VERSION 5.8 ;
BUSBITCHARS "[]" ;
DIVIDERCHAR "/" ;
UNITS
    DATABASE MICRONS 1000 ;
END UNITS

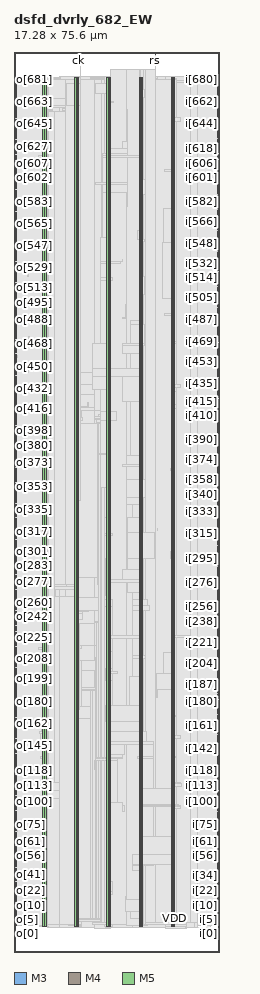
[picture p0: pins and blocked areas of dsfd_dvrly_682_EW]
MACRO dsfd_dvrly_682_EW
  FOREIGN dsfd_dvrly_682_EW 0 0 ;
  CLASS BLOCK ;
  SIZE 17.28 BY 75.6 ;
  PIN ck
    DIRECTION INPUT ;
    USE SIGNAL ;
    PORT
      LAYER M3 ;
        RECT  5.4 75.456 5.418 75.6 ;
    END
  END ck
  PIN ck_o
    DIRECTION OUTPUT ;
    USE SIGNAL ;
    PORT
      LAYER M4 ;
        RECT  0 73.392 0.192 73.416 ;
    END
  END ck_o
  PIN i[0]
    DIRECTION INPUT ;
    USE SIGNAL ;
    PORT
      LAYER M4 ;
        RECT  17.088 2.208 17.28 2.232 ;
    END
  END i[0]
  PIN i[100]
    DIRECTION INPUT ;
    USE SIGNAL ;
    PORT
      LAYER M4 ;
        RECT  17.088 12.672 17.28 12.696 ;
    END
  END i[100]
  PIN i[101]
    DIRECTION INPUT ;
    USE SIGNAL ;
    PORT
      LAYER M4 ;
        RECT  17.088 12.768 17.28 12.792 ;
    END
  END i[101]
  PIN i[102]
    DIRECTION INPUT ;
    USE SIGNAL ;
    PORT
      LAYER M4 ;
        RECT  17.088 12.864 17.28 12.888 ;
    END
  END i[102]
  PIN i[103]
    DIRECTION INPUT ;
    USE SIGNAL ;
    PORT
      LAYER M4 ;
        RECT  17.088 13.008 17.28 13.032 ;
    END
  END i[103]
  PIN i[104]
    DIRECTION INPUT ;
    USE SIGNAL ;
    PORT
      LAYER M4 ;
        RECT  17.088 13.104 17.28 13.128 ;
    END
  END i[104]
  PIN i[105]
    DIRECTION INPUT ;
    USE SIGNAL ;
    PORT
      LAYER M4 ;
        RECT  17.088 13.2 17.28 13.224 ;
    END
  END i[105]
  PIN i[106]
    DIRECTION INPUT ;
    USE SIGNAL ;
    PORT
      LAYER M4 ;
        RECT  17.088 13.296 17.28 13.32 ;
    END
  END i[106]
  PIN i[107]
    DIRECTION INPUT ;
    USE SIGNAL ;
    PORT
      LAYER M4 ;
        RECT  17.088 13.392 17.28 13.416 ;
    END
  END i[107]
  PIN i[108]
    DIRECTION INPUT ;
    USE SIGNAL ;
    PORT
      LAYER M4 ;
        RECT  17.088 13.488 17.28 13.512 ;
    END
  END i[108]
  PIN i[109]
    DIRECTION INPUT ;
    USE SIGNAL ;
    PORT
      LAYER M4 ;
        RECT  17.088 13.632 17.28 13.656 ;
    END
  END i[109]
  PIN i[10]
    DIRECTION INPUT ;
    USE SIGNAL ;
    PORT
      LAYER M4 ;
        RECT  17.088 3.264 17.28 3.288 ;
    END
  END i[10]
  PIN i[110]
    DIRECTION INPUT ;
    USE SIGNAL ;
    PORT
      LAYER M4 ;
        RECT  17.088 13.728 17.28 13.752 ;
    END
  END i[110]
  PIN i[111]
    DIRECTION INPUT ;
    USE SIGNAL ;
    PORT
      LAYER M4 ;
        RECT  17.088 13.824 17.28 13.848 ;
    END
  END i[111]
  PIN i[112]
    DIRECTION INPUT ;
    USE SIGNAL ;
    PORT
      LAYER M4 ;
        RECT  17.088 13.92 17.28 13.944 ;
    END
  END i[112]
  PIN i[113]
    DIRECTION INPUT ;
    USE SIGNAL ;
    PORT
      LAYER M4 ;
        RECT  17.088 14.016 17.28 14.04 ;
    END
  END i[113]
  PIN i[114]
    DIRECTION INPUT ;
    USE SIGNAL ;
    PORT
      LAYER M4 ;
        RECT  17.088 14.16 17.28 14.184 ;
    END
  END i[114]
  PIN i[115]
    DIRECTION INPUT ;
    USE SIGNAL ;
    PORT
      LAYER M4 ;
        RECT  17.088 14.256 17.28 14.28 ;
    END
  END i[115]
  PIN i[116]
    DIRECTION INPUT ;
    USE SIGNAL ;
    PORT
      LAYER M4 ;
        RECT  17.088 14.352 17.28 14.376 ;
    END
  END i[116]
  PIN i[117]
    DIRECTION INPUT ;
    USE SIGNAL ;
    PORT
      LAYER M4 ;
        RECT  17.088 14.448 17.28 14.472 ;
    END
  END i[117]
  PIN i[118]
    DIRECTION INPUT ;
    USE SIGNAL ;
    PORT
      LAYER M4 ;
        RECT  17.088 14.544 17.28 14.568 ;
    END
  END i[118]
  PIN i[119]
    DIRECTION INPUT ;
    USE SIGNAL ;
    PORT
      LAYER M4 ;
        RECT  17.088 14.64 17.28 14.664 ;
    END
  END i[119]
  PIN i[11]
    DIRECTION INPUT ;
    USE SIGNAL ;
    PORT
      LAYER M4 ;
        RECT  17.088 3.36 17.28 3.384 ;
    END
  END i[11]
  PIN i[120]
    DIRECTION INPUT ;
    USE SIGNAL ;
    PORT
      LAYER M4 ;
        RECT  17.088 14.784 17.28 14.808 ;
    END
  END i[120]
  PIN i[121]
    DIRECTION INPUT ;
    USE SIGNAL ;
    PORT
      LAYER M4 ;
        RECT  17.088 14.88 17.28 14.904 ;
    END
  END i[121]
  PIN i[122]
    DIRECTION INPUT ;
    USE SIGNAL ;
    PORT
      LAYER M4 ;
        RECT  17.088 14.976 17.28 15 ;
    END
  END i[122]
  PIN i[123]
    DIRECTION INPUT ;
    USE SIGNAL ;
    PORT
      LAYER M4 ;
        RECT  17.088 15.072 17.28 15.096 ;
    END
  END i[123]
  PIN i[124]
    DIRECTION INPUT ;
    USE SIGNAL ;
    PORT
      LAYER M4 ;
        RECT  17.088 15.168 17.28 15.192 ;
    END
  END i[124]
  PIN i[125]
    DIRECTION INPUT ;
    USE SIGNAL ;
    PORT
      LAYER M4 ;
        RECT  17.088 15.312 17.28 15.336 ;
    END
  END i[125]
  PIN i[126]
    DIRECTION INPUT ;
    USE SIGNAL ;
    PORT
      LAYER M4 ;
        RECT  17.088 15.408 17.28 15.432 ;
    END
  END i[126]
  PIN i[127]
    DIRECTION INPUT ;
    USE SIGNAL ;
    PORT
      LAYER M4 ;
        RECT  17.088 15.504 17.28 15.528 ;
    END
  END i[127]
  PIN i[128]
    DIRECTION INPUT ;
    USE SIGNAL ;
    PORT
      LAYER M4 ;
        RECT  17.088 15.6 17.28 15.624 ;
    END
  END i[128]
  PIN i[129]
    DIRECTION INPUT ;
    USE SIGNAL ;
    PORT
      LAYER M4 ;
        RECT  17.088 15.696 17.28 15.72 ;
    END
  END i[129]
  PIN i[12]
    DIRECTION INPUT ;
    USE SIGNAL ;
    PORT
      LAYER M4 ;
        RECT  17.088 3.456 17.28 3.48 ;
    END
  END i[12]
  PIN i[130]
    DIRECTION INPUT ;
    USE SIGNAL ;
    PORT
      LAYER M4 ;
        RECT  17.088 15.792 17.28 15.816 ;
    END
  END i[130]
  PIN i[131]
    DIRECTION INPUT ;
    USE SIGNAL ;
    PORT
      LAYER M4 ;
        RECT  17.088 15.936 17.28 15.96 ;
    END
  END i[131]
  PIN i[132]
    DIRECTION INPUT ;
    USE SIGNAL ;
    PORT
      LAYER M4 ;
        RECT  17.088 16.032 17.28 16.056 ;
    END
  END i[132]
  PIN i[133]
    DIRECTION INPUT ;
    USE SIGNAL ;
    PORT
      LAYER M4 ;
        RECT  17.088 16.128 17.28 16.152 ;
    END
  END i[133]
  PIN i[134]
    DIRECTION INPUT ;
    USE SIGNAL ;
    PORT
      LAYER M4 ;
        RECT  17.088 16.224 17.28 16.248 ;
    END
  END i[134]
  PIN i[135]
    DIRECTION INPUT ;
    USE SIGNAL ;
    PORT
      LAYER M4 ;
        RECT  17.088 16.32 17.28 16.344 ;
    END
  END i[135]
  PIN i[136]
    DIRECTION INPUT ;
    USE SIGNAL ;
    PORT
      LAYER M4 ;
        RECT  17.088 16.416 17.28 16.44 ;
    END
  END i[136]
  PIN i[137]
    DIRECTION INPUT ;
    USE SIGNAL ;
    PORT
      LAYER M4 ;
        RECT  17.088 16.56 17.28 16.584 ;
    END
  END i[137]
  PIN i[138]
    DIRECTION INPUT ;
    USE SIGNAL ;
    PORT
      LAYER M4 ;
        RECT  17.088 16.656 17.28 16.68 ;
    END
  END i[138]
  PIN i[139]
    DIRECTION INPUT ;
    USE SIGNAL ;
    PORT
      LAYER M4 ;
        RECT  17.088 16.752 17.28 16.776 ;
    END
  END i[139]
  PIN i[13]
    DIRECTION INPUT ;
    USE SIGNAL ;
    PORT
      LAYER M4 ;
        RECT  17.088 3.6 17.28 3.624 ;
    END
  END i[13]
  PIN i[140]
    DIRECTION INPUT ;
    USE SIGNAL ;
    PORT
      LAYER M4 ;
        RECT  17.088 16.848 17.28 16.872 ;
    END
  END i[140]
  PIN i[141]
    DIRECTION INPUT ;
    USE SIGNAL ;
    PORT
      LAYER M4 ;
        RECT  17.088 16.944 17.28 16.968 ;
    END
  END i[141]
  PIN i[142]
    DIRECTION INPUT ;
    USE SIGNAL ;
    PORT
      LAYER M4 ;
        RECT  17.088 17.088 17.28 17.112 ;
    END
  END i[142]
  PIN i[143]
    DIRECTION INPUT ;
    USE SIGNAL ;
    PORT
      LAYER M4 ;
        RECT  17.088 17.184 17.28 17.208 ;
    END
  END i[143]
  PIN i[144]
    DIRECTION INPUT ;
    USE SIGNAL ;
    PORT
      LAYER M4 ;
        RECT  17.088 17.28 17.28 17.304 ;
    END
  END i[144]
  PIN i[145]
    DIRECTION INPUT ;
    USE SIGNAL ;
    PORT
      LAYER M4 ;
        RECT  17.088 17.376 17.28 17.4 ;
    END
  END i[145]
  PIN i[146]
    DIRECTION INPUT ;
    USE SIGNAL ;
    PORT
      LAYER M4 ;
        RECT  17.088 17.472 17.28 17.496 ;
    END
  END i[146]
  PIN i[147]
    DIRECTION INPUT ;
    USE SIGNAL ;
    PORT
      LAYER M4 ;
        RECT  17.088 17.568 17.28 17.592 ;
    END
  END i[147]
  PIN i[148]
    DIRECTION INPUT ;
    USE SIGNAL ;
    PORT
      LAYER M4 ;
        RECT  17.088 17.712 17.28 17.736 ;
    END
  END i[148]
  PIN i[149]
    DIRECTION INPUT ;
    USE SIGNAL ;
    PORT
      LAYER M4 ;
        RECT  17.088 17.808 17.28 17.832 ;
    END
  END i[149]
  PIN i[14]
    DIRECTION INPUT ;
    USE SIGNAL ;
    PORT
      LAYER M4 ;
        RECT  17.088 3.696 17.28 3.72 ;
    END
  END i[14]
  PIN i[150]
    DIRECTION INPUT ;
    USE SIGNAL ;
    PORT
      LAYER M4 ;
        RECT  17.088 17.904 17.28 17.928 ;
    END
  END i[150]
  PIN i[151]
    DIRECTION INPUT ;
    USE SIGNAL ;
    PORT
      LAYER M4 ;
        RECT  17.088 18 17.28 18.024 ;
    END
  END i[151]
  PIN i[152]
    DIRECTION INPUT ;
    USE SIGNAL ;
    PORT
      LAYER M4 ;
        RECT  17.088 18.096 17.28 18.12 ;
    END
  END i[152]
  PIN i[153]
    DIRECTION INPUT ;
    USE SIGNAL ;
    PORT
      LAYER M4 ;
        RECT  17.088 18.192 17.28 18.216 ;
    END
  END i[153]
  PIN i[154]
    DIRECTION INPUT ;
    USE SIGNAL ;
    PORT
      LAYER M4 ;
        RECT  17.088 18.336 17.28 18.36 ;
    END
  END i[154]
  PIN i[155]
    DIRECTION INPUT ;
    USE SIGNAL ;
    PORT
      LAYER M4 ;
        RECT  17.088 18.432 17.28 18.456 ;
    END
  END i[155]
  PIN i[156]
    DIRECTION INPUT ;
    USE SIGNAL ;
    PORT
      LAYER M4 ;
        RECT  17.088 18.528 17.28 18.552 ;
    END
  END i[156]
  PIN i[157]
    DIRECTION INPUT ;
    USE SIGNAL ;
    PORT
      LAYER M4 ;
        RECT  17.088 18.624 17.28 18.648 ;
    END
  END i[157]
  PIN i[158]
    DIRECTION INPUT ;
    USE SIGNAL ;
    PORT
      LAYER M4 ;
        RECT  17.088 18.72 17.28 18.744 ;
    END
  END i[158]
  PIN i[159]
    DIRECTION INPUT ;
    USE SIGNAL ;
    PORT
      LAYER M4 ;
        RECT  17.088 18.864 17.28 18.888 ;
    END
  END i[159]
  PIN i[15]
    DIRECTION INPUT ;
    USE SIGNAL ;
    PORT
      LAYER M4 ;
        RECT  17.088 3.792 17.28 3.816 ;
    END
  END i[15]
  PIN i[160]
    DIRECTION INPUT ;
    USE SIGNAL ;
    PORT
      LAYER M4 ;
        RECT  17.088 18.96 17.28 18.984 ;
    END
  END i[160]
  PIN i[161]
    DIRECTION INPUT ;
    USE SIGNAL ;
    PORT
      LAYER M4 ;
        RECT  17.088 19.056 17.28 19.08 ;
    END
  END i[161]
  PIN i[162]
    DIRECTION INPUT ;
    USE SIGNAL ;
    PORT
      LAYER M4 ;
        RECT  17.088 19.152 17.28 19.176 ;
    END
  END i[162]
  PIN i[163]
    DIRECTION INPUT ;
    USE SIGNAL ;
    PORT
      LAYER M4 ;
        RECT  17.088 19.248 17.28 19.272 ;
    END
  END i[163]
  PIN i[164]
    DIRECTION INPUT ;
    USE SIGNAL ;
    PORT
      LAYER M4 ;
        RECT  17.088 19.344 17.28 19.368 ;
    END
  END i[164]
  PIN i[165]
    DIRECTION INPUT ;
    USE SIGNAL ;
    PORT
      LAYER M4 ;
        RECT  17.088 19.488 17.28 19.512 ;
    END
  END i[165]
  PIN i[166]
    DIRECTION INPUT ;
    USE SIGNAL ;
    PORT
      LAYER M4 ;
        RECT  17.088 19.584 17.28 19.608 ;
    END
  END i[166]
  PIN i[167]
    DIRECTION INPUT ;
    USE SIGNAL ;
    PORT
      LAYER M4 ;
        RECT  17.088 19.68 17.28 19.704 ;
    END
  END i[167]
  PIN i[168]
    DIRECTION INPUT ;
    USE SIGNAL ;
    PORT
      LAYER M4 ;
        RECT  17.088 19.776 17.28 19.8 ;
    END
  END i[168]
  PIN i[169]
    DIRECTION INPUT ;
    USE SIGNAL ;
    PORT
      LAYER M4 ;
        RECT  17.088 19.872 17.28 19.896 ;
    END
  END i[169]
  PIN i[16]
    DIRECTION INPUT ;
    USE SIGNAL ;
    PORT
      LAYER M4 ;
        RECT  17.088 3.888 17.28 3.912 ;
    END
  END i[16]
  PIN i[170]
    DIRECTION INPUT ;
    USE SIGNAL ;
    PORT
      LAYER M4 ;
        RECT  17.088 20.016 17.28 20.04 ;
    END
  END i[170]
  PIN i[171]
    DIRECTION INPUT ;
    USE SIGNAL ;
    PORT
      LAYER M4 ;
        RECT  17.088 20.112 17.28 20.136 ;
    END
  END i[171]
  PIN i[172]
    DIRECTION INPUT ;
    USE SIGNAL ;
    PORT
      LAYER M4 ;
        RECT  17.088 20.208 17.28 20.232 ;
    END
  END i[172]
  PIN i[173]
    DIRECTION INPUT ;
    USE SIGNAL ;
    PORT
      LAYER M4 ;
        RECT  17.088 20.304 17.28 20.328 ;
    END
  END i[173]
  PIN i[174]
    DIRECTION INPUT ;
    USE SIGNAL ;
    PORT
      LAYER M4 ;
        RECT  17.088 20.4 17.28 20.424 ;
    END
  END i[174]
  PIN i[175]
    DIRECTION INPUT ;
    USE SIGNAL ;
    PORT
      LAYER M4 ;
        RECT  17.088 20.496 17.28 20.52 ;
    END
  END i[175]
  PIN i[176]
    DIRECTION INPUT ;
    USE SIGNAL ;
    PORT
      LAYER M4 ;
        RECT  17.088 20.64 17.28 20.664 ;
    END
  END i[176]
  PIN i[177]
    DIRECTION INPUT ;
    USE SIGNAL ;
    PORT
      LAYER M4 ;
        RECT  17.088 20.736 17.28 20.76 ;
    END
  END i[177]
  PIN i[178]
    DIRECTION INPUT ;
    USE SIGNAL ;
    PORT
      LAYER M4 ;
        RECT  17.088 20.832 17.28 20.856 ;
    END
  END i[178]
  PIN i[179]
    DIRECTION INPUT ;
    USE SIGNAL ;
    PORT
      LAYER M4 ;
        RECT  17.088 20.928 17.28 20.952 ;
    END
  END i[179]
  PIN i[17]
    DIRECTION INPUT ;
    USE SIGNAL ;
    PORT
      LAYER M4 ;
        RECT  17.088 3.984 17.28 4.008 ;
    END
  END i[17]
  PIN i[180]
    DIRECTION INPUT ;
    USE SIGNAL ;
    PORT
      LAYER M4 ;
        RECT  17.088 21.024 17.28 21.048 ;
    END
  END i[180]
  PIN i[181]
    DIRECTION INPUT ;
    USE SIGNAL ;
    PORT
      LAYER M4 ;
        RECT  17.088 21.12 17.28 21.144 ;
    END
  END i[181]
  PIN i[182]
    DIRECTION INPUT ;
    USE SIGNAL ;
    PORT
      LAYER M4 ;
        RECT  17.088 21.264 17.28 21.288 ;
    END
  END i[182]
  PIN i[183]
    DIRECTION INPUT ;
    USE SIGNAL ;
    PORT
      LAYER M4 ;
        RECT  17.088 21.36 17.28 21.384 ;
    END
  END i[183]
  PIN i[184]
    DIRECTION INPUT ;
    USE SIGNAL ;
    PORT
      LAYER M4 ;
        RECT  17.088 21.456 17.28 21.48 ;
    END
  END i[184]
  PIN i[185]
    DIRECTION INPUT ;
    USE SIGNAL ;
    PORT
      LAYER M4 ;
        RECT  17.088 21.552 17.28 21.576 ;
    END
  END i[185]
  PIN i[186]
    DIRECTION INPUT ;
    USE SIGNAL ;
    PORT
      LAYER M4 ;
        RECT  17.088 21.648 17.28 21.672 ;
    END
  END i[186]
  PIN i[187]
    DIRECTION INPUT ;
    USE SIGNAL ;
    PORT
      LAYER M4 ;
        RECT  17.088 21.792 17.28 21.816 ;
    END
  END i[187]
  PIN i[188]
    DIRECTION INPUT ;
    USE SIGNAL ;
    PORT
      LAYER M4 ;
        RECT  17.088 21.888 17.28 21.912 ;
    END
  END i[188]
  PIN i[189]
    DIRECTION INPUT ;
    USE SIGNAL ;
    PORT
      LAYER M4 ;
        RECT  17.088 21.984 17.28 22.008 ;
    END
  END i[189]
  PIN i[18]
    DIRECTION INPUT ;
    USE SIGNAL ;
    PORT
      LAYER M4 ;
        RECT  17.088 4.128 17.28 4.152 ;
    END
  END i[18]
  PIN i[190]
    DIRECTION INPUT ;
    USE SIGNAL ;
    PORT
      LAYER M4 ;
        RECT  17.088 22.08 17.28 22.104 ;
    END
  END i[190]
  PIN i[191]
    DIRECTION INPUT ;
    USE SIGNAL ;
    PORT
      LAYER M4 ;
        RECT  17.088 22.176 17.28 22.2 ;
    END
  END i[191]
  PIN i[192]
    DIRECTION INPUT ;
    USE SIGNAL ;
    PORT
      LAYER M4 ;
        RECT  17.088 22.272 17.28 22.296 ;
    END
  END i[192]
  PIN i[193]
    DIRECTION INPUT ;
    USE SIGNAL ;
    PORT
      LAYER M4 ;
        RECT  17.088 22.416 17.28 22.44 ;
    END
  END i[193]
  PIN i[194]
    DIRECTION INPUT ;
    USE SIGNAL ;
    PORT
      LAYER M4 ;
        RECT  17.088 22.512 17.28 22.536 ;
    END
  END i[194]
  PIN i[195]
    DIRECTION INPUT ;
    USE SIGNAL ;
    PORT
      LAYER M4 ;
        RECT  17.088 22.608 17.28 22.632 ;
    END
  END i[195]
  PIN i[196]
    DIRECTION INPUT ;
    USE SIGNAL ;
    PORT
      LAYER M4 ;
        RECT  17.088 22.704 17.28 22.728 ;
    END
  END i[196]
  PIN i[197]
    DIRECTION INPUT ;
    USE SIGNAL ;
    PORT
      LAYER M4 ;
        RECT  17.088 22.8 17.28 22.824 ;
    END
  END i[197]
  PIN i[198]
    DIRECTION INPUT ;
    USE SIGNAL ;
    PORT
      LAYER M4 ;
        RECT  17.088 22.896 17.28 22.92 ;
    END
  END i[198]
  PIN i[199]
    DIRECTION INPUT ;
    USE SIGNAL ;
    PORT
      LAYER M4 ;
        RECT  17.088 23.04 17.28 23.064 ;
    END
  END i[199]
  PIN i[19]
    DIRECTION INPUT ;
    USE SIGNAL ;
    PORT
      LAYER M4 ;
        RECT  17.088 4.224 17.28 4.248 ;
    END
  END i[19]
  PIN i[1]
    DIRECTION INPUT ;
    USE SIGNAL ;
    PORT
      LAYER M4 ;
        RECT  17.088 2.352 17.28 2.376 ;
    END
  END i[1]
  PIN i[200]
    DIRECTION INPUT ;
    USE SIGNAL ;
    PORT
      LAYER M4 ;
        RECT  17.088 23.136 17.28 23.16 ;
    END
  END i[200]
  PIN i[201]
    DIRECTION INPUT ;
    USE SIGNAL ;
    PORT
      LAYER M4 ;
        RECT  17.088 23.232 17.28 23.256 ;
    END
  END i[201]
  PIN i[202]
    DIRECTION INPUT ;
    USE SIGNAL ;
    PORT
      LAYER M4 ;
        RECT  17.088 23.328 17.28 23.352 ;
    END
  END i[202]
  PIN i[203]
    DIRECTION INPUT ;
    USE SIGNAL ;
    PORT
      LAYER M4 ;
        RECT  17.088 23.424 17.28 23.448 ;
    END
  END i[203]
  PIN i[204]
    DIRECTION INPUT ;
    USE SIGNAL ;
    PORT
      LAYER M4 ;
        RECT  17.088 23.568 17.28 23.592 ;
    END
  END i[204]
  PIN i[205]
    DIRECTION INPUT ;
    USE SIGNAL ;
    PORT
      LAYER M4 ;
        RECT  17.088 23.664 17.28 23.688 ;
    END
  END i[205]
  PIN i[206]
    DIRECTION INPUT ;
    USE SIGNAL ;
    PORT
      LAYER M4 ;
        RECT  17.088 23.76 17.28 23.784 ;
    END
  END i[206]
  PIN i[207]
    DIRECTION INPUT ;
    USE SIGNAL ;
    PORT
      LAYER M4 ;
        RECT  17.088 23.856 17.28 23.88 ;
    END
  END i[207]
  PIN i[208]
    DIRECTION INPUT ;
    USE SIGNAL ;
    PORT
      LAYER M4 ;
        RECT  17.088 23.952 17.28 23.976 ;
    END
  END i[208]
  PIN i[209]
    DIRECTION INPUT ;
    USE SIGNAL ;
    PORT
      LAYER M4 ;
        RECT  17.088 24.048 17.28 24.072 ;
    END
  END i[209]
  PIN i[20]
    DIRECTION INPUT ;
    USE SIGNAL ;
    PORT
      LAYER M4 ;
        RECT  17.088 4.32 17.28 4.344 ;
    END
  END i[20]
  PIN i[210]
    DIRECTION INPUT ;
    USE SIGNAL ;
    PORT
      LAYER M4 ;
        RECT  17.088 24.192 17.28 24.216 ;
    END
  END i[210]
  PIN i[211]
    DIRECTION INPUT ;
    USE SIGNAL ;
    PORT
      LAYER M4 ;
        RECT  17.088 24.288 17.28 24.312 ;
    END
  END i[211]
  PIN i[212]
    DIRECTION INPUT ;
    USE SIGNAL ;
    PORT
      LAYER M4 ;
        RECT  17.088 24.384 17.28 24.408 ;
    END
  END i[212]
  PIN i[213]
    DIRECTION INPUT ;
    USE SIGNAL ;
    PORT
      LAYER M4 ;
        RECT  17.088 24.48 17.28 24.504 ;
    END
  END i[213]
  PIN i[214]
    DIRECTION INPUT ;
    USE SIGNAL ;
    PORT
      LAYER M4 ;
        RECT  17.088 24.576 17.28 24.6 ;
    END
  END i[214]
  PIN i[215]
    DIRECTION INPUT ;
    USE SIGNAL ;
    PORT
      LAYER M4 ;
        RECT  17.088 24.672 17.28 24.696 ;
    END
  END i[215]
  PIN i[216]
    DIRECTION INPUT ;
    USE SIGNAL ;
    PORT
      LAYER M4 ;
        RECT  17.088 24.816 17.28 24.84 ;
    END
  END i[216]
  PIN i[217]
    DIRECTION INPUT ;
    USE SIGNAL ;
    PORT
      LAYER M4 ;
        RECT  17.088 24.912 17.28 24.936 ;
    END
  END i[217]
  PIN i[218]
    DIRECTION INPUT ;
    USE SIGNAL ;
    PORT
      LAYER M4 ;
        RECT  17.088 25.008 17.28 25.032 ;
    END
  END i[218]
  PIN i[219]
    DIRECTION INPUT ;
    USE SIGNAL ;
    PORT
      LAYER M4 ;
        RECT  17.088 25.104 17.28 25.128 ;
    END
  END i[219]
  PIN i[21]
    DIRECTION INPUT ;
    USE SIGNAL ;
    PORT
      LAYER M4 ;
        RECT  17.088 4.416 17.28 4.44 ;
    END
  END i[21]
  PIN i[220]
    DIRECTION INPUT ;
    USE SIGNAL ;
    PORT
      LAYER M4 ;
        RECT  17.088 25.2 17.28 25.224 ;
    END
  END i[220]
  PIN i[221]
    DIRECTION INPUT ;
    USE SIGNAL ;
    PORT
      LAYER M4 ;
        RECT  17.088 25.344 17.28 25.368 ;
    END
  END i[221]
  PIN i[222]
    DIRECTION INPUT ;
    USE SIGNAL ;
    PORT
      LAYER M4 ;
        RECT  17.088 25.44 17.28 25.464 ;
    END
  END i[222]
  PIN i[223]
    DIRECTION INPUT ;
    USE SIGNAL ;
    PORT
      LAYER M4 ;
        RECT  17.088 25.536 17.28 25.56 ;
    END
  END i[223]
  PIN i[224]
    DIRECTION INPUT ;
    USE SIGNAL ;
    PORT
      LAYER M4 ;
        RECT  17.088 25.632 17.28 25.656 ;
    END
  END i[224]
  PIN i[225]
    DIRECTION INPUT ;
    USE SIGNAL ;
    PORT
      LAYER M4 ;
        RECT  17.088 25.728 17.28 25.752 ;
    END
  END i[225]
  PIN i[226]
    DIRECTION INPUT ;
    USE SIGNAL ;
    PORT
      LAYER M4 ;
        RECT  17.088 25.824 17.28 25.848 ;
    END
  END i[226]
  PIN i[227]
    DIRECTION INPUT ;
    USE SIGNAL ;
    PORT
      LAYER M4 ;
        RECT  17.088 25.968 17.28 25.992 ;
    END
  END i[227]
  PIN i[228]
    DIRECTION INPUT ;
    USE SIGNAL ;
    PORT
      LAYER M4 ;
        RECT  17.088 26.064 17.28 26.088 ;
    END
  END i[228]
  PIN i[229]
    DIRECTION INPUT ;
    USE SIGNAL ;
    PORT
      LAYER M4 ;
        RECT  17.088 26.16 17.28 26.184 ;
    END
  END i[229]
  PIN i[22]
    DIRECTION INPUT ;
    USE SIGNAL ;
    PORT
      LAYER M4 ;
        RECT  17.088 4.512 17.28 4.536 ;
    END
  END i[22]
  PIN i[230]
    DIRECTION INPUT ;
    USE SIGNAL ;
    PORT
      LAYER M4 ;
        RECT  17.088 26.256 17.28 26.28 ;
    END
  END i[230]
  PIN i[231]
    DIRECTION INPUT ;
    USE SIGNAL ;
    PORT
      LAYER M4 ;
        RECT  17.088 26.352 17.28 26.376 ;
    END
  END i[231]
  PIN i[232]
    DIRECTION INPUT ;
    USE SIGNAL ;
    PORT
      LAYER M4 ;
        RECT  17.088 26.448 17.28 26.472 ;
    END
  END i[232]
  PIN i[233]
    DIRECTION INPUT ;
    USE SIGNAL ;
    PORT
      LAYER M4 ;
        RECT  17.088 26.592 17.28 26.616 ;
    END
  END i[233]
  PIN i[234]
    DIRECTION INPUT ;
    USE SIGNAL ;
    PORT
      LAYER M4 ;
        RECT  17.088 26.688 17.28 26.712 ;
    END
  END i[234]
  PIN i[235]
    DIRECTION INPUT ;
    USE SIGNAL ;
    PORT
      LAYER M4 ;
        RECT  17.088 26.784 17.28 26.808 ;
    END
  END i[235]
  PIN i[236]
    DIRECTION INPUT ;
    USE SIGNAL ;
    PORT
      LAYER M4 ;
        RECT  17.088 26.88 17.28 26.904 ;
    END
  END i[236]
  PIN i[237]
    DIRECTION INPUT ;
    USE SIGNAL ;
    PORT
      LAYER M4 ;
        RECT  17.088 26.976 17.28 27 ;
    END
  END i[237]
  PIN i[238]
    DIRECTION INPUT ;
    USE SIGNAL ;
    PORT
      LAYER M4 ;
        RECT  17.088 27.12 17.28 27.144 ;
    END
  END i[238]
  PIN i[239]
    DIRECTION INPUT ;
    USE SIGNAL ;
    PORT
      LAYER M4 ;
        RECT  17.088 27.216 17.28 27.24 ;
    END
  END i[239]
  PIN i[23]
    DIRECTION INPUT ;
    USE SIGNAL ;
    PORT
      LAYER M4 ;
        RECT  17.088 4.608 17.28 4.632 ;
    END
  END i[23]
  PIN i[240]
    DIRECTION INPUT ;
    USE SIGNAL ;
    PORT
      LAYER M4 ;
        RECT  17.088 27.312 17.28 27.336 ;
    END
  END i[240]
  PIN i[241]
    DIRECTION INPUT ;
    USE SIGNAL ;
    PORT
      LAYER M4 ;
        RECT  17.088 27.408 17.28 27.432 ;
    END
  END i[241]
  PIN i[242]
    DIRECTION INPUT ;
    USE SIGNAL ;
    PORT
      LAYER M4 ;
        RECT  17.088 27.504 17.28 27.528 ;
    END
  END i[242]
  PIN i[243]
    DIRECTION INPUT ;
    USE SIGNAL ;
    PORT
      LAYER M4 ;
        RECT  17.088 27.6 17.28 27.624 ;
    END
  END i[243]
  PIN i[244]
    DIRECTION INPUT ;
    USE SIGNAL ;
    PORT
      LAYER M4 ;
        RECT  17.088 27.744 17.28 27.768 ;
    END
  END i[244]
  PIN i[245]
    DIRECTION INPUT ;
    USE SIGNAL ;
    PORT
      LAYER M4 ;
        RECT  17.088 27.84 17.28 27.864 ;
    END
  END i[245]
  PIN i[246]
    DIRECTION INPUT ;
    USE SIGNAL ;
    PORT
      LAYER M4 ;
        RECT  17.088 27.936 17.28 27.96 ;
    END
  END i[246]
  PIN i[247]
    DIRECTION INPUT ;
    USE SIGNAL ;
    PORT
      LAYER M4 ;
        RECT  17.088 28.032 17.28 28.056 ;
    END
  END i[247]
  PIN i[248]
    DIRECTION INPUT ;
    USE SIGNAL ;
    PORT
      LAYER M4 ;
        RECT  17.088 28.128 17.28 28.152 ;
    END
  END i[248]
  PIN i[249]
    DIRECTION INPUT ;
    USE SIGNAL ;
    PORT
      LAYER M4 ;
        RECT  17.088 28.272 17.28 28.296 ;
    END
  END i[249]
  PIN i[24]
    DIRECTION INPUT ;
    USE SIGNAL ;
    PORT
      LAYER M4 ;
        RECT  17.088 4.752 17.28 4.776 ;
    END
  END i[24]
  PIN i[250]
    DIRECTION INPUT ;
    USE SIGNAL ;
    PORT
      LAYER M4 ;
        RECT  17.088 28.368 17.28 28.392 ;
    END
  END i[250]
  PIN i[251]
    DIRECTION INPUT ;
    USE SIGNAL ;
    PORT
      LAYER M4 ;
        RECT  17.088 28.464 17.28 28.488 ;
    END
  END i[251]
  PIN i[252]
    DIRECTION INPUT ;
    USE SIGNAL ;
    PORT
      LAYER M4 ;
        RECT  17.088 28.56 17.28 28.584 ;
    END
  END i[252]
  PIN i[253]
    DIRECTION INPUT ;
    USE SIGNAL ;
    PORT
      LAYER M4 ;
        RECT  17.088 28.656 17.28 28.68 ;
    END
  END i[253]
  PIN i[254]
    DIRECTION INPUT ;
    USE SIGNAL ;
    PORT
      LAYER M4 ;
        RECT  17.088 28.752 17.28 28.776 ;
    END
  END i[254]
  PIN i[255]
    DIRECTION INPUT ;
    USE SIGNAL ;
    PORT
      LAYER M4 ;
        RECT  17.088 28.896 17.28 28.92 ;
    END
  END i[255]
  PIN i[256]
    DIRECTION INPUT ;
    USE SIGNAL ;
    PORT
      LAYER M4 ;
        RECT  17.088 28.992 17.28 29.016 ;
    END
  END i[256]
  PIN i[257]
    DIRECTION INPUT ;
    USE SIGNAL ;
    PORT
      LAYER M4 ;
        RECT  17.088 29.088 17.28 29.112 ;
    END
  END i[257]
  PIN i[258]
    DIRECTION INPUT ;
    USE SIGNAL ;
    PORT
      LAYER M4 ;
        RECT  17.088 29.184 17.28 29.208 ;
    END
  END i[258]
  PIN i[259]
    DIRECTION INPUT ;
    USE SIGNAL ;
    PORT
      LAYER M4 ;
        RECT  17.088 29.28 17.28 29.304 ;
    END
  END i[259]
  PIN i[25]
    DIRECTION INPUT ;
    USE SIGNAL ;
    PORT
      LAYER M4 ;
        RECT  17.088 4.848 17.28 4.872 ;
    END
  END i[25]
  PIN i[260]
    DIRECTION INPUT ;
    USE SIGNAL ;
    PORT
      LAYER M4 ;
        RECT  17.088 29.376 17.28 29.4 ;
    END
  END i[260]
  PIN i[261]
    DIRECTION INPUT ;
    USE SIGNAL ;
    PORT
      LAYER M4 ;
        RECT  17.088 29.52 17.28 29.544 ;
    END
  END i[261]
  PIN i[262]
    DIRECTION INPUT ;
    USE SIGNAL ;
    PORT
      LAYER M4 ;
        RECT  17.088 29.616 17.28 29.64 ;
    END
  END i[262]
  PIN i[263]
    DIRECTION INPUT ;
    USE SIGNAL ;
    PORT
      LAYER M4 ;
        RECT  17.088 29.712 17.28 29.736 ;
    END
  END i[263]
  PIN i[264]
    DIRECTION INPUT ;
    USE SIGNAL ;
    PORT
      LAYER M4 ;
        RECT  17.088 29.808 17.28 29.832 ;
    END
  END i[264]
  PIN i[265]
    DIRECTION INPUT ;
    USE SIGNAL ;
    PORT
      LAYER M4 ;
        RECT  17.088 29.904 17.28 29.928 ;
    END
  END i[265]
  PIN i[266]
    DIRECTION INPUT ;
    USE SIGNAL ;
    PORT
      LAYER M4 ;
        RECT  17.088 30.048 17.28 30.072 ;
    END
  END i[266]
  PIN i[267]
    DIRECTION INPUT ;
    USE SIGNAL ;
    PORT
      LAYER M4 ;
        RECT  17.088 30.144 17.28 30.168 ;
    END
  END i[267]
  PIN i[268]
    DIRECTION INPUT ;
    USE SIGNAL ;
    PORT
      LAYER M4 ;
        RECT  17.088 30.24 17.28 30.264 ;
    END
  END i[268]
  PIN i[269]
    DIRECTION INPUT ;
    USE SIGNAL ;
    PORT
      LAYER M4 ;
        RECT  17.088 30.336 17.28 30.36 ;
    END
  END i[269]
  PIN i[26]
    DIRECTION INPUT ;
    USE SIGNAL ;
    PORT
      LAYER M4 ;
        RECT  17.088 4.944 17.28 4.968 ;
    END
  END i[26]
  PIN i[270]
    DIRECTION INPUT ;
    USE SIGNAL ;
    PORT
      LAYER M4 ;
        RECT  17.088 30.432 17.28 30.456 ;
    END
  END i[270]
  PIN i[271]
    DIRECTION INPUT ;
    USE SIGNAL ;
    PORT
      LAYER M4 ;
        RECT  17.088 30.528 17.28 30.552 ;
    END
  END i[271]
  PIN i[272]
    DIRECTION INPUT ;
    USE SIGNAL ;
    PORT
      LAYER M4 ;
        RECT  17.088 30.672 17.28 30.696 ;
    END
  END i[272]
  PIN i[273]
    DIRECTION INPUT ;
    USE SIGNAL ;
    PORT
      LAYER M4 ;
        RECT  17.088 30.768 17.28 30.792 ;
    END
  END i[273]
  PIN i[274]
    DIRECTION INPUT ;
    USE SIGNAL ;
    PORT
      LAYER M4 ;
        RECT  17.088 30.864 17.28 30.888 ;
    END
  END i[274]
  PIN i[275]
    DIRECTION INPUT ;
    USE SIGNAL ;
    PORT
      LAYER M4 ;
        RECT  17.088 30.96 17.28 30.984 ;
    END
  END i[275]
  PIN i[276]
    DIRECTION INPUT ;
    USE SIGNAL ;
    PORT
      LAYER M4 ;
        RECT  17.088 31.056 17.28 31.08 ;
    END
  END i[276]
  PIN i[277]
    DIRECTION INPUT ;
    USE SIGNAL ;
    PORT
      LAYER M4 ;
        RECT  17.088 31.152 17.28 31.176 ;
    END
  END i[277]
  PIN i[278]
    DIRECTION INPUT ;
    USE SIGNAL ;
    PORT
      LAYER M4 ;
        RECT  17.088 31.296 17.28 31.32 ;
    END
  END i[278]
  PIN i[279]
    DIRECTION INPUT ;
    USE SIGNAL ;
    PORT
      LAYER M4 ;
        RECT  17.088 31.392 17.28 31.416 ;
    END
  END i[279]
  PIN i[27]
    DIRECTION INPUT ;
    USE SIGNAL ;
    PORT
      LAYER M4 ;
        RECT  17.088 5.04 17.28 5.064 ;
    END
  END i[27]
  PIN i[280]
    DIRECTION INPUT ;
    USE SIGNAL ;
    PORT
      LAYER M4 ;
        RECT  17.088 31.488 17.28 31.512 ;
    END
  END i[280]
  PIN i[281]
    DIRECTION INPUT ;
    USE SIGNAL ;
    PORT
      LAYER M4 ;
        RECT  17.088 31.584 17.28 31.608 ;
    END
  END i[281]
  PIN i[282]
    DIRECTION INPUT ;
    USE SIGNAL ;
    PORT
      LAYER M4 ;
        RECT  17.088 31.68 17.28 31.704 ;
    END
  END i[282]
  PIN i[283]
    DIRECTION INPUT ;
    USE SIGNAL ;
    PORT
      LAYER M4 ;
        RECT  17.088 31.824 17.28 31.848 ;
    END
  END i[283]
  PIN i[284]
    DIRECTION INPUT ;
    USE SIGNAL ;
    PORT
      LAYER M4 ;
        RECT  17.088 31.92 17.28 31.944 ;
    END
  END i[284]
  PIN i[285]
    DIRECTION INPUT ;
    USE SIGNAL ;
    PORT
      LAYER M4 ;
        RECT  17.088 32.016 17.28 32.04 ;
    END
  END i[285]
  PIN i[286]
    DIRECTION INPUT ;
    USE SIGNAL ;
    PORT
      LAYER M4 ;
        RECT  17.088 32.112 17.28 32.136 ;
    END
  END i[286]
  PIN i[287]
    DIRECTION INPUT ;
    USE SIGNAL ;
    PORT
      LAYER M4 ;
        RECT  17.088 32.208 17.28 32.232 ;
    END
  END i[287]
  PIN i[288]
    DIRECTION INPUT ;
    USE SIGNAL ;
    PORT
      LAYER M4 ;
        RECT  17.088 32.304 17.28 32.328 ;
    END
  END i[288]
  PIN i[289]
    DIRECTION INPUT ;
    USE SIGNAL ;
    PORT
      LAYER M4 ;
        RECT  17.088 32.448 17.28 32.472 ;
    END
  END i[289]
  PIN i[28]
    DIRECTION INPUT ;
    USE SIGNAL ;
    PORT
      LAYER M4 ;
        RECT  17.088 5.136 17.28 5.16 ;
    END
  END i[28]
  PIN i[290]
    DIRECTION INPUT ;
    USE SIGNAL ;
    PORT
      LAYER M4 ;
        RECT  17.088 32.544 17.28 32.568 ;
    END
  END i[290]
  PIN i[291]
    DIRECTION INPUT ;
    USE SIGNAL ;
    PORT
      LAYER M4 ;
        RECT  17.088 32.64 17.28 32.664 ;
    END
  END i[291]
  PIN i[292]
    DIRECTION INPUT ;
    USE SIGNAL ;
    PORT
      LAYER M4 ;
        RECT  17.088 32.736 17.28 32.76 ;
    END
  END i[292]
  PIN i[293]
    DIRECTION INPUT ;
    USE SIGNAL ;
    PORT
      LAYER M4 ;
        RECT  17.088 32.832 17.28 32.856 ;
    END
  END i[293]
  PIN i[294]
    DIRECTION INPUT ;
    USE SIGNAL ;
    PORT
      LAYER M4 ;
        RECT  17.088 32.928 17.28 32.952 ;
    END
  END i[294]
  PIN i[295]
    DIRECTION INPUT ;
    USE SIGNAL ;
    PORT
      LAYER M4 ;
        RECT  17.088 33.072 17.28 33.096 ;
    END
  END i[295]
  PIN i[296]
    DIRECTION INPUT ;
    USE SIGNAL ;
    PORT
      LAYER M4 ;
        RECT  17.088 33.168 17.28 33.192 ;
    END
  END i[296]
  PIN i[297]
    DIRECTION INPUT ;
    USE SIGNAL ;
    PORT
      LAYER M4 ;
        RECT  17.088 33.264 17.28 33.288 ;
    END
  END i[297]
  PIN i[298]
    DIRECTION INPUT ;
    USE SIGNAL ;
    PORT
      LAYER M4 ;
        RECT  17.088 33.36 17.28 33.384 ;
    END
  END i[298]
  PIN i[299]
    DIRECTION INPUT ;
    USE SIGNAL ;
    PORT
      LAYER M4 ;
        RECT  17.088 33.456 17.28 33.48 ;
    END
  END i[299]
  PIN i[29]
    DIRECTION INPUT ;
    USE SIGNAL ;
    PORT
      LAYER M4 ;
        RECT  17.088 5.232 17.28 5.256 ;
    END
  END i[29]
  PIN i[2]
    DIRECTION INPUT ;
    USE SIGNAL ;
    PORT
      LAYER M4 ;
        RECT  17.088 2.448 17.28 2.472 ;
    END
  END i[2]
  PIN i[300]
    DIRECTION INPUT ;
    USE SIGNAL ;
    PORT
      LAYER M4 ;
        RECT  17.088 33.6 17.28 33.624 ;
    END
  END i[300]
  PIN i[301]
    DIRECTION INPUT ;
    USE SIGNAL ;
    PORT
      LAYER M4 ;
        RECT  17.088 33.696 17.28 33.72 ;
    END
  END i[301]
  PIN i[302]
    DIRECTION INPUT ;
    USE SIGNAL ;
    PORT
      LAYER M4 ;
        RECT  17.088 33.792 17.28 33.816 ;
    END
  END i[302]
  PIN i[303]
    DIRECTION INPUT ;
    USE SIGNAL ;
    PORT
      LAYER M4 ;
        RECT  17.088 33.888 17.28 33.912 ;
    END
  END i[303]
  PIN i[304]
    DIRECTION INPUT ;
    USE SIGNAL ;
    PORT
      LAYER M4 ;
        RECT  17.088 33.984 17.28 34.008 ;
    END
  END i[304]
  PIN i[305]
    DIRECTION INPUT ;
    USE SIGNAL ;
    PORT
      LAYER M4 ;
        RECT  17.088 34.08 17.28 34.104 ;
    END
  END i[305]
  PIN i[306]
    DIRECTION INPUT ;
    USE SIGNAL ;
    PORT
      LAYER M4 ;
        RECT  17.088 34.224 17.28 34.248 ;
    END
  END i[306]
  PIN i[307]
    DIRECTION INPUT ;
    USE SIGNAL ;
    PORT
      LAYER M4 ;
        RECT  17.088 34.32 17.28 34.344 ;
    END
  END i[307]
  PIN i[308]
    DIRECTION INPUT ;
    USE SIGNAL ;
    PORT
      LAYER M4 ;
        RECT  17.088 34.416 17.28 34.44 ;
    END
  END i[308]
  PIN i[309]
    DIRECTION INPUT ;
    USE SIGNAL ;
    PORT
      LAYER M4 ;
        RECT  17.088 34.512 17.28 34.536 ;
    END
  END i[309]
  PIN i[30]
    DIRECTION INPUT ;
    USE SIGNAL ;
    PORT
      LAYER M4 ;
        RECT  17.088 5.376 17.28 5.4 ;
    END
  END i[30]
  PIN i[310]
    DIRECTION INPUT ;
    USE SIGNAL ;
    PORT
      LAYER M4 ;
        RECT  17.088 34.608 17.28 34.632 ;
    END
  END i[310]
  PIN i[311]
    DIRECTION INPUT ;
    USE SIGNAL ;
    PORT
      LAYER M4 ;
        RECT  17.088 34.752 17.28 34.776 ;
    END
  END i[311]
  PIN i[312]
    DIRECTION INPUT ;
    USE SIGNAL ;
    PORT
      LAYER M4 ;
        RECT  17.088 34.848 17.28 34.872 ;
    END
  END i[312]
  PIN i[313]
    DIRECTION INPUT ;
    USE SIGNAL ;
    PORT
      LAYER M4 ;
        RECT  17.088 34.944 17.28 34.968 ;
    END
  END i[313]
  PIN i[314]
    DIRECTION INPUT ;
    USE SIGNAL ;
    PORT
      LAYER M4 ;
        RECT  17.088 35.04 17.28 35.064 ;
    END
  END i[314]
  PIN i[315]
    DIRECTION INPUT ;
    USE SIGNAL ;
    PORT
      LAYER M4 ;
        RECT  17.088 35.136 17.28 35.16 ;
    END
  END i[315]
  PIN i[316]
    DIRECTION INPUT ;
    USE SIGNAL ;
    PORT
      LAYER M4 ;
        RECT  17.088 35.232 17.28 35.256 ;
    END
  END i[316]
  PIN i[317]
    DIRECTION INPUT ;
    USE SIGNAL ;
    PORT
      LAYER M4 ;
        RECT  17.088 35.376 17.28 35.4 ;
    END
  END i[317]
  PIN i[318]
    DIRECTION INPUT ;
    USE SIGNAL ;
    PORT
      LAYER M4 ;
        RECT  17.088 35.472 17.28 35.496 ;
    END
  END i[318]
  PIN i[319]
    DIRECTION INPUT ;
    USE SIGNAL ;
    PORT
      LAYER M4 ;
        RECT  17.088 35.568 17.28 35.592 ;
    END
  END i[319]
  PIN i[31]
    DIRECTION INPUT ;
    USE SIGNAL ;
    PORT
      LAYER M4 ;
        RECT  17.088 5.472 17.28 5.496 ;
    END
  END i[31]
  PIN i[320]
    DIRECTION INPUT ;
    USE SIGNAL ;
    PORT
      LAYER M4 ;
        RECT  17.088 35.664 17.28 35.688 ;
    END
  END i[320]
  PIN i[321]
    DIRECTION INPUT ;
    USE SIGNAL ;
    PORT
      LAYER M4 ;
        RECT  17.088 35.76 17.28 35.784 ;
    END
  END i[321]
  PIN i[322]
    DIRECTION INPUT ;
    USE SIGNAL ;
    PORT
      LAYER M4 ;
        RECT  17.088 35.856 17.28 35.88 ;
    END
  END i[322]
  PIN i[323]
    DIRECTION INPUT ;
    USE SIGNAL ;
    PORT
      LAYER M4 ;
        RECT  17.088 36 17.28 36.024 ;
    END
  END i[323]
  PIN i[324]
    DIRECTION INPUT ;
    USE SIGNAL ;
    PORT
      LAYER M4 ;
        RECT  17.088 36.096 17.28 36.12 ;
    END
  END i[324]
  PIN i[325]
    DIRECTION INPUT ;
    USE SIGNAL ;
    PORT
      LAYER M4 ;
        RECT  17.088 36.192 17.28 36.216 ;
    END
  END i[325]
  PIN i[326]
    DIRECTION INPUT ;
    USE SIGNAL ;
    PORT
      LAYER M4 ;
        RECT  17.088 36.288 17.28 36.312 ;
    END
  END i[326]
  PIN i[327]
    DIRECTION INPUT ;
    USE SIGNAL ;
    PORT
      LAYER M4 ;
        RECT  17.088 36.384 17.28 36.408 ;
    END
  END i[327]
  PIN i[328]
    DIRECTION INPUT ;
    USE SIGNAL ;
    PORT
      LAYER M4 ;
        RECT  17.088 36.528 17.28 36.552 ;
    END
  END i[328]
  PIN i[329]
    DIRECTION INPUT ;
    USE SIGNAL ;
    PORT
      LAYER M4 ;
        RECT  17.088 36.624 17.28 36.648 ;
    END
  END i[329]
  PIN i[32]
    DIRECTION INPUT ;
    USE SIGNAL ;
    PORT
      LAYER M4 ;
        RECT  17.088 5.568 17.28 5.592 ;
    END
  END i[32]
  PIN i[330]
    DIRECTION INPUT ;
    USE SIGNAL ;
    PORT
      LAYER M4 ;
        RECT  17.088 36.72 17.28 36.744 ;
    END
  END i[330]
  PIN i[331]
    DIRECTION INPUT ;
    USE SIGNAL ;
    PORT
      LAYER M4 ;
        RECT  17.088 36.816 17.28 36.84 ;
    END
  END i[331]
  PIN i[332]
    DIRECTION INPUT ;
    USE SIGNAL ;
    PORT
      LAYER M4 ;
        RECT  17.088 36.912 17.28 36.936 ;
    END
  END i[332]
  PIN i[333]
    DIRECTION INPUT ;
    USE SIGNAL ;
    PORT
      LAYER M4 ;
        RECT  17.088 37.008 17.28 37.032 ;
    END
  END i[333]
  PIN i[334]
    DIRECTION INPUT ;
    USE SIGNAL ;
    PORT
      LAYER M4 ;
        RECT  17.088 37.152 17.28 37.176 ;
    END
  END i[334]
  PIN i[335]
    DIRECTION INPUT ;
    USE SIGNAL ;
    PORT
      LAYER M4 ;
        RECT  17.088 37.248 17.28 37.272 ;
    END
  END i[335]
  PIN i[336]
    DIRECTION INPUT ;
    USE SIGNAL ;
    PORT
      LAYER M4 ;
        RECT  17.088 37.344 17.28 37.368 ;
    END
  END i[336]
  PIN i[337]
    DIRECTION INPUT ;
    USE SIGNAL ;
    PORT
      LAYER M4 ;
        RECT  17.088 37.44 17.28 37.464 ;
    END
  END i[337]
  PIN i[338]
    DIRECTION INPUT ;
    USE SIGNAL ;
    PORT
      LAYER M4 ;
        RECT  17.088 37.536 17.28 37.56 ;
    END
  END i[338]
  PIN i[339]
    DIRECTION INPUT ;
    USE SIGNAL ;
    PORT
      LAYER M4 ;
        RECT  17.088 37.632 17.28 37.656 ;
    END
  END i[339]
  PIN i[33]
    DIRECTION INPUT ;
    USE SIGNAL ;
    PORT
      LAYER M4 ;
        RECT  17.088 5.664 17.28 5.688 ;
    END
  END i[33]
  PIN i[340]
    DIRECTION INPUT ;
    USE SIGNAL ;
    PORT
      LAYER M4 ;
        RECT  17.088 37.776 17.28 37.8 ;
    END
  END i[340]
  PIN i[341]
    DIRECTION INPUT ;
    USE SIGNAL ;
    PORT
      LAYER M4 ;
        RECT  17.088 37.872 17.28 37.896 ;
    END
  END i[341]
  PIN i[342]
    DIRECTION INPUT ;
    USE SIGNAL ;
    PORT
      LAYER M4 ;
        RECT  17.088 37.968 17.28 37.992 ;
    END
  END i[342]
  PIN i[343]
    DIRECTION INPUT ;
    USE SIGNAL ;
    PORT
      LAYER M4 ;
        RECT  17.088 38.064 17.28 38.088 ;
    END
  END i[343]
  PIN i[344]
    DIRECTION INPUT ;
    USE SIGNAL ;
    PORT
      LAYER M4 ;
        RECT  17.088 38.16 17.28 38.184 ;
    END
  END i[344]
  PIN i[345]
    DIRECTION INPUT ;
    USE SIGNAL ;
    PORT
      LAYER M4 ;
        RECT  17.088 38.304 17.28 38.328 ;
    END
  END i[345]
  PIN i[346]
    DIRECTION INPUT ;
    USE SIGNAL ;
    PORT
      LAYER M4 ;
        RECT  17.088 38.4 17.28 38.424 ;
    END
  END i[346]
  PIN i[347]
    DIRECTION INPUT ;
    USE SIGNAL ;
    PORT
      LAYER M4 ;
        RECT  17.088 38.496 17.28 38.52 ;
    END
  END i[347]
  PIN i[348]
    DIRECTION INPUT ;
    USE SIGNAL ;
    PORT
      LAYER M4 ;
        RECT  17.088 38.592 17.28 38.616 ;
    END
  END i[348]
  PIN i[349]
    DIRECTION INPUT ;
    USE SIGNAL ;
    PORT
      LAYER M4 ;
        RECT  17.088 38.688 17.28 38.712 ;
    END
  END i[349]
  PIN i[34]
    DIRECTION INPUT ;
    USE SIGNAL ;
    PORT
      LAYER M4 ;
        RECT  17.088 5.76 17.28 5.784 ;
    END
  END i[34]
  PIN i[350]
    DIRECTION INPUT ;
    USE SIGNAL ;
    PORT
      LAYER M4 ;
        RECT  17.088 38.784 17.28 38.808 ;
    END
  END i[350]
  PIN i[351]
    DIRECTION INPUT ;
    USE SIGNAL ;
    PORT
      LAYER M4 ;
        RECT  17.088 38.928 17.28 38.952 ;
    END
  END i[351]
  PIN i[352]
    DIRECTION INPUT ;
    USE SIGNAL ;
    PORT
      LAYER M4 ;
        RECT  17.088 39.024 17.28 39.048 ;
    END
  END i[352]
  PIN i[353]
    DIRECTION INPUT ;
    USE SIGNAL ;
    PORT
      LAYER M4 ;
        RECT  17.088 39.12 17.28 39.144 ;
    END
  END i[353]
  PIN i[354]
    DIRECTION INPUT ;
    USE SIGNAL ;
    PORT
      LAYER M4 ;
        RECT  17.088 39.216 17.28 39.24 ;
    END
  END i[354]
  PIN i[355]
    DIRECTION INPUT ;
    USE SIGNAL ;
    PORT
      LAYER M4 ;
        RECT  17.088 39.312 17.28 39.336 ;
    END
  END i[355]
  PIN i[356]
    DIRECTION INPUT ;
    USE SIGNAL ;
    PORT
      LAYER M4 ;
        RECT  17.088 39.408 17.28 39.432 ;
    END
  END i[356]
  PIN i[357]
    DIRECTION INPUT ;
    USE SIGNAL ;
    PORT
      LAYER M4 ;
        RECT  17.088 39.552 17.28 39.576 ;
    END
  END i[357]
  PIN i[358]
    DIRECTION INPUT ;
    USE SIGNAL ;
    PORT
      LAYER M4 ;
        RECT  17.088 39.648 17.28 39.672 ;
    END
  END i[358]
  PIN i[359]
    DIRECTION INPUT ;
    USE SIGNAL ;
    PORT
      LAYER M4 ;
        RECT  17.088 39.744 17.28 39.768 ;
    END
  END i[359]
  PIN i[35]
    DIRECTION INPUT ;
    USE SIGNAL ;
    PORT
      LAYER M4 ;
        RECT  17.088 5.904 17.28 5.928 ;
    END
  END i[35]
  PIN i[360]
    DIRECTION INPUT ;
    USE SIGNAL ;
    PORT
      LAYER M4 ;
        RECT  17.088 39.84 17.28 39.864 ;
    END
  END i[360]
  PIN i[361]
    DIRECTION INPUT ;
    USE SIGNAL ;
    PORT
      LAYER M4 ;
        RECT  17.088 39.936 17.28 39.96 ;
    END
  END i[361]
  PIN i[362]
    DIRECTION INPUT ;
    USE SIGNAL ;
    PORT
      LAYER M4 ;
        RECT  17.088 40.08 17.28 40.104 ;
    END
  END i[362]
  PIN i[363]
    DIRECTION INPUT ;
    USE SIGNAL ;
    PORT
      LAYER M4 ;
        RECT  17.088 40.176 17.28 40.2 ;
    END
  END i[363]
  PIN i[364]
    DIRECTION INPUT ;
    USE SIGNAL ;
    PORT
      LAYER M4 ;
        RECT  17.088 40.272 17.28 40.296 ;
    END
  END i[364]
  PIN i[365]
    DIRECTION INPUT ;
    USE SIGNAL ;
    PORT
      LAYER M4 ;
        RECT  17.088 40.368 17.28 40.392 ;
    END
  END i[365]
  PIN i[366]
    DIRECTION INPUT ;
    USE SIGNAL ;
    PORT
      LAYER M4 ;
        RECT  17.088 40.464 17.28 40.488 ;
    END
  END i[366]
  PIN i[367]
    DIRECTION INPUT ;
    USE SIGNAL ;
    PORT
      LAYER M4 ;
        RECT  17.088 40.56 17.28 40.584 ;
    END
  END i[367]
  PIN i[368]
    DIRECTION INPUT ;
    USE SIGNAL ;
    PORT
      LAYER M4 ;
        RECT  17.088 40.704 17.28 40.728 ;
    END
  END i[368]
  PIN i[369]
    DIRECTION INPUT ;
    USE SIGNAL ;
    PORT
      LAYER M4 ;
        RECT  17.088 40.8 17.28 40.824 ;
    END
  END i[369]
  PIN i[36]
    DIRECTION INPUT ;
    USE SIGNAL ;
    PORT
      LAYER M4 ;
        RECT  17.088 6 17.28 6.024 ;
    END
  END i[36]
  PIN i[370]
    DIRECTION INPUT ;
    USE SIGNAL ;
    PORT
      LAYER M4 ;
        RECT  17.088 40.896 17.28 40.92 ;
    END
  END i[370]
  PIN i[371]
    DIRECTION INPUT ;
    USE SIGNAL ;
    PORT
      LAYER M4 ;
        RECT  17.088 40.992 17.28 41.016 ;
    END
  END i[371]
  PIN i[372]
    DIRECTION INPUT ;
    USE SIGNAL ;
    PORT
      LAYER M4 ;
        RECT  17.088 41.088 17.28 41.112 ;
    END
  END i[372]
  PIN i[373]
    DIRECTION INPUT ;
    USE SIGNAL ;
    PORT
      LAYER M4 ;
        RECT  17.088 41.232 17.28 41.256 ;
    END
  END i[373]
  PIN i[374]
    DIRECTION INPUT ;
    USE SIGNAL ;
    PORT
      LAYER M4 ;
        RECT  17.088 41.328 17.28 41.352 ;
    END
  END i[374]
  PIN i[375]
    DIRECTION INPUT ;
    USE SIGNAL ;
    PORT
      LAYER M4 ;
        RECT  17.088 41.424 17.28 41.448 ;
    END
  END i[375]
  PIN i[376]
    DIRECTION INPUT ;
    USE SIGNAL ;
    PORT
      LAYER M4 ;
        RECT  17.088 41.52 17.28 41.544 ;
    END
  END i[376]
  PIN i[377]
    DIRECTION INPUT ;
    USE SIGNAL ;
    PORT
      LAYER M4 ;
        RECT  17.088 41.616 17.28 41.64 ;
    END
  END i[377]
  PIN i[378]
    DIRECTION INPUT ;
    USE SIGNAL ;
    PORT
      LAYER M4 ;
        RECT  17.088 41.712 17.28 41.736 ;
    END
  END i[378]
  PIN i[379]
    DIRECTION INPUT ;
    USE SIGNAL ;
    PORT
      LAYER M4 ;
        RECT  17.088 41.856 17.28 41.88 ;
    END
  END i[379]
  PIN i[37]
    DIRECTION INPUT ;
    USE SIGNAL ;
    PORT
      LAYER M4 ;
        RECT  17.088 6.096 17.28 6.12 ;
    END
  END i[37]
  PIN i[380]
    DIRECTION INPUT ;
    USE SIGNAL ;
    PORT
      LAYER M4 ;
        RECT  17.088 41.952 17.28 41.976 ;
    END
  END i[380]
  PIN i[381]
    DIRECTION INPUT ;
    USE SIGNAL ;
    PORT
      LAYER M4 ;
        RECT  17.088 42.048 17.28 42.072 ;
    END
  END i[381]
  PIN i[382]
    DIRECTION INPUT ;
    USE SIGNAL ;
    PORT
      LAYER M4 ;
        RECT  17.088 42.144 17.28 42.168 ;
    END
  END i[382]
  PIN i[383]
    DIRECTION INPUT ;
    USE SIGNAL ;
    PORT
      LAYER M4 ;
        RECT  17.088 42.24 17.28 42.264 ;
    END
  END i[383]
  PIN i[384]
    DIRECTION INPUT ;
    USE SIGNAL ;
    PORT
      LAYER M4 ;
        RECT  17.088 42.336 17.28 42.36 ;
    END
  END i[384]
  PIN i[385]
    DIRECTION INPUT ;
    USE SIGNAL ;
    PORT
      LAYER M4 ;
        RECT  17.088 42.48 17.28 42.504 ;
    END
  END i[385]
  PIN i[386]
    DIRECTION INPUT ;
    USE SIGNAL ;
    PORT
      LAYER M4 ;
        RECT  17.088 42.576 17.28 42.6 ;
    END
  END i[386]
  PIN i[387]
    DIRECTION INPUT ;
    USE SIGNAL ;
    PORT
      LAYER M4 ;
        RECT  17.088 42.672 17.28 42.696 ;
    END
  END i[387]
  PIN i[388]
    DIRECTION INPUT ;
    USE SIGNAL ;
    PORT
      LAYER M4 ;
        RECT  17.088 42.768 17.28 42.792 ;
    END
  END i[388]
  PIN i[389]
    DIRECTION INPUT ;
    USE SIGNAL ;
    PORT
      LAYER M4 ;
        RECT  17.088 42.864 17.28 42.888 ;
    END
  END i[389]
  PIN i[38]
    DIRECTION INPUT ;
    USE SIGNAL ;
    PORT
      LAYER M4 ;
        RECT  17.088 6.192 17.28 6.216 ;
    END
  END i[38]
  PIN i[390]
    DIRECTION INPUT ;
    USE SIGNAL ;
    PORT
      LAYER M4 ;
        RECT  17.088 43.008 17.28 43.032 ;
    END
  END i[390]
  PIN i[391]
    DIRECTION INPUT ;
    USE SIGNAL ;
    PORT
      LAYER M4 ;
        RECT  17.088 43.104 17.28 43.128 ;
    END
  END i[391]
  PIN i[392]
    DIRECTION INPUT ;
    USE SIGNAL ;
    PORT
      LAYER M4 ;
        RECT  17.088 43.2 17.28 43.224 ;
    END
  END i[392]
  PIN i[393]
    DIRECTION INPUT ;
    USE SIGNAL ;
    PORT
      LAYER M4 ;
        RECT  17.088 43.296 17.28 43.32 ;
    END
  END i[393]
  PIN i[394]
    DIRECTION INPUT ;
    USE SIGNAL ;
    PORT
      LAYER M4 ;
        RECT  17.088 43.392 17.28 43.416 ;
    END
  END i[394]
  PIN i[395]
    DIRECTION INPUT ;
    USE SIGNAL ;
    PORT
      LAYER M4 ;
        RECT  17.088 43.488 17.28 43.512 ;
    END
  END i[395]
  PIN i[396]
    DIRECTION INPUT ;
    USE SIGNAL ;
    PORT
      LAYER M4 ;
        RECT  17.088 43.632 17.28 43.656 ;
    END
  END i[396]
  PIN i[397]
    DIRECTION INPUT ;
    USE SIGNAL ;
    PORT
      LAYER M4 ;
        RECT  17.088 43.728 17.28 43.752 ;
    END
  END i[397]
  PIN i[398]
    DIRECTION INPUT ;
    USE SIGNAL ;
    PORT
      LAYER M4 ;
        RECT  17.088 43.824 17.28 43.848 ;
    END
  END i[398]
  PIN i[399]
    DIRECTION INPUT ;
    USE SIGNAL ;
    PORT
      LAYER M4 ;
        RECT  17.088 43.92 17.28 43.944 ;
    END
  END i[399]
  PIN i[39]
    DIRECTION INPUT ;
    USE SIGNAL ;
    PORT
      LAYER M4 ;
        RECT  17.088 6.288 17.28 6.312 ;
    END
  END i[39]
  PIN i[3]
    DIRECTION INPUT ;
    USE SIGNAL ;
    PORT
      LAYER M4 ;
        RECT  17.088 2.544 17.28 2.568 ;
    END
  END i[3]
  PIN i[400]
    DIRECTION INPUT ;
    USE SIGNAL ;
    PORT
      LAYER M4 ;
        RECT  17.088 44.016 17.28 44.04 ;
    END
  END i[400]
  PIN i[401]
    DIRECTION INPUT ;
    USE SIGNAL ;
    PORT
      LAYER M4 ;
        RECT  17.088 44.112 17.28 44.136 ;
    END
  END i[401]
  PIN i[402]
    DIRECTION INPUT ;
    USE SIGNAL ;
    PORT
      LAYER M4 ;
        RECT  17.088 44.256 17.28 44.28 ;
    END
  END i[402]
  PIN i[403]
    DIRECTION INPUT ;
    USE SIGNAL ;
    PORT
      LAYER M4 ;
        RECT  17.088 44.352 17.28 44.376 ;
    END
  END i[403]
  PIN i[404]
    DIRECTION INPUT ;
    USE SIGNAL ;
    PORT
      LAYER M4 ;
        RECT  17.088 44.448 17.28 44.472 ;
    END
  END i[404]
  PIN i[405]
    DIRECTION INPUT ;
    USE SIGNAL ;
    PORT
      LAYER M4 ;
        RECT  17.088 44.544 17.28 44.568 ;
    END
  END i[405]
  PIN i[406]
    DIRECTION INPUT ;
    USE SIGNAL ;
    PORT
      LAYER M4 ;
        RECT  17.088 44.64 17.28 44.664 ;
    END
  END i[406]
  PIN i[407]
    DIRECTION INPUT ;
    USE SIGNAL ;
    PORT
      LAYER M4 ;
        RECT  17.088 44.784 17.28 44.808 ;
    END
  END i[407]
  PIN i[408]
    DIRECTION INPUT ;
    USE SIGNAL ;
    PORT
      LAYER M4 ;
        RECT  17.088 44.88 17.28 44.904 ;
    END
  END i[408]
  PIN i[409]
    DIRECTION INPUT ;
    USE SIGNAL ;
    PORT
      LAYER M4 ;
        RECT  17.088 44.976 17.28 45 ;
    END
  END i[409]
  PIN i[40]
    DIRECTION INPUT ;
    USE SIGNAL ;
    PORT
      LAYER M4 ;
        RECT  17.088 6.384 17.28 6.408 ;
    END
  END i[40]
  PIN i[410]
    DIRECTION INPUT ;
    USE SIGNAL ;
    PORT
      LAYER M4 ;
        RECT  17.088 45.072 17.28 45.096 ;
    END
  END i[410]
  PIN i[411]
    DIRECTION INPUT ;
    USE SIGNAL ;
    PORT
      LAYER M4 ;
        RECT  17.088 45.168 17.28 45.192 ;
    END
  END i[411]
  PIN i[412]
    DIRECTION INPUT ;
    USE SIGNAL ;
    PORT
      LAYER M4 ;
        RECT  17.088 45.264 17.28 45.288 ;
    END
  END i[412]
  PIN i[413]
    DIRECTION INPUT ;
    USE SIGNAL ;
    PORT
      LAYER M4 ;
        RECT  17.088 45.408 17.28 45.432 ;
    END
  END i[413]
  PIN i[414]
    DIRECTION INPUT ;
    USE SIGNAL ;
    PORT
      LAYER M4 ;
        RECT  17.088 45.504 17.28 45.528 ;
    END
  END i[414]
  PIN i[415]
    DIRECTION INPUT ;
    USE SIGNAL ;
    PORT
      LAYER M4 ;
        RECT  17.088 45.6 17.28 45.624 ;
    END
  END i[415]
  PIN i[416]
    DIRECTION INPUT ;
    USE SIGNAL ;
    PORT
      LAYER M4 ;
        RECT  17.088 45.696 17.28 45.72 ;
    END
  END i[416]
  PIN i[417]
    DIRECTION INPUT ;
    USE SIGNAL ;
    PORT
      LAYER M4 ;
        RECT  17.088 45.792 17.28 45.816 ;
    END
  END i[417]
  PIN i[418]
    DIRECTION INPUT ;
    USE SIGNAL ;
    PORT
      LAYER M4 ;
        RECT  17.088 45.936 17.28 45.96 ;
    END
  END i[418]
  PIN i[419]
    DIRECTION INPUT ;
    USE SIGNAL ;
    PORT
      LAYER M4 ;
        RECT  17.088 46.032 17.28 46.056 ;
    END
  END i[419]
  PIN i[41]
    DIRECTION INPUT ;
    USE SIGNAL ;
    PORT
      LAYER M4 ;
        RECT  17.088 6.528 17.28 6.552 ;
    END
  END i[41]
  PIN i[420]
    DIRECTION INPUT ;
    USE SIGNAL ;
    PORT
      LAYER M4 ;
        RECT  17.088 46.128 17.28 46.152 ;
    END
  END i[420]
  PIN i[421]
    DIRECTION INPUT ;
    USE SIGNAL ;
    PORT
      LAYER M4 ;
        RECT  17.088 46.224 17.28 46.248 ;
    END
  END i[421]
  PIN i[422]
    DIRECTION INPUT ;
    USE SIGNAL ;
    PORT
      LAYER M4 ;
        RECT  17.088 46.32 17.28 46.344 ;
    END
  END i[422]
  PIN i[423]
    DIRECTION INPUT ;
    USE SIGNAL ;
    PORT
      LAYER M4 ;
        RECT  17.088 46.416 17.28 46.44 ;
    END
  END i[423]
  PIN i[424]
    DIRECTION INPUT ;
    USE SIGNAL ;
    PORT
      LAYER M4 ;
        RECT  17.088 46.56 17.28 46.584 ;
    END
  END i[424]
  PIN i[425]
    DIRECTION INPUT ;
    USE SIGNAL ;
    PORT
      LAYER M4 ;
        RECT  17.088 46.656 17.28 46.68 ;
    END
  END i[425]
  PIN i[426]
    DIRECTION INPUT ;
    USE SIGNAL ;
    PORT
      LAYER M4 ;
        RECT  17.088 46.752 17.28 46.776 ;
    END
  END i[426]
  PIN i[427]
    DIRECTION INPUT ;
    USE SIGNAL ;
    PORT
      LAYER M4 ;
        RECT  17.088 46.848 17.28 46.872 ;
    END
  END i[427]
  PIN i[428]
    DIRECTION INPUT ;
    USE SIGNAL ;
    PORT
      LAYER M4 ;
        RECT  17.088 46.944 17.28 46.968 ;
    END
  END i[428]
  PIN i[429]
    DIRECTION INPUT ;
    USE SIGNAL ;
    PORT
      LAYER M4 ;
        RECT  17.088 47.04 17.28 47.064 ;
    END
  END i[429]
  PIN i[42]
    DIRECTION INPUT ;
    USE SIGNAL ;
    PORT
      LAYER M4 ;
        RECT  17.088 6.624 17.28 6.648 ;
    END
  END i[42]
  PIN i[430]
    DIRECTION INPUT ;
    USE SIGNAL ;
    PORT
      LAYER M4 ;
        RECT  17.088 47.184 17.28 47.208 ;
    END
  END i[430]
  PIN i[431]
    DIRECTION INPUT ;
    USE SIGNAL ;
    PORT
      LAYER M4 ;
        RECT  17.088 47.28 17.28 47.304 ;
    END
  END i[431]
  PIN i[432]
    DIRECTION INPUT ;
    USE SIGNAL ;
    PORT
      LAYER M4 ;
        RECT  17.088 47.376 17.28 47.4 ;
    END
  END i[432]
  PIN i[433]
    DIRECTION INPUT ;
    USE SIGNAL ;
    PORT
      LAYER M4 ;
        RECT  17.088 47.472 17.28 47.496 ;
    END
  END i[433]
  PIN i[434]
    DIRECTION INPUT ;
    USE SIGNAL ;
    PORT
      LAYER M4 ;
        RECT  17.088 47.568 17.28 47.592 ;
    END
  END i[434]
  PIN i[435]
    DIRECTION INPUT ;
    USE SIGNAL ;
    PORT
      LAYER M4 ;
        RECT  17.088 47.712 17.28 47.736 ;
    END
  END i[435]
  PIN i[436]
    DIRECTION INPUT ;
    USE SIGNAL ;
    PORT
      LAYER M4 ;
        RECT  17.088 47.808 17.28 47.832 ;
    END
  END i[436]
  PIN i[437]
    DIRECTION INPUT ;
    USE SIGNAL ;
    PORT
      LAYER M4 ;
        RECT  17.088 47.904 17.28 47.928 ;
    END
  END i[437]
  PIN i[438]
    DIRECTION INPUT ;
    USE SIGNAL ;
    PORT
      LAYER M4 ;
        RECT  17.088 48 17.28 48.024 ;
    END
  END i[438]
  PIN i[439]
    DIRECTION INPUT ;
    USE SIGNAL ;
    PORT
      LAYER M4 ;
        RECT  17.088 48.096 17.28 48.12 ;
    END
  END i[439]
  PIN i[43]
    DIRECTION INPUT ;
    USE SIGNAL ;
    PORT
      LAYER M4 ;
        RECT  17.088 6.72 17.28 6.744 ;
    END
  END i[43]
  PIN i[440]
    DIRECTION INPUT ;
    USE SIGNAL ;
    PORT
      LAYER M4 ;
        RECT  17.088 48.192 17.28 48.216 ;
    END
  END i[440]
  PIN i[441]
    DIRECTION INPUT ;
    USE SIGNAL ;
    PORT
      LAYER M4 ;
        RECT  17.088 48.336 17.28 48.36 ;
    END
  END i[441]
  PIN i[442]
    DIRECTION INPUT ;
    USE SIGNAL ;
    PORT
      LAYER M4 ;
        RECT  17.088 48.432 17.28 48.456 ;
    END
  END i[442]
  PIN i[443]
    DIRECTION INPUT ;
    USE SIGNAL ;
    PORT
      LAYER M4 ;
        RECT  17.088 48.528 17.28 48.552 ;
    END
  END i[443]
  PIN i[444]
    DIRECTION INPUT ;
    USE SIGNAL ;
    PORT
      LAYER M4 ;
        RECT  17.088 48.624 17.28 48.648 ;
    END
  END i[444]
  PIN i[445]
    DIRECTION INPUT ;
    USE SIGNAL ;
    PORT
      LAYER M4 ;
        RECT  17.088 48.72 17.28 48.744 ;
    END
  END i[445]
  PIN i[446]
    DIRECTION INPUT ;
    USE SIGNAL ;
    PORT
      LAYER M4 ;
        RECT  17.088 48.816 17.28 48.84 ;
    END
  END i[446]
  PIN i[447]
    DIRECTION INPUT ;
    USE SIGNAL ;
    PORT
      LAYER M4 ;
        RECT  17.088 48.96 17.28 48.984 ;
    END
  END i[447]
  PIN i[448]
    DIRECTION INPUT ;
    USE SIGNAL ;
    PORT
      LAYER M4 ;
        RECT  17.088 49.056 17.28 49.08 ;
    END
  END i[448]
  PIN i[449]
    DIRECTION INPUT ;
    USE SIGNAL ;
    PORT
      LAYER M4 ;
        RECT  17.088 49.152 17.28 49.176 ;
    END
  END i[449]
  PIN i[44]
    DIRECTION INPUT ;
    USE SIGNAL ;
    PORT
      LAYER M4 ;
        RECT  17.088 6.816 17.28 6.84 ;
    END
  END i[44]
  PIN i[450]
    DIRECTION INPUT ;
    USE SIGNAL ;
    PORT
      LAYER M4 ;
        RECT  17.088 49.248 17.28 49.272 ;
    END
  END i[450]
  PIN i[451]
    DIRECTION INPUT ;
    USE SIGNAL ;
    PORT
      LAYER M4 ;
        RECT  17.088 49.344 17.28 49.368 ;
    END
  END i[451]
  PIN i[452]
    DIRECTION INPUT ;
    USE SIGNAL ;
    PORT
      LAYER M4 ;
        RECT  17.088 49.488 17.28 49.512 ;
    END
  END i[452]
  PIN i[453]
    DIRECTION INPUT ;
    USE SIGNAL ;
    PORT
      LAYER M4 ;
        RECT  17.088 49.584 17.28 49.608 ;
    END
  END i[453]
  PIN i[454]
    DIRECTION INPUT ;
    USE SIGNAL ;
    PORT
      LAYER M4 ;
        RECT  17.088 49.68 17.28 49.704 ;
    END
  END i[454]
  PIN i[455]
    DIRECTION INPUT ;
    USE SIGNAL ;
    PORT
      LAYER M4 ;
        RECT  17.088 49.776 17.28 49.8 ;
    END
  END i[455]
  PIN i[456]
    DIRECTION INPUT ;
    USE SIGNAL ;
    PORT
      LAYER M4 ;
        RECT  17.088 49.872 17.28 49.896 ;
    END
  END i[456]
  PIN i[457]
    DIRECTION INPUT ;
    USE SIGNAL ;
    PORT
      LAYER M4 ;
        RECT  17.088 49.968 17.28 49.992 ;
    END
  END i[457]
  PIN i[458]
    DIRECTION INPUT ;
    USE SIGNAL ;
    PORT
      LAYER M4 ;
        RECT  17.088 50.112 17.28 50.136 ;
    END
  END i[458]
  PIN i[459]
    DIRECTION INPUT ;
    USE SIGNAL ;
    PORT
      LAYER M4 ;
        RECT  17.088 50.208 17.28 50.232 ;
    END
  END i[459]
  PIN i[45]
    DIRECTION INPUT ;
    USE SIGNAL ;
    PORT
      LAYER M4 ;
        RECT  17.088 6.912 17.28 6.936 ;
    END
  END i[45]
  PIN i[460]
    DIRECTION INPUT ;
    USE SIGNAL ;
    PORT
      LAYER M4 ;
        RECT  17.088 50.304 17.28 50.328 ;
    END
  END i[460]
  PIN i[461]
    DIRECTION INPUT ;
    USE SIGNAL ;
    PORT
      LAYER M4 ;
        RECT  17.088 50.4 17.28 50.424 ;
    END
  END i[461]
  PIN i[462]
    DIRECTION INPUT ;
    USE SIGNAL ;
    PORT
      LAYER M4 ;
        RECT  17.088 50.496 17.28 50.52 ;
    END
  END i[462]
  PIN i[463]
    DIRECTION INPUT ;
    USE SIGNAL ;
    PORT
      LAYER M4 ;
        RECT  17.088 50.592 17.28 50.616 ;
    END
  END i[463]
  PIN i[464]
    DIRECTION INPUT ;
    USE SIGNAL ;
    PORT
      LAYER M4 ;
        RECT  17.088 50.736 17.28 50.76 ;
    END
  END i[464]
  PIN i[465]
    DIRECTION INPUT ;
    USE SIGNAL ;
    PORT
      LAYER M4 ;
        RECT  17.088 50.832 17.28 50.856 ;
    END
  END i[465]
  PIN i[466]
    DIRECTION INPUT ;
    USE SIGNAL ;
    PORT
      LAYER M4 ;
        RECT  17.088 50.928 17.28 50.952 ;
    END
  END i[466]
  PIN i[467]
    DIRECTION INPUT ;
    USE SIGNAL ;
    PORT
      LAYER M4 ;
        RECT  17.088 51.024 17.28 51.048 ;
    END
  END i[467]
  PIN i[468]
    DIRECTION INPUT ;
    USE SIGNAL ;
    PORT
      LAYER M4 ;
        RECT  17.088 51.12 17.28 51.144 ;
    END
  END i[468]
  PIN i[469]
    DIRECTION INPUT ;
    USE SIGNAL ;
    PORT
      LAYER M4 ;
        RECT  17.088 51.264 17.28 51.288 ;
    END
  END i[469]
  PIN i[46]
    DIRECTION INPUT ;
    USE SIGNAL ;
    PORT
      LAYER M4 ;
        RECT  17.088 7.056 17.28 7.08 ;
    END
  END i[46]
  PIN i[470]
    DIRECTION INPUT ;
    USE SIGNAL ;
    PORT
      LAYER M4 ;
        RECT  17.088 51.36 17.28 51.384 ;
    END
  END i[470]
  PIN i[471]
    DIRECTION INPUT ;
    USE SIGNAL ;
    PORT
      LAYER M4 ;
        RECT  17.088 51.456 17.28 51.48 ;
    END
  END i[471]
  PIN i[472]
    DIRECTION INPUT ;
    USE SIGNAL ;
    PORT
      LAYER M4 ;
        RECT  17.088 51.552 17.28 51.576 ;
    END
  END i[472]
  PIN i[473]
    DIRECTION INPUT ;
    USE SIGNAL ;
    PORT
      LAYER M4 ;
        RECT  17.088 51.648 17.28 51.672 ;
    END
  END i[473]
  PIN i[474]
    DIRECTION INPUT ;
    USE SIGNAL ;
    PORT
      LAYER M4 ;
        RECT  17.088 51.744 17.28 51.768 ;
    END
  END i[474]
  PIN i[475]
    DIRECTION INPUT ;
    USE SIGNAL ;
    PORT
      LAYER M4 ;
        RECT  17.088 51.888 17.28 51.912 ;
    END
  END i[475]
  PIN i[476]
    DIRECTION INPUT ;
    USE SIGNAL ;
    PORT
      LAYER M4 ;
        RECT  17.088 51.984 17.28 52.008 ;
    END
  END i[476]
  PIN i[477]
    DIRECTION INPUT ;
    USE SIGNAL ;
    PORT
      LAYER M4 ;
        RECT  17.088 52.08 17.28 52.104 ;
    END
  END i[477]
  PIN i[478]
    DIRECTION INPUT ;
    USE SIGNAL ;
    PORT
      LAYER M4 ;
        RECT  17.088 52.176 17.28 52.2 ;
    END
  END i[478]
  PIN i[479]
    DIRECTION INPUT ;
    USE SIGNAL ;
    PORT
      LAYER M4 ;
        RECT  17.088 52.272 17.28 52.296 ;
    END
  END i[479]
  PIN i[47]
    DIRECTION INPUT ;
    USE SIGNAL ;
    PORT
      LAYER M4 ;
        RECT  17.088 7.152 17.28 7.176 ;
    END
  END i[47]
  PIN i[480]
    DIRECTION INPUT ;
    USE SIGNAL ;
    PORT
      LAYER M4 ;
        RECT  17.088 52.416 17.28 52.44 ;
    END
  END i[480]
  PIN i[481]
    DIRECTION INPUT ;
    USE SIGNAL ;
    PORT
      LAYER M4 ;
        RECT  17.088 52.512 17.28 52.536 ;
    END
  END i[481]
  PIN i[482]
    DIRECTION INPUT ;
    USE SIGNAL ;
    PORT
      LAYER M4 ;
        RECT  17.088 52.608 17.28 52.632 ;
    END
  END i[482]
  PIN i[483]
    DIRECTION INPUT ;
    USE SIGNAL ;
    PORT
      LAYER M4 ;
        RECT  17.088 52.704 17.28 52.728 ;
    END
  END i[483]
  PIN i[484]
    DIRECTION INPUT ;
    USE SIGNAL ;
    PORT
      LAYER M4 ;
        RECT  17.088 52.8 17.28 52.824 ;
    END
  END i[484]
  PIN i[485]
    DIRECTION INPUT ;
    USE SIGNAL ;
    PORT
      LAYER M4 ;
        RECT  17.088 52.896 17.28 52.92 ;
    END
  END i[485]
  PIN i[486]
    DIRECTION INPUT ;
    USE SIGNAL ;
    PORT
      LAYER M4 ;
        RECT  17.088 53.04 17.28 53.064 ;
    END
  END i[486]
  PIN i[487]
    DIRECTION INPUT ;
    USE SIGNAL ;
    PORT
      LAYER M4 ;
        RECT  17.088 53.136 17.28 53.16 ;
    END
  END i[487]
  PIN i[488]
    DIRECTION INPUT ;
    USE SIGNAL ;
    PORT
      LAYER M4 ;
        RECT  17.088 53.232 17.28 53.256 ;
    END
  END i[488]
  PIN i[489]
    DIRECTION INPUT ;
    USE SIGNAL ;
    PORT
      LAYER M4 ;
        RECT  17.088 53.328 17.28 53.352 ;
    END
  END i[489]
  PIN i[48]
    DIRECTION INPUT ;
    USE SIGNAL ;
    PORT
      LAYER M4 ;
        RECT  17.088 7.248 17.28 7.272 ;
    END
  END i[48]
  PIN i[490]
    DIRECTION INPUT ;
    USE SIGNAL ;
    PORT
      LAYER M4 ;
        RECT  17.088 53.424 17.28 53.448 ;
    END
  END i[490]
  PIN i[491]
    DIRECTION INPUT ;
    USE SIGNAL ;
    PORT
      LAYER M4 ;
        RECT  17.088 53.52 17.28 53.544 ;
    END
  END i[491]
  PIN i[492]
    DIRECTION INPUT ;
    USE SIGNAL ;
    PORT
      LAYER M4 ;
        RECT  17.088 53.664 17.28 53.688 ;
    END
  END i[492]
  PIN i[493]
    DIRECTION INPUT ;
    USE SIGNAL ;
    PORT
      LAYER M4 ;
        RECT  17.088 53.76 17.28 53.784 ;
    END
  END i[493]
  PIN i[494]
    DIRECTION INPUT ;
    USE SIGNAL ;
    PORT
      LAYER M4 ;
        RECT  17.088 53.856 17.28 53.88 ;
    END
  END i[494]
  PIN i[495]
    DIRECTION INPUT ;
    USE SIGNAL ;
    PORT
      LAYER M4 ;
        RECT  17.088 53.952 17.28 53.976 ;
    END
  END i[495]
  PIN i[496]
    DIRECTION INPUT ;
    USE SIGNAL ;
    PORT
      LAYER M4 ;
        RECT  17.088 54.048 17.28 54.072 ;
    END
  END i[496]
  PIN i[497]
    DIRECTION INPUT ;
    USE SIGNAL ;
    PORT
      LAYER M4 ;
        RECT  17.088 54.192 17.28 54.216 ;
    END
  END i[497]
  PIN i[498]
    DIRECTION INPUT ;
    USE SIGNAL ;
    PORT
      LAYER M4 ;
        RECT  17.088 54.288 17.28 54.312 ;
    END
  END i[498]
  PIN i[499]
    DIRECTION INPUT ;
    USE SIGNAL ;
    PORT
      LAYER M4 ;
        RECT  17.088 54.384 17.28 54.408 ;
    END
  END i[499]
  PIN i[49]
    DIRECTION INPUT ;
    USE SIGNAL ;
    PORT
      LAYER M4 ;
        RECT  17.088 7.344 17.28 7.368 ;
    END
  END i[49]
  PIN i[4]
    DIRECTION INPUT ;
    USE SIGNAL ;
    PORT
      LAYER M4 ;
        RECT  17.088 2.64 17.28 2.664 ;
    END
  END i[4]
  PIN i[500]
    DIRECTION INPUT ;
    USE SIGNAL ;
    PORT
      LAYER M4 ;
        RECT  17.088 54.48 17.28 54.504 ;
    END
  END i[500]
  PIN i[501]
    DIRECTION INPUT ;
    USE SIGNAL ;
    PORT
      LAYER M4 ;
        RECT  17.088 54.576 17.28 54.6 ;
    END
  END i[501]
  PIN i[502]
    DIRECTION INPUT ;
    USE SIGNAL ;
    PORT
      LAYER M4 ;
        RECT  17.088 54.672 17.28 54.696 ;
    END
  END i[502]
  PIN i[503]
    DIRECTION INPUT ;
    USE SIGNAL ;
    PORT
      LAYER M4 ;
        RECT  17.088 54.816 17.28 54.84 ;
    END
  END i[503]
  PIN i[504]
    DIRECTION INPUT ;
    USE SIGNAL ;
    PORT
      LAYER M4 ;
        RECT  17.088 54.912 17.28 54.936 ;
    END
  END i[504]
  PIN i[505]
    DIRECTION INPUT ;
    USE SIGNAL ;
    PORT
      LAYER M4 ;
        RECT  17.088 55.008 17.28 55.032 ;
    END
  END i[505]
  PIN i[506]
    DIRECTION INPUT ;
    USE SIGNAL ;
    PORT
      LAYER M4 ;
        RECT  17.088 55.104 17.28 55.128 ;
    END
  END i[506]
  PIN i[507]
    DIRECTION INPUT ;
    USE SIGNAL ;
    PORT
      LAYER M4 ;
        RECT  17.088 55.2 17.28 55.224 ;
    END
  END i[507]
  PIN i[508]
    DIRECTION INPUT ;
    USE SIGNAL ;
    PORT
      LAYER M4 ;
        RECT  17.088 55.296 17.28 55.32 ;
    END
  END i[508]
  PIN i[509]
    DIRECTION INPUT ;
    USE SIGNAL ;
    PORT
      LAYER M4 ;
        RECT  17.088 55.44 17.28 55.464 ;
    END
  END i[509]
  PIN i[50]
    DIRECTION INPUT ;
    USE SIGNAL ;
    PORT
      LAYER M4 ;
        RECT  17.088 7.44 17.28 7.464 ;
    END
  END i[50]
  PIN i[510]
    DIRECTION INPUT ;
    USE SIGNAL ;
    PORT
      LAYER M4 ;
        RECT  17.088 55.536 17.28 55.56 ;
    END
  END i[510]
  PIN i[511]
    DIRECTION INPUT ;
    USE SIGNAL ;
    PORT
      LAYER M4 ;
        RECT  17.088 55.632 17.28 55.656 ;
    END
  END i[511]
  PIN i[512]
    DIRECTION INPUT ;
    USE SIGNAL ;
    PORT
      LAYER M4 ;
        RECT  17.088 55.728 17.28 55.752 ;
    END
  END i[512]
  PIN i[513]
    DIRECTION INPUT ;
    USE SIGNAL ;
    PORT
      LAYER M4 ;
        RECT  17.088 55.824 17.28 55.848 ;
    END
  END i[513]
  PIN i[514]
    DIRECTION INPUT ;
    USE SIGNAL ;
    PORT
      LAYER M4 ;
        RECT  17.088 55.968 17.28 55.992 ;
    END
  END i[514]
  PIN i[515]
    DIRECTION INPUT ;
    USE SIGNAL ;
    PORT
      LAYER M4 ;
        RECT  17.088 56.064 17.28 56.088 ;
    END
  END i[515]
  PIN i[516]
    DIRECTION INPUT ;
    USE SIGNAL ;
    PORT
      LAYER M4 ;
        RECT  17.088 56.16 17.28 56.184 ;
    END
  END i[516]
  PIN i[517]
    DIRECTION INPUT ;
    USE SIGNAL ;
    PORT
      LAYER M4 ;
        RECT  17.088 56.256 17.28 56.28 ;
    END
  END i[517]
  PIN i[518]
    DIRECTION INPUT ;
    USE SIGNAL ;
    PORT
      LAYER M4 ;
        RECT  17.088 56.352 17.28 56.376 ;
    END
  END i[518]
  PIN i[519]
    DIRECTION INPUT ;
    USE SIGNAL ;
    PORT
      LAYER M4 ;
        RECT  17.088 56.448 17.28 56.472 ;
    END
  END i[519]
  PIN i[51]
    DIRECTION INPUT ;
    USE SIGNAL ;
    PORT
      LAYER M4 ;
        RECT  17.088 7.536 17.28 7.56 ;
    END
  END i[51]
  PIN i[520]
    DIRECTION INPUT ;
    USE SIGNAL ;
    PORT
      LAYER M4 ;
        RECT  17.088 56.592 17.28 56.616 ;
    END
  END i[520]
  PIN i[521]
    DIRECTION INPUT ;
    USE SIGNAL ;
    PORT
      LAYER M4 ;
        RECT  17.088 56.688 17.28 56.712 ;
    END
  END i[521]
  PIN i[522]
    DIRECTION INPUT ;
    USE SIGNAL ;
    PORT
      LAYER M4 ;
        RECT  17.088 56.784 17.28 56.808 ;
    END
  END i[522]
  PIN i[523]
    DIRECTION INPUT ;
    USE SIGNAL ;
    PORT
      LAYER M4 ;
        RECT  17.088 56.88 17.28 56.904 ;
    END
  END i[523]
  PIN i[524]
    DIRECTION INPUT ;
    USE SIGNAL ;
    PORT
      LAYER M4 ;
        RECT  17.088 56.976 17.28 57 ;
    END
  END i[524]
  PIN i[525]
    DIRECTION INPUT ;
    USE SIGNAL ;
    PORT
      LAYER M4 ;
        RECT  17.088 57.072 17.28 57.096 ;
    END
  END i[525]
  PIN i[526]
    DIRECTION INPUT ;
    USE SIGNAL ;
    PORT
      LAYER M4 ;
        RECT  17.088 57.216 17.28 57.24 ;
    END
  END i[526]
  PIN i[527]
    DIRECTION INPUT ;
    USE SIGNAL ;
    PORT
      LAYER M4 ;
        RECT  17.088 57.312 17.28 57.336 ;
    END
  END i[527]
  PIN i[528]
    DIRECTION INPUT ;
    USE SIGNAL ;
    PORT
      LAYER M4 ;
        RECT  17.088 57.408 17.28 57.432 ;
    END
  END i[528]
  PIN i[529]
    DIRECTION INPUT ;
    USE SIGNAL ;
    PORT
      LAYER M4 ;
        RECT  17.088 57.504 17.28 57.528 ;
    END
  END i[529]
  PIN i[52]
    DIRECTION INPUT ;
    USE SIGNAL ;
    PORT
      LAYER M4 ;
        RECT  17.088 7.68 17.28 7.704 ;
    END
  END i[52]
  PIN i[530]
    DIRECTION INPUT ;
    USE SIGNAL ;
    PORT
      LAYER M4 ;
        RECT  17.088 57.6 17.28 57.624 ;
    END
  END i[530]
  PIN i[531]
    DIRECTION INPUT ;
    USE SIGNAL ;
    PORT
      LAYER M4 ;
        RECT  17.088 57.744 17.28 57.768 ;
    END
  END i[531]
  PIN i[532]
    DIRECTION INPUT ;
    USE SIGNAL ;
    PORT
      LAYER M4 ;
        RECT  17.088 57.84 17.28 57.864 ;
    END
  END i[532]
  PIN i[533]
    DIRECTION INPUT ;
    USE SIGNAL ;
    PORT
      LAYER M4 ;
        RECT  17.088 57.936 17.28 57.96 ;
    END
  END i[533]
  PIN i[534]
    DIRECTION INPUT ;
    USE SIGNAL ;
    PORT
      LAYER M4 ;
        RECT  17.088 58.032 17.28 58.056 ;
    END
  END i[534]
  PIN i[535]
    DIRECTION INPUT ;
    USE SIGNAL ;
    PORT
      LAYER M4 ;
        RECT  17.088 58.128 17.28 58.152 ;
    END
  END i[535]
  PIN i[536]
    DIRECTION INPUT ;
    USE SIGNAL ;
    PORT
      LAYER M4 ;
        RECT  17.088 58.224 17.28 58.248 ;
    END
  END i[536]
  PIN i[537]
    DIRECTION INPUT ;
    USE SIGNAL ;
    PORT
      LAYER M4 ;
        RECT  17.088 58.368 17.28 58.392 ;
    END
  END i[537]
  PIN i[538]
    DIRECTION INPUT ;
    USE SIGNAL ;
    PORT
      LAYER M4 ;
        RECT  17.088 58.464 17.28 58.488 ;
    END
  END i[538]
  PIN i[539]
    DIRECTION INPUT ;
    USE SIGNAL ;
    PORT
      LAYER M4 ;
        RECT  17.088 58.56 17.28 58.584 ;
    END
  END i[539]
  PIN i[53]
    DIRECTION INPUT ;
    USE SIGNAL ;
    PORT
      LAYER M4 ;
        RECT  17.088 7.776 17.28 7.8 ;
    END
  END i[53]
  PIN i[540]
    DIRECTION INPUT ;
    USE SIGNAL ;
    PORT
      LAYER M4 ;
        RECT  17.088 58.656 17.28 58.68 ;
    END
  END i[540]
  PIN i[541]
    DIRECTION INPUT ;
    USE SIGNAL ;
    PORT
      LAYER M4 ;
        RECT  17.088 58.752 17.28 58.776 ;
    END
  END i[541]
  PIN i[542]
    DIRECTION INPUT ;
    USE SIGNAL ;
    PORT
      LAYER M4 ;
        RECT  17.088 58.896 17.28 58.92 ;
    END
  END i[542]
  PIN i[543]
    DIRECTION INPUT ;
    USE SIGNAL ;
    PORT
      LAYER M4 ;
        RECT  17.088 58.992 17.28 59.016 ;
    END
  END i[543]
  PIN i[544]
    DIRECTION INPUT ;
    USE SIGNAL ;
    PORT
      LAYER M4 ;
        RECT  17.088 59.088 17.28 59.112 ;
    END
  END i[544]
  PIN i[545]
    DIRECTION INPUT ;
    USE SIGNAL ;
    PORT
      LAYER M4 ;
        RECT  17.088 59.184 17.28 59.208 ;
    END
  END i[545]
  PIN i[546]
    DIRECTION INPUT ;
    USE SIGNAL ;
    PORT
      LAYER M4 ;
        RECT  17.088 59.28 17.28 59.304 ;
    END
  END i[546]
  PIN i[547]
    DIRECTION INPUT ;
    USE SIGNAL ;
    PORT
      LAYER M4 ;
        RECT  17.088 59.376 17.28 59.4 ;
    END
  END i[547]
  PIN i[548]
    DIRECTION INPUT ;
    USE SIGNAL ;
    PORT
      LAYER M4 ;
        RECT  17.088 59.52 17.28 59.544 ;
    END
  END i[548]
  PIN i[549]
    DIRECTION INPUT ;
    USE SIGNAL ;
    PORT
      LAYER M4 ;
        RECT  17.088 59.616 17.28 59.64 ;
    END
  END i[549]
  PIN i[54]
    DIRECTION INPUT ;
    USE SIGNAL ;
    PORT
      LAYER M4 ;
        RECT  17.088 7.872 17.28 7.896 ;
    END
  END i[54]
  PIN i[550]
    DIRECTION INPUT ;
    USE SIGNAL ;
    PORT
      LAYER M4 ;
        RECT  17.088 59.712 17.28 59.736 ;
    END
  END i[550]
  PIN i[551]
    DIRECTION INPUT ;
    USE SIGNAL ;
    PORT
      LAYER M4 ;
        RECT  17.088 59.808 17.28 59.832 ;
    END
  END i[551]
  PIN i[552]
    DIRECTION INPUT ;
    USE SIGNAL ;
    PORT
      LAYER M4 ;
        RECT  17.088 59.904 17.28 59.928 ;
    END
  END i[552]
  PIN i[553]
    DIRECTION INPUT ;
    USE SIGNAL ;
    PORT
      LAYER M4 ;
        RECT  17.088 60 17.28 60.024 ;
    END
  END i[553]
  PIN i[554]
    DIRECTION INPUT ;
    USE SIGNAL ;
    PORT
      LAYER M4 ;
        RECT  17.088 60.144 17.28 60.168 ;
    END
  END i[554]
  PIN i[555]
    DIRECTION INPUT ;
    USE SIGNAL ;
    PORT
      LAYER M4 ;
        RECT  17.088 60.24 17.28 60.264 ;
    END
  END i[555]
  PIN i[556]
    DIRECTION INPUT ;
    USE SIGNAL ;
    PORT
      LAYER M4 ;
        RECT  17.088 60.336 17.28 60.36 ;
    END
  END i[556]
  PIN i[557]
    DIRECTION INPUT ;
    USE SIGNAL ;
    PORT
      LAYER M4 ;
        RECT  17.088 60.432 17.28 60.456 ;
    END
  END i[557]
  PIN i[558]
    DIRECTION INPUT ;
    USE SIGNAL ;
    PORT
      LAYER M4 ;
        RECT  17.088 60.528 17.28 60.552 ;
    END
  END i[558]
  PIN i[559]
    DIRECTION INPUT ;
    USE SIGNAL ;
    PORT
      LAYER M4 ;
        RECT  17.088 60.672 17.28 60.696 ;
    END
  END i[559]
  PIN i[55]
    DIRECTION INPUT ;
    USE SIGNAL ;
    PORT
      LAYER M4 ;
        RECT  17.088 7.968 17.28 7.992 ;
    END
  END i[55]
  PIN i[560]
    DIRECTION INPUT ;
    USE SIGNAL ;
    PORT
      LAYER M4 ;
        RECT  17.088 60.768 17.28 60.792 ;
    END
  END i[560]
  PIN i[561]
    DIRECTION INPUT ;
    USE SIGNAL ;
    PORT
      LAYER M4 ;
        RECT  17.088 60.864 17.28 60.888 ;
    END
  END i[561]
  PIN i[562]
    DIRECTION INPUT ;
    USE SIGNAL ;
    PORT
      LAYER M4 ;
        RECT  17.088 60.96 17.28 60.984 ;
    END
  END i[562]
  PIN i[563]
    DIRECTION INPUT ;
    USE SIGNAL ;
    PORT
      LAYER M4 ;
        RECT  17.088 61.056 17.28 61.08 ;
    END
  END i[563]
  PIN i[564]
    DIRECTION INPUT ;
    USE SIGNAL ;
    PORT
      LAYER M4 ;
        RECT  17.088 61.152 17.28 61.176 ;
    END
  END i[564]
  PIN i[565]
    DIRECTION INPUT ;
    USE SIGNAL ;
    PORT
      LAYER M4 ;
        RECT  17.088 61.296 17.28 61.32 ;
    END
  END i[565]
  PIN i[566]
    DIRECTION INPUT ;
    USE SIGNAL ;
    PORT
      LAYER M4 ;
        RECT  17.088 61.392 17.28 61.416 ;
    END
  END i[566]
  PIN i[567]
    DIRECTION INPUT ;
    USE SIGNAL ;
    PORT
      LAYER M4 ;
        RECT  17.088 61.488 17.28 61.512 ;
    END
  END i[567]
  PIN i[568]
    DIRECTION INPUT ;
    USE SIGNAL ;
    PORT
      LAYER M4 ;
        RECT  17.088 61.584 17.28 61.608 ;
    END
  END i[568]
  PIN i[569]
    DIRECTION INPUT ;
    USE SIGNAL ;
    PORT
      LAYER M4 ;
        RECT  17.088 61.68 17.28 61.704 ;
    END
  END i[569]
  PIN i[56]
    DIRECTION INPUT ;
    USE SIGNAL ;
    PORT
      LAYER M4 ;
        RECT  17.088 8.064 17.28 8.088 ;
    END
  END i[56]
  PIN i[570]
    DIRECTION INPUT ;
    USE SIGNAL ;
    PORT
      LAYER M4 ;
        RECT  17.088 61.776 17.28 61.8 ;
    END
  END i[570]
  PIN i[571]
    DIRECTION INPUT ;
    USE SIGNAL ;
    PORT
      LAYER M4 ;
        RECT  17.088 61.92 17.28 61.944 ;
    END
  END i[571]
  PIN i[572]
    DIRECTION INPUT ;
    USE SIGNAL ;
    PORT
      LAYER M4 ;
        RECT  17.088 62.016 17.28 62.04 ;
    END
  END i[572]
  PIN i[573]
    DIRECTION INPUT ;
    USE SIGNAL ;
    PORT
      LAYER M4 ;
        RECT  17.088 62.112 17.28 62.136 ;
    END
  END i[573]
  PIN i[574]
    DIRECTION INPUT ;
    USE SIGNAL ;
    PORT
      LAYER M4 ;
        RECT  17.088 62.208 17.28 62.232 ;
    END
  END i[574]
  PIN i[575]
    DIRECTION INPUT ;
    USE SIGNAL ;
    PORT
      LAYER M4 ;
        RECT  17.088 62.304 17.28 62.328 ;
    END
  END i[575]
  PIN i[576]
    DIRECTION INPUT ;
    USE SIGNAL ;
    PORT
      LAYER M4 ;
        RECT  17.088 62.448 17.28 62.472 ;
    END
  END i[576]
  PIN i[577]
    DIRECTION INPUT ;
    USE SIGNAL ;
    PORT
      LAYER M4 ;
        RECT  17.088 62.544 17.28 62.568 ;
    END
  END i[577]
  PIN i[578]
    DIRECTION INPUT ;
    USE SIGNAL ;
    PORT
      LAYER M4 ;
        RECT  17.088 62.64 17.28 62.664 ;
    END
  END i[578]
  PIN i[579]
    DIRECTION INPUT ;
    USE SIGNAL ;
    PORT
      LAYER M4 ;
        RECT  17.088 62.736 17.28 62.76 ;
    END
  END i[579]
  PIN i[57]
    DIRECTION INPUT ;
    USE SIGNAL ;
    PORT
      LAYER M4 ;
        RECT  17.088 8.16 17.28 8.184 ;
    END
  END i[57]
  PIN i[580]
    DIRECTION INPUT ;
    USE SIGNAL ;
    PORT
      LAYER M4 ;
        RECT  17.088 62.832 17.28 62.856 ;
    END
  END i[580]
  PIN i[581]
    DIRECTION INPUT ;
    USE SIGNAL ;
    PORT
      LAYER M4 ;
        RECT  17.088 62.928 17.28 62.952 ;
    END
  END i[581]
  PIN i[582]
    DIRECTION INPUT ;
    USE SIGNAL ;
    PORT
      LAYER M4 ;
        RECT  17.088 63.072 17.28 63.096 ;
    END
  END i[582]
  PIN i[583]
    DIRECTION INPUT ;
    USE SIGNAL ;
    PORT
      LAYER M4 ;
        RECT  17.088 63.168 17.28 63.192 ;
    END
  END i[583]
  PIN i[584]
    DIRECTION INPUT ;
    USE SIGNAL ;
    PORT
      LAYER M4 ;
        RECT  17.088 63.264 17.28 63.288 ;
    END
  END i[584]
  PIN i[585]
    DIRECTION INPUT ;
    USE SIGNAL ;
    PORT
      LAYER M4 ;
        RECT  17.088 63.36 17.28 63.384 ;
    END
  END i[585]
  PIN i[586]
    DIRECTION INPUT ;
    USE SIGNAL ;
    PORT
      LAYER M4 ;
        RECT  17.088 63.456 17.28 63.48 ;
    END
  END i[586]
  PIN i[587]
    DIRECTION INPUT ;
    USE SIGNAL ;
    PORT
      LAYER M4 ;
        RECT  17.088 63.552 17.28 63.576 ;
    END
  END i[587]
  PIN i[588]
    DIRECTION INPUT ;
    USE SIGNAL ;
    PORT
      LAYER M4 ;
        RECT  17.088 63.696 17.28 63.72 ;
    END
  END i[588]
  PIN i[589]
    DIRECTION INPUT ;
    USE SIGNAL ;
    PORT
      LAYER M4 ;
        RECT  17.088 63.792 17.28 63.816 ;
    END
  END i[589]
  PIN i[58]
    DIRECTION INPUT ;
    USE SIGNAL ;
    PORT
      LAYER M4 ;
        RECT  17.088 8.304 17.28 8.328 ;
    END
  END i[58]
  PIN i[590]
    DIRECTION INPUT ;
    USE SIGNAL ;
    PORT
      LAYER M4 ;
        RECT  17.088 63.888 17.28 63.912 ;
    END
  END i[590]
  PIN i[591]
    DIRECTION INPUT ;
    USE SIGNAL ;
    PORT
      LAYER M4 ;
        RECT  17.088 63.984 17.28 64.008 ;
    END
  END i[591]
  PIN i[592]
    DIRECTION INPUT ;
    USE SIGNAL ;
    PORT
      LAYER M4 ;
        RECT  17.088 64.08 17.28 64.104 ;
    END
  END i[592]
  PIN i[593]
    DIRECTION INPUT ;
    USE SIGNAL ;
    PORT
      LAYER M4 ;
        RECT  17.088 64.224 17.28 64.248 ;
    END
  END i[593]
  PIN i[594]
    DIRECTION INPUT ;
    USE SIGNAL ;
    PORT
      LAYER M4 ;
        RECT  17.088 64.32 17.28 64.344 ;
    END
  END i[594]
  PIN i[595]
    DIRECTION INPUT ;
    USE SIGNAL ;
    PORT
      LAYER M4 ;
        RECT  17.088 64.416 17.28 64.44 ;
    END
  END i[595]
  PIN i[596]
    DIRECTION INPUT ;
    USE SIGNAL ;
    PORT
      LAYER M4 ;
        RECT  17.088 64.512 17.28 64.536 ;
    END
  END i[596]
  PIN i[597]
    DIRECTION INPUT ;
    USE SIGNAL ;
    PORT
      LAYER M4 ;
        RECT  17.088 64.608 17.28 64.632 ;
    END
  END i[597]
  PIN i[598]
    DIRECTION INPUT ;
    USE SIGNAL ;
    PORT
      LAYER M4 ;
        RECT  17.088 64.704 17.28 64.728 ;
    END
  END i[598]
  PIN i[599]
    DIRECTION INPUT ;
    USE SIGNAL ;
    PORT
      LAYER M4 ;
        RECT  17.088 64.848 17.28 64.872 ;
    END
  END i[599]
  PIN i[59]
    DIRECTION INPUT ;
    USE SIGNAL ;
    PORT
      LAYER M4 ;
        RECT  17.088 8.4 17.28 8.424 ;
    END
  END i[59]
  PIN i[5]
    DIRECTION INPUT ;
    USE SIGNAL ;
    PORT
      LAYER M4 ;
        RECT  17.088 2.736 17.28 2.76 ;
    END
  END i[5]
  PIN i[600]
    DIRECTION INPUT ;
    USE SIGNAL ;
    PORT
      LAYER M4 ;
        RECT  17.088 64.944 17.28 64.968 ;
    END
  END i[600]
  PIN i[601]
    DIRECTION INPUT ;
    USE SIGNAL ;
    PORT
      LAYER M4 ;
        RECT  17.088 65.04 17.28 65.064 ;
    END
  END i[601]
  PIN i[602]
    DIRECTION INPUT ;
    USE SIGNAL ;
    PORT
      LAYER M4 ;
        RECT  17.088 65.136 17.28 65.16 ;
    END
  END i[602]
  PIN i[603]
    DIRECTION INPUT ;
    USE SIGNAL ;
    PORT
      LAYER M4 ;
        RECT  17.088 65.232 17.28 65.256 ;
    END
  END i[603]
  PIN i[604]
    DIRECTION INPUT ;
    USE SIGNAL ;
    PORT
      LAYER M4 ;
        RECT  17.088 65.328 17.28 65.352 ;
    END
  END i[604]
  PIN i[605]
    DIRECTION INPUT ;
    USE SIGNAL ;
    PORT
      LAYER M4 ;
        RECT  17.088 65.472 17.28 65.496 ;
    END
  END i[605]
  PIN i[606]
    DIRECTION INPUT ;
    USE SIGNAL ;
    PORT
      LAYER M4 ;
        RECT  17.088 65.568 17.28 65.592 ;
    END
  END i[606]
  PIN i[607]
    DIRECTION INPUT ;
    USE SIGNAL ;
    PORT
      LAYER M4 ;
        RECT  17.088 65.664 17.28 65.688 ;
    END
  END i[607]
  PIN i[608]
    DIRECTION INPUT ;
    USE SIGNAL ;
    PORT
      LAYER M4 ;
        RECT  17.088 65.76 17.28 65.784 ;
    END
  END i[608]
  PIN i[609]
    DIRECTION INPUT ;
    USE SIGNAL ;
    PORT
      LAYER M4 ;
        RECT  17.088 65.856 17.28 65.88 ;
    END
  END i[609]
  PIN i[60]
    DIRECTION INPUT ;
    USE SIGNAL ;
    PORT
      LAYER M4 ;
        RECT  17.088 8.496 17.28 8.52 ;
    END
  END i[60]
  PIN i[610]
    DIRECTION INPUT ;
    USE SIGNAL ;
    PORT
      LAYER M4 ;
        RECT  17.088 66 17.28 66.024 ;
    END
  END i[610]
  PIN i[611]
    DIRECTION INPUT ;
    USE SIGNAL ;
    PORT
      LAYER M4 ;
        RECT  17.088 66.096 17.28 66.12 ;
    END
  END i[611]
  PIN i[612]
    DIRECTION INPUT ;
    USE SIGNAL ;
    PORT
      LAYER M4 ;
        RECT  17.088 66.192 17.28 66.216 ;
    END
  END i[612]
  PIN i[613]
    DIRECTION INPUT ;
    USE SIGNAL ;
    PORT
      LAYER M4 ;
        RECT  17.088 66.288 17.28 66.312 ;
    END
  END i[613]
  PIN i[614]
    DIRECTION INPUT ;
    USE SIGNAL ;
    PORT
      LAYER M4 ;
        RECT  17.088 66.384 17.28 66.408 ;
    END
  END i[614]
  PIN i[615]
    DIRECTION INPUT ;
    USE SIGNAL ;
    PORT
      LAYER M4 ;
        RECT  17.088 66.48 17.28 66.504 ;
    END
  END i[615]
  PIN i[616]
    DIRECTION INPUT ;
    USE SIGNAL ;
    PORT
      LAYER M4 ;
        RECT  17.088 66.624 17.28 66.648 ;
    END
  END i[616]
  PIN i[617]
    DIRECTION INPUT ;
    USE SIGNAL ;
    PORT
      LAYER M4 ;
        RECT  17.088 66.72 17.28 66.744 ;
    END
  END i[617]
  PIN i[618]
    DIRECTION INPUT ;
    USE SIGNAL ;
    PORT
      LAYER M4 ;
        RECT  17.088 66.816 17.28 66.84 ;
    END
  END i[618]
  PIN i[619]
    DIRECTION INPUT ;
    USE SIGNAL ;
    PORT
      LAYER M4 ;
        RECT  17.088 66.912 17.28 66.936 ;
    END
  END i[619]
  PIN i[61]
    DIRECTION INPUT ;
    USE SIGNAL ;
    PORT
      LAYER M4 ;
        RECT  17.088 8.592 17.28 8.616 ;
    END
  END i[61]
  PIN i[620]
    DIRECTION INPUT ;
    USE SIGNAL ;
    PORT
      LAYER M4 ;
        RECT  17.088 67.008 17.28 67.032 ;
    END
  END i[620]
  PIN i[621]
    DIRECTION INPUT ;
    USE SIGNAL ;
    PORT
      LAYER M4 ;
        RECT  17.088 67.152 17.28 67.176 ;
    END
  END i[621]
  PIN i[622]
    DIRECTION INPUT ;
    USE SIGNAL ;
    PORT
      LAYER M4 ;
        RECT  17.088 67.248 17.28 67.272 ;
    END
  END i[622]
  PIN i[623]
    DIRECTION INPUT ;
    USE SIGNAL ;
    PORT
      LAYER M4 ;
        RECT  17.088 67.344 17.28 67.368 ;
    END
  END i[623]
  PIN i[624]
    DIRECTION INPUT ;
    USE SIGNAL ;
    PORT
      LAYER M4 ;
        RECT  17.088 67.44 17.28 67.464 ;
    END
  END i[624]
  PIN i[625]
    DIRECTION INPUT ;
    USE SIGNAL ;
    PORT
      LAYER M4 ;
        RECT  17.088 67.536 17.28 67.56 ;
    END
  END i[625]
  PIN i[626]
    DIRECTION INPUT ;
    USE SIGNAL ;
    PORT
      LAYER M4 ;
        RECT  17.088 67.632 17.28 67.656 ;
    END
  END i[626]
  PIN i[627]
    DIRECTION INPUT ;
    USE SIGNAL ;
    PORT
      LAYER M4 ;
        RECT  17.088 67.776 17.28 67.8 ;
    END
  END i[627]
  PIN i[628]
    DIRECTION INPUT ;
    USE SIGNAL ;
    PORT
      LAYER M4 ;
        RECT  17.088 67.872 17.28 67.896 ;
    END
  END i[628]
  PIN i[629]
    DIRECTION INPUT ;
    USE SIGNAL ;
    PORT
      LAYER M4 ;
        RECT  17.088 67.968 17.28 67.992 ;
    END
  END i[629]
  PIN i[62]
    DIRECTION INPUT ;
    USE SIGNAL ;
    PORT
      LAYER M4 ;
        RECT  17.088 8.688 17.28 8.712 ;
    END
  END i[62]
  PIN i[630]
    DIRECTION INPUT ;
    USE SIGNAL ;
    PORT
      LAYER M4 ;
        RECT  17.088 68.064 17.28 68.088 ;
    END
  END i[630]
  PIN i[631]
    DIRECTION INPUT ;
    USE SIGNAL ;
    PORT
      LAYER M4 ;
        RECT  17.088 68.16 17.28 68.184 ;
    END
  END i[631]
  PIN i[632]
    DIRECTION INPUT ;
    USE SIGNAL ;
    PORT
      LAYER M4 ;
        RECT  17.088 68.256 17.28 68.28 ;
    END
  END i[632]
  PIN i[633]
    DIRECTION INPUT ;
    USE SIGNAL ;
    PORT
      LAYER M4 ;
        RECT  17.088 68.4 17.28 68.424 ;
    END
  END i[633]
  PIN i[634]
    DIRECTION INPUT ;
    USE SIGNAL ;
    PORT
      LAYER M4 ;
        RECT  17.088 68.496 17.28 68.52 ;
    END
  END i[634]
  PIN i[635]
    DIRECTION INPUT ;
    USE SIGNAL ;
    PORT
      LAYER M4 ;
        RECT  17.088 68.592 17.28 68.616 ;
    END
  END i[635]
  PIN i[636]
    DIRECTION INPUT ;
    USE SIGNAL ;
    PORT
      LAYER M4 ;
        RECT  17.088 68.688 17.28 68.712 ;
    END
  END i[636]
  PIN i[637]
    DIRECTION INPUT ;
    USE SIGNAL ;
    PORT
      LAYER M4 ;
        RECT  17.088 68.784 17.28 68.808 ;
    END
  END i[637]
  PIN i[638]
    DIRECTION INPUT ;
    USE SIGNAL ;
    PORT
      LAYER M4 ;
        RECT  17.088 68.928 17.28 68.952 ;
    END
  END i[638]
  PIN i[639]
    DIRECTION INPUT ;
    USE SIGNAL ;
    PORT
      LAYER M4 ;
        RECT  17.088 69.024 17.28 69.048 ;
    END
  END i[639]
  PIN i[63]
    DIRECTION INPUT ;
    USE SIGNAL ;
    PORT
      LAYER M4 ;
        RECT  17.088 8.832 17.28 8.856 ;
    END
  END i[63]
  PIN i[640]
    DIRECTION INPUT ;
    USE SIGNAL ;
    PORT
      LAYER M4 ;
        RECT  17.088 69.12 17.28 69.144 ;
    END
  END i[640]
  PIN i[641]
    DIRECTION INPUT ;
    USE SIGNAL ;
    PORT
      LAYER M4 ;
        RECT  17.088 69.216 17.28 69.24 ;
    END
  END i[641]
  PIN i[642]
    DIRECTION INPUT ;
    USE SIGNAL ;
    PORT
      LAYER M4 ;
        RECT  17.088 69.312 17.28 69.336 ;
    END
  END i[642]
  PIN i[643]
    DIRECTION INPUT ;
    USE SIGNAL ;
    PORT
      LAYER M4 ;
        RECT  17.088 69.408 17.28 69.432 ;
    END
  END i[643]
  PIN i[644]
    DIRECTION INPUT ;
    USE SIGNAL ;
    PORT
      LAYER M4 ;
        RECT  17.088 69.552 17.28 69.576 ;
    END
  END i[644]
  PIN i[645]
    DIRECTION INPUT ;
    USE SIGNAL ;
    PORT
      LAYER M4 ;
        RECT  17.088 69.648 17.28 69.672 ;
    END
  END i[645]
  PIN i[646]
    DIRECTION INPUT ;
    USE SIGNAL ;
    PORT
      LAYER M4 ;
        RECT  17.088 69.744 17.28 69.768 ;
    END
  END i[646]
  PIN i[647]
    DIRECTION INPUT ;
    USE SIGNAL ;
    PORT
      LAYER M4 ;
        RECT  17.088 69.84 17.28 69.864 ;
    END
  END i[647]
  PIN i[648]
    DIRECTION INPUT ;
    USE SIGNAL ;
    PORT
      LAYER M4 ;
        RECT  17.088 69.936 17.28 69.96 ;
    END
  END i[648]
  PIN i[649]
    DIRECTION INPUT ;
    USE SIGNAL ;
    PORT
      LAYER M4 ;
        RECT  17.088 70.032 17.28 70.056 ;
    END
  END i[649]
  PIN i[64]
    DIRECTION INPUT ;
    USE SIGNAL ;
    PORT
      LAYER M4 ;
        RECT  17.088 8.928 17.28 8.952 ;
    END
  END i[64]
  PIN i[650]
    DIRECTION INPUT ;
    USE SIGNAL ;
    PORT
      LAYER M4 ;
        RECT  17.088 70.176 17.28 70.2 ;
    END
  END i[650]
  PIN i[651]
    DIRECTION INPUT ;
    USE SIGNAL ;
    PORT
      LAYER M4 ;
        RECT  17.088 70.272 17.28 70.296 ;
    END
  END i[651]
  PIN i[652]
    DIRECTION INPUT ;
    USE SIGNAL ;
    PORT
      LAYER M4 ;
        RECT  17.088 70.368 17.28 70.392 ;
    END
  END i[652]
  PIN i[653]
    DIRECTION INPUT ;
    USE SIGNAL ;
    PORT
      LAYER M4 ;
        RECT  17.088 70.464 17.28 70.488 ;
    END
  END i[653]
  PIN i[654]
    DIRECTION INPUT ;
    USE SIGNAL ;
    PORT
      LAYER M4 ;
        RECT  17.088 70.56 17.28 70.584 ;
    END
  END i[654]
  PIN i[655]
    DIRECTION INPUT ;
    USE SIGNAL ;
    PORT
      LAYER M4 ;
        RECT  17.088 70.704 17.28 70.728 ;
    END
  END i[655]
  PIN i[656]
    DIRECTION INPUT ;
    USE SIGNAL ;
    PORT
      LAYER M4 ;
        RECT  17.088 70.8 17.28 70.824 ;
    END
  END i[656]
  PIN i[657]
    DIRECTION INPUT ;
    USE SIGNAL ;
    PORT
      LAYER M4 ;
        RECT  17.088 70.896 17.28 70.92 ;
    END
  END i[657]
  PIN i[658]
    DIRECTION INPUT ;
    USE SIGNAL ;
    PORT
      LAYER M4 ;
        RECT  17.088 70.992 17.28 71.016 ;
    END
  END i[658]
  PIN i[659]
    DIRECTION INPUT ;
    USE SIGNAL ;
    PORT
      LAYER M4 ;
        RECT  17.088 71.088 17.28 71.112 ;
    END
  END i[659]
  PIN i[65]
    DIRECTION INPUT ;
    USE SIGNAL ;
    PORT
      LAYER M4 ;
        RECT  17.088 9.024 17.28 9.048 ;
    END
  END i[65]
  PIN i[660]
    DIRECTION INPUT ;
    USE SIGNAL ;
    PORT
      LAYER M4 ;
        RECT  17.088 71.184 17.28 71.208 ;
    END
  END i[660]
  PIN i[661]
    DIRECTION INPUT ;
    USE SIGNAL ;
    PORT
      LAYER M4 ;
        RECT  17.088 71.328 17.28 71.352 ;
    END
  END i[661]
  PIN i[662]
    DIRECTION INPUT ;
    USE SIGNAL ;
    PORT
      LAYER M4 ;
        RECT  17.088 71.424 17.28 71.448 ;
    END
  END i[662]
  PIN i[663]
    DIRECTION INPUT ;
    USE SIGNAL ;
    PORT
      LAYER M4 ;
        RECT  17.088 71.52 17.28 71.544 ;
    END
  END i[663]
  PIN i[664]
    DIRECTION INPUT ;
    USE SIGNAL ;
    PORT
      LAYER M4 ;
        RECT  17.088 71.616 17.28 71.64 ;
    END
  END i[664]
  PIN i[665]
    DIRECTION INPUT ;
    USE SIGNAL ;
    PORT
      LAYER M4 ;
        RECT  17.088 71.712 17.28 71.736 ;
    END
  END i[665]
  PIN i[666]
    DIRECTION INPUT ;
    USE SIGNAL ;
    PORT
      LAYER M4 ;
        RECT  17.088 71.856 17.28 71.88 ;
    END
  END i[666]
  PIN i[667]
    DIRECTION INPUT ;
    USE SIGNAL ;
    PORT
      LAYER M4 ;
        RECT  17.088 71.952 17.28 71.976 ;
    END
  END i[667]
  PIN i[668]
    DIRECTION INPUT ;
    USE SIGNAL ;
    PORT
      LAYER M4 ;
        RECT  17.088 72.048 17.28 72.072 ;
    END
  END i[668]
  PIN i[669]
    DIRECTION INPUT ;
    USE SIGNAL ;
    PORT
      LAYER M4 ;
        RECT  17.088 72.144 17.28 72.168 ;
    END
  END i[669]
  PIN i[66]
    DIRECTION INPUT ;
    USE SIGNAL ;
    PORT
      LAYER M4 ;
        RECT  17.088 9.12 17.28 9.144 ;
    END
  END i[66]
  PIN i[670]
    DIRECTION INPUT ;
    USE SIGNAL ;
    PORT
      LAYER M4 ;
        RECT  17.088 72.24 17.28 72.264 ;
    END
  END i[670]
  PIN i[671]
    DIRECTION INPUT ;
    USE SIGNAL ;
    PORT
      LAYER M4 ;
        RECT  17.088 72.336 17.28 72.36 ;
    END
  END i[671]
  PIN i[672]
    DIRECTION INPUT ;
    USE SIGNAL ;
    PORT
      LAYER M4 ;
        RECT  17.088 72.48 17.28 72.504 ;
    END
  END i[672]
  PIN i[673]
    DIRECTION INPUT ;
    USE SIGNAL ;
    PORT
      LAYER M4 ;
        RECT  17.088 72.576 17.28 72.6 ;
    END
  END i[673]
  PIN i[674]
    DIRECTION INPUT ;
    USE SIGNAL ;
    PORT
      LAYER M4 ;
        RECT  17.088 72.672 17.28 72.696 ;
    END
  END i[674]
  PIN i[675]
    DIRECTION INPUT ;
    USE SIGNAL ;
    PORT
      LAYER M4 ;
        RECT  17.088 72.768 17.28 72.792 ;
    END
  END i[675]
  PIN i[676]
    DIRECTION INPUT ;
    USE SIGNAL ;
    PORT
      LAYER M4 ;
        RECT  17.088 72.864 17.28 72.888 ;
    END
  END i[676]
  PIN i[677]
    DIRECTION INPUT ;
    USE SIGNAL ;
    PORT
      LAYER M4 ;
        RECT  17.088 72.96 17.28 72.984 ;
    END
  END i[677]
  PIN i[678]
    DIRECTION INPUT ;
    USE SIGNAL ;
    PORT
      LAYER M4 ;
        RECT  17.088 73.104 17.28 73.128 ;
    END
  END i[678]
  PIN i[679]
    DIRECTION INPUT ;
    USE SIGNAL ;
    PORT
      LAYER M4 ;
        RECT  17.088 73.2 17.28 73.224 ;
    END
  END i[679]
  PIN i[67]
    DIRECTION INPUT ;
    USE SIGNAL ;
    PORT
      LAYER M4 ;
        RECT  17.088 9.216 17.28 9.24 ;
    END
  END i[67]
  PIN i[680]
    DIRECTION INPUT ;
    USE SIGNAL ;
    PORT
      LAYER M4 ;
        RECT  17.088 73.296 17.28 73.32 ;
    END
  END i[680]
  PIN i[681]
    DIRECTION INPUT ;
    USE SIGNAL ;
    PORT
      LAYER M4 ;
        RECT  17.088 73.392 17.28 73.416 ;
    END
  END i[681]
  PIN i[68]
    DIRECTION INPUT ;
    USE SIGNAL ;
    PORT
      LAYER M4 ;
        RECT  17.088 9.312 17.28 9.336 ;
    END
  END i[68]
  PIN i[69]
    DIRECTION INPUT ;
    USE SIGNAL ;
    PORT
      LAYER M4 ;
        RECT  17.088 9.456 17.28 9.48 ;
    END
  END i[69]
  PIN i[6]
    DIRECTION INPUT ;
    USE SIGNAL ;
    PORT
      LAYER M4 ;
        RECT  17.088 2.832 17.28 2.856 ;
    END
  END i[6]
  PIN i[70]
    DIRECTION INPUT ;
    USE SIGNAL ;
    PORT
      LAYER M4 ;
        RECT  17.088 9.552 17.28 9.576 ;
    END
  END i[70]
  PIN i[71]
    DIRECTION INPUT ;
    USE SIGNAL ;
    PORT
      LAYER M4 ;
        RECT  17.088 9.648 17.28 9.672 ;
    END
  END i[71]
  PIN i[72]
    DIRECTION INPUT ;
    USE SIGNAL ;
    PORT
      LAYER M4 ;
        RECT  17.088 9.744 17.28 9.768 ;
    END
  END i[72]
  PIN i[73]
    DIRECTION INPUT ;
    USE SIGNAL ;
    PORT
      LAYER M4 ;
        RECT  17.088 9.84 17.28 9.864 ;
    END
  END i[73]
  PIN i[74]
    DIRECTION INPUT ;
    USE SIGNAL ;
    PORT
      LAYER M4 ;
        RECT  17.088 9.936 17.28 9.96 ;
    END
  END i[74]
  PIN i[75]
    DIRECTION INPUT ;
    USE SIGNAL ;
    PORT
      LAYER M4 ;
        RECT  17.088 10.08 17.28 10.104 ;
    END
  END i[75]
  PIN i[76]
    DIRECTION INPUT ;
    USE SIGNAL ;
    PORT
      LAYER M4 ;
        RECT  17.088 10.176 17.28 10.2 ;
    END
  END i[76]
  PIN i[77]
    DIRECTION INPUT ;
    USE SIGNAL ;
    PORT
      LAYER M4 ;
        RECT  17.088 10.272 17.28 10.296 ;
    END
  END i[77]
  PIN i[78]
    DIRECTION INPUT ;
    USE SIGNAL ;
    PORT
      LAYER M4 ;
        RECT  17.088 10.368 17.28 10.392 ;
    END
  END i[78]
  PIN i[79]
    DIRECTION INPUT ;
    USE SIGNAL ;
    PORT
      LAYER M4 ;
        RECT  17.088 10.464 17.28 10.488 ;
    END
  END i[79]
  PIN i[7]
    DIRECTION INPUT ;
    USE SIGNAL ;
    PORT
      LAYER M4 ;
        RECT  17.088 2.976 17.28 3 ;
    END
  END i[7]
  PIN i[80]
    DIRECTION INPUT ;
    USE SIGNAL ;
    PORT
      LAYER M4 ;
        RECT  17.088 10.608 17.28 10.632 ;
    END
  END i[80]
  PIN i[81]
    DIRECTION INPUT ;
    USE SIGNAL ;
    PORT
      LAYER M4 ;
        RECT  17.088 10.704 17.28 10.728 ;
    END
  END i[81]
  PIN i[82]
    DIRECTION INPUT ;
    USE SIGNAL ;
    PORT
      LAYER M4 ;
        RECT  17.088 10.8 17.28 10.824 ;
    END
  END i[82]
  PIN i[83]
    DIRECTION INPUT ;
    USE SIGNAL ;
    PORT
      LAYER M4 ;
        RECT  17.088 10.896 17.28 10.92 ;
    END
  END i[83]
  PIN i[84]
    DIRECTION INPUT ;
    USE SIGNAL ;
    PORT
      LAYER M4 ;
        RECT  17.088 10.992 17.28 11.016 ;
    END
  END i[84]
  PIN i[85]
    DIRECTION INPUT ;
    USE SIGNAL ;
    PORT
      LAYER M4 ;
        RECT  17.088 11.088 17.28 11.112 ;
    END
  END i[85]
  PIN i[86]
    DIRECTION INPUT ;
    USE SIGNAL ;
    PORT
      LAYER M4 ;
        RECT  17.088 11.232 17.28 11.256 ;
    END
  END i[86]
  PIN i[87]
    DIRECTION INPUT ;
    USE SIGNAL ;
    PORT
      LAYER M4 ;
        RECT  17.088 11.328 17.28 11.352 ;
    END
  END i[87]
  PIN i[88]
    DIRECTION INPUT ;
    USE SIGNAL ;
    PORT
      LAYER M4 ;
        RECT  17.088 11.424 17.28 11.448 ;
    END
  END i[88]
  PIN i[89]
    DIRECTION INPUT ;
    USE SIGNAL ;
    PORT
      LAYER M4 ;
        RECT  17.088 11.52 17.28 11.544 ;
    END
  END i[89]
  PIN i[8]
    DIRECTION INPUT ;
    USE SIGNAL ;
    PORT
      LAYER M4 ;
        RECT  17.088 3.072 17.28 3.096 ;
    END
  END i[8]
  PIN i[90]
    DIRECTION INPUT ;
    USE SIGNAL ;
    PORT
      LAYER M4 ;
        RECT  17.088 11.616 17.28 11.64 ;
    END
  END i[90]
  PIN i[91]
    DIRECTION INPUT ;
    USE SIGNAL ;
    PORT
      LAYER M4 ;
        RECT  17.088 11.712 17.28 11.736 ;
    END
  END i[91]
  PIN i[92]
    DIRECTION INPUT ;
    USE SIGNAL ;
    PORT
      LAYER M4 ;
        RECT  17.088 11.856 17.28 11.88 ;
    END
  END i[92]
  PIN i[93]
    DIRECTION INPUT ;
    USE SIGNAL ;
    PORT
      LAYER M4 ;
        RECT  17.088 11.952 17.28 11.976 ;
    END
  END i[93]
  PIN i[94]
    DIRECTION INPUT ;
    USE SIGNAL ;
    PORT
      LAYER M4 ;
        RECT  17.088 12.048 17.28 12.072 ;
    END
  END i[94]
  PIN i[95]
    DIRECTION INPUT ;
    USE SIGNAL ;
    PORT
      LAYER M4 ;
        RECT  17.088 12.144 17.28 12.168 ;
    END
  END i[95]
  PIN i[96]
    DIRECTION INPUT ;
    USE SIGNAL ;
    PORT
      LAYER M4 ;
        RECT  17.088 12.24 17.28 12.264 ;
    END
  END i[96]
  PIN i[97]
    DIRECTION INPUT ;
    USE SIGNAL ;
    PORT
      LAYER M4 ;
        RECT  17.088 12.384 17.28 12.408 ;
    END
  END i[97]
  PIN i[98]
    DIRECTION INPUT ;
    USE SIGNAL ;
    PORT
      LAYER M4 ;
        RECT  17.088 12.48 17.28 12.504 ;
    END
  END i[98]
  PIN i[99]
    DIRECTION INPUT ;
    USE SIGNAL ;
    PORT
      LAYER M4 ;
        RECT  17.088 12.576 17.28 12.6 ;
    END
  END i[99]
  PIN i[9]
    DIRECTION INPUT ;
    USE SIGNAL ;
    PORT
      LAYER M4 ;
        RECT  17.088 3.168 17.28 3.192 ;
    END
  END i[9]
  PIN o[0]
    DIRECTION OUTPUT ;
    USE SIGNAL ;
    PORT
      LAYER M4 ;
        RECT  0 2.208 0.192 2.232 ;
    END
  END o[0]
  PIN o[100]
    DIRECTION OUTPUT ;
    USE SIGNAL ;
    PORT
      LAYER M4 ;
        RECT  0 12.672 0.192 12.696 ;
    END
  END o[100]
  PIN o[101]
    DIRECTION OUTPUT ;
    USE SIGNAL ;
    PORT
      LAYER M4 ;
        RECT  0 12.768 0.192 12.792 ;
    END
  END o[101]
  PIN o[102]
    DIRECTION OUTPUT ;
    USE SIGNAL ;
    PORT
      LAYER M4 ;
        RECT  0 12.864 0.192 12.888 ;
    END
  END o[102]
  PIN o[103]
    DIRECTION OUTPUT ;
    USE SIGNAL ;
    PORT
      LAYER M4 ;
        RECT  0 12.96 0.192 12.984 ;
    END
  END o[103]
  PIN o[104]
    DIRECTION OUTPUT ;
    USE SIGNAL ;
    PORT
      LAYER M4 ;
        RECT  0 13.056 0.192 13.08 ;
    END
  END o[104]
  PIN o[105]
    DIRECTION OUTPUT ;
    USE SIGNAL ;
    PORT
      LAYER M4 ;
        RECT  0 13.2 0.192 13.224 ;
    END
  END o[105]
  PIN o[106]
    DIRECTION OUTPUT ;
    USE SIGNAL ;
    PORT
      LAYER M4 ;
        RECT  0 13.296 0.192 13.32 ;
    END
  END o[106]
  PIN o[107]
    DIRECTION OUTPUT ;
    USE SIGNAL ;
    PORT
      LAYER M4 ;
        RECT  0 13.392 0.192 13.416 ;
    END
  END o[107]
  PIN o[108]
    DIRECTION OUTPUT ;
    USE SIGNAL ;
    PORT
      LAYER M4 ;
        RECT  0 13.488 0.192 13.512 ;
    END
  END o[108]
  PIN o[109]
    DIRECTION OUTPUT ;
    USE SIGNAL ;
    PORT
      LAYER M4 ;
        RECT  0 13.584 0.192 13.608 ;
    END
  END o[109]
  PIN o[10]
    DIRECTION OUTPUT ;
    USE SIGNAL ;
    PORT
      LAYER M4 ;
        RECT  0 3.264 0.192 3.288 ;
    END
  END o[10]
  PIN o[110]
    DIRECTION OUTPUT ;
    USE SIGNAL ;
    PORT
      LAYER M4 ;
        RECT  0 13.728 0.192 13.752 ;
    END
  END o[110]
  PIN o[111]
    DIRECTION OUTPUT ;
    USE SIGNAL ;
    PORT
      LAYER M4 ;
        RECT  0 13.824 0.192 13.848 ;
    END
  END o[111]
  PIN o[112]
    DIRECTION OUTPUT ;
    USE SIGNAL ;
    PORT
      LAYER M4 ;
        RECT  0 13.92 0.192 13.944 ;
    END
  END o[112]
  PIN o[113]
    DIRECTION OUTPUT ;
    USE SIGNAL ;
    PORT
      LAYER M4 ;
        RECT  0 14.016 0.192 14.04 ;
    END
  END o[113]
  PIN o[114]
    DIRECTION OUTPUT ;
    USE SIGNAL ;
    PORT
      LAYER M4 ;
        RECT  0 14.112 0.192 14.136 ;
    END
  END o[114]
  PIN o[115]
    DIRECTION OUTPUT ;
    USE SIGNAL ;
    PORT
      LAYER M4 ;
        RECT  0 14.208 0.192 14.232 ;
    END
  END o[115]
  PIN o[116]
    DIRECTION OUTPUT ;
    USE SIGNAL ;
    PORT
      LAYER M4 ;
        RECT  0 14.352 0.192 14.376 ;
    END
  END o[116]
  PIN o[117]
    DIRECTION OUTPUT ;
    USE SIGNAL ;
    PORT
      LAYER M4 ;
        RECT  0 14.448 0.192 14.472 ;
    END
  END o[117]
  PIN o[118]
    DIRECTION OUTPUT ;
    USE SIGNAL ;
    PORT
      LAYER M4 ;
        RECT  0 14.544 0.192 14.568 ;
    END
  END o[118]
  PIN o[119]
    DIRECTION OUTPUT ;
    USE SIGNAL ;
    PORT
      LAYER M4 ;
        RECT  0 14.64 0.192 14.664 ;
    END
  END o[119]
  PIN o[11]
    DIRECTION OUTPUT ;
    USE SIGNAL ;
    PORT
      LAYER M4 ;
        RECT  0 3.36 0.192 3.384 ;
    END
  END o[11]
  PIN o[120]
    DIRECTION OUTPUT ;
    USE SIGNAL ;
    PORT
      LAYER M4 ;
        RECT  0 14.736 0.192 14.76 ;
    END
  END o[120]
  PIN o[121]
    DIRECTION OUTPUT ;
    USE SIGNAL ;
    PORT
      LAYER M4 ;
        RECT  0 14.832 0.192 14.856 ;
    END
  END o[121]
  PIN o[122]
    DIRECTION OUTPUT ;
    USE SIGNAL ;
    PORT
      LAYER M4 ;
        RECT  0 14.976 0.192 15 ;
    END
  END o[122]
  PIN o[123]
    DIRECTION OUTPUT ;
    USE SIGNAL ;
    PORT
      LAYER M4 ;
        RECT  0 15.072 0.192 15.096 ;
    END
  END o[123]
  PIN o[124]
    DIRECTION OUTPUT ;
    USE SIGNAL ;
    PORT
      LAYER M4 ;
        RECT  0 15.168 0.192 15.192 ;
    END
  END o[124]
  PIN o[125]
    DIRECTION OUTPUT ;
    USE SIGNAL ;
    PORT
      LAYER M4 ;
        RECT  0 15.264 0.192 15.288 ;
    END
  END o[125]
  PIN o[126]
    DIRECTION OUTPUT ;
    USE SIGNAL ;
    PORT
      LAYER M4 ;
        RECT  0 15.36 0.192 15.384 ;
    END
  END o[126]
  PIN o[127]
    DIRECTION OUTPUT ;
    USE SIGNAL ;
    PORT
      LAYER M4 ;
        RECT  0 15.456 0.192 15.48 ;
    END
  END o[127]
  PIN o[128]
    DIRECTION OUTPUT ;
    USE SIGNAL ;
    PORT
      LAYER M4 ;
        RECT  0 15.6 0.192 15.624 ;
    END
  END o[128]
  PIN o[129]
    DIRECTION OUTPUT ;
    USE SIGNAL ;
    PORT
      LAYER M4 ;
        RECT  0 15.696 0.192 15.72 ;
    END
  END o[129]
  PIN o[12]
    DIRECTION OUTPUT ;
    USE SIGNAL ;
    PORT
      LAYER M4 ;
        RECT  0 3.456 0.192 3.48 ;
    END
  END o[12]
  PIN o[130]
    DIRECTION OUTPUT ;
    USE SIGNAL ;
    PORT
      LAYER M4 ;
        RECT  0 15.792 0.192 15.816 ;
    END
  END o[130]
  PIN o[131]
    DIRECTION OUTPUT ;
    USE SIGNAL ;
    PORT
      LAYER M4 ;
        RECT  0 15.888 0.192 15.912 ;
    END
  END o[131]
  PIN o[132]
    DIRECTION OUTPUT ;
    USE SIGNAL ;
    PORT
      LAYER M4 ;
        RECT  0 15.984 0.192 16.008 ;
    END
  END o[132]
  PIN o[133]
    DIRECTION OUTPUT ;
    USE SIGNAL ;
    PORT
      LAYER M4 ;
        RECT  0 16.128 0.192 16.152 ;
    END
  END o[133]
  PIN o[134]
    DIRECTION OUTPUT ;
    USE SIGNAL ;
    PORT
      LAYER M4 ;
        RECT  0 16.224 0.192 16.248 ;
    END
  END o[134]
  PIN o[135]
    DIRECTION OUTPUT ;
    USE SIGNAL ;
    PORT
      LAYER M4 ;
        RECT  0 16.32 0.192 16.344 ;
    END
  END o[135]
  PIN o[136]
    DIRECTION OUTPUT ;
    USE SIGNAL ;
    PORT
      LAYER M4 ;
        RECT  0 16.416 0.192 16.44 ;
    END
  END o[136]
  PIN o[137]
    DIRECTION OUTPUT ;
    USE SIGNAL ;
    PORT
      LAYER M4 ;
        RECT  0 16.512 0.192 16.536 ;
    END
  END o[137]
  PIN o[138]
    DIRECTION OUTPUT ;
    USE SIGNAL ;
    PORT
      LAYER M4 ;
        RECT  0 16.608 0.192 16.632 ;
    END
  END o[138]
  PIN o[139]
    DIRECTION OUTPUT ;
    USE SIGNAL ;
    PORT
      LAYER M4 ;
        RECT  0 16.752 0.192 16.776 ;
    END
  END o[139]
  PIN o[13]
    DIRECTION OUTPUT ;
    USE SIGNAL ;
    PORT
      LAYER M4 ;
        RECT  0 3.6 0.192 3.624 ;
    END
  END o[13]
  PIN o[140]
    DIRECTION OUTPUT ;
    USE SIGNAL ;
    PORT
      LAYER M4 ;
        RECT  0 16.848 0.192 16.872 ;
    END
  END o[140]
  PIN o[141]
    DIRECTION OUTPUT ;
    USE SIGNAL ;
    PORT
      LAYER M4 ;
        RECT  0 16.944 0.192 16.968 ;
    END
  END o[141]
  PIN o[142]
    DIRECTION OUTPUT ;
    USE SIGNAL ;
    PORT
      LAYER M4 ;
        RECT  0 17.04 0.192 17.064 ;
    END
  END o[142]
  PIN o[143]
    DIRECTION OUTPUT ;
    USE SIGNAL ;
    PORT
      LAYER M4 ;
        RECT  0 17.136 0.192 17.16 ;
    END
  END o[143]
  PIN o[144]
    DIRECTION OUTPUT ;
    USE SIGNAL ;
    PORT
      LAYER M4 ;
        RECT  0 17.232 0.192 17.256 ;
    END
  END o[144]
  PIN o[145]
    DIRECTION OUTPUT ;
    USE SIGNAL ;
    PORT
      LAYER M4 ;
        RECT  0 17.376 0.192 17.4 ;
    END
  END o[145]
  PIN o[146]
    DIRECTION OUTPUT ;
    USE SIGNAL ;
    PORT
      LAYER M4 ;
        RECT  0 17.472 0.192 17.496 ;
    END
  END o[146]
  PIN o[147]
    DIRECTION OUTPUT ;
    USE SIGNAL ;
    PORT
      LAYER M4 ;
        RECT  0 17.568 0.192 17.592 ;
    END
  END o[147]
  PIN o[148]
    DIRECTION OUTPUT ;
    USE SIGNAL ;
    PORT
      LAYER M4 ;
        RECT  0 17.664 0.192 17.688 ;
    END
  END o[148]
  PIN o[149]
    DIRECTION OUTPUT ;
    USE SIGNAL ;
    PORT
      LAYER M4 ;
        RECT  0 17.76 0.192 17.784 ;
    END
  END o[149]
  PIN o[14]
    DIRECTION OUTPUT ;
    USE SIGNAL ;
    PORT
      LAYER M4 ;
        RECT  0 3.696 0.192 3.72 ;
    END
  END o[14]
  PIN o[150]
    DIRECTION OUTPUT ;
    USE SIGNAL ;
    PORT
      LAYER M4 ;
        RECT  0 17.856 0.192 17.88 ;
    END
  END o[150]
  PIN o[151]
    DIRECTION OUTPUT ;
    USE SIGNAL ;
    PORT
      LAYER M4 ;
        RECT  0 18 0.192 18.024 ;
    END
  END o[151]
  PIN o[152]
    DIRECTION OUTPUT ;
    USE SIGNAL ;
    PORT
      LAYER M4 ;
        RECT  0 18.096 0.192 18.12 ;
    END
  END o[152]
  PIN o[153]
    DIRECTION OUTPUT ;
    USE SIGNAL ;
    PORT
      LAYER M4 ;
        RECT  0 18.192 0.192 18.216 ;
    END
  END o[153]
  PIN o[154]
    DIRECTION OUTPUT ;
    USE SIGNAL ;
    PORT
      LAYER M4 ;
        RECT  0 18.288 0.192 18.312 ;
    END
  END o[154]
  PIN o[155]
    DIRECTION OUTPUT ;
    USE SIGNAL ;
    PORT
      LAYER M4 ;
        RECT  0 18.384 0.192 18.408 ;
    END
  END o[155]
  PIN o[156]
    DIRECTION OUTPUT ;
    USE SIGNAL ;
    PORT
      LAYER M4 ;
        RECT  0 18.528 0.192 18.552 ;
    END
  END o[156]
  PIN o[157]
    DIRECTION OUTPUT ;
    USE SIGNAL ;
    PORT
      LAYER M4 ;
        RECT  0 18.624 0.192 18.648 ;
    END
  END o[157]
  PIN o[158]
    DIRECTION OUTPUT ;
    USE SIGNAL ;
    PORT
      LAYER M4 ;
        RECT  0 18.72 0.192 18.744 ;
    END
  END o[158]
  PIN o[159]
    DIRECTION OUTPUT ;
    USE SIGNAL ;
    PORT
      LAYER M4 ;
        RECT  0 18.816 0.192 18.84 ;
    END
  END o[159]
  PIN o[15]
    DIRECTION OUTPUT ;
    USE SIGNAL ;
    PORT
      LAYER M4 ;
        RECT  0 3.792 0.192 3.816 ;
    END
  END o[15]
  PIN o[160]
    DIRECTION OUTPUT ;
    USE SIGNAL ;
    PORT
      LAYER M4 ;
        RECT  0 18.912 0.192 18.936 ;
    END
  END o[160]
  PIN o[161]
    DIRECTION OUTPUT ;
    USE SIGNAL ;
    PORT
      LAYER M4 ;
        RECT  0 19.008 0.192 19.032 ;
    END
  END o[161]
  PIN o[162]
    DIRECTION OUTPUT ;
    USE SIGNAL ;
    PORT
      LAYER M4 ;
        RECT  0 19.152 0.192 19.176 ;
    END
  END o[162]
  PIN o[163]
    DIRECTION OUTPUT ;
    USE SIGNAL ;
    PORT
      LAYER M4 ;
        RECT  0 19.248 0.192 19.272 ;
    END
  END o[163]
  PIN o[164]
    DIRECTION OUTPUT ;
    USE SIGNAL ;
    PORT
      LAYER M4 ;
        RECT  0 19.344 0.192 19.368 ;
    END
  END o[164]
  PIN o[165]
    DIRECTION OUTPUT ;
    USE SIGNAL ;
    PORT
      LAYER M4 ;
        RECT  0 19.44 0.192 19.464 ;
    END
  END o[165]
  PIN o[166]
    DIRECTION OUTPUT ;
    USE SIGNAL ;
    PORT
      LAYER M4 ;
        RECT  0 19.536 0.192 19.56 ;
    END
  END o[166]
  PIN o[167]
    DIRECTION OUTPUT ;
    USE SIGNAL ;
    PORT
      LAYER M4 ;
        RECT  0 19.632 0.192 19.656 ;
    END
  END o[167]
  PIN o[168]
    DIRECTION OUTPUT ;
    USE SIGNAL ;
    PORT
      LAYER M4 ;
        RECT  0 19.776 0.192 19.8 ;
    END
  END o[168]
  PIN o[169]
    DIRECTION OUTPUT ;
    USE SIGNAL ;
    PORT
      LAYER M4 ;
        RECT  0 19.872 0.192 19.896 ;
    END
  END o[169]
  PIN o[16]
    DIRECTION OUTPUT ;
    USE SIGNAL ;
    PORT
      LAYER M4 ;
        RECT  0 3.888 0.192 3.912 ;
    END
  END o[16]
  PIN o[170]
    DIRECTION OUTPUT ;
    USE SIGNAL ;
    PORT
      LAYER M4 ;
        RECT  0 19.968 0.192 19.992 ;
    END
  END o[170]
  PIN o[171]
    DIRECTION OUTPUT ;
    USE SIGNAL ;
    PORT
      LAYER M4 ;
        RECT  0 20.064 0.192 20.088 ;
    END
  END o[171]
  PIN o[172]
    DIRECTION OUTPUT ;
    USE SIGNAL ;
    PORT
      LAYER M4 ;
        RECT  0 20.16 0.192 20.184 ;
    END
  END o[172]
  PIN o[173]
    DIRECTION OUTPUT ;
    USE SIGNAL ;
    PORT
      LAYER M4 ;
        RECT  0 20.256 0.192 20.28 ;
    END
  END o[173]
  PIN o[174]
    DIRECTION OUTPUT ;
    USE SIGNAL ;
    PORT
      LAYER M4 ;
        RECT  0 20.4 0.192 20.424 ;
    END
  END o[174]
  PIN o[175]
    DIRECTION OUTPUT ;
    USE SIGNAL ;
    PORT
      LAYER M4 ;
        RECT  0 20.496 0.192 20.52 ;
    END
  END o[175]
  PIN o[176]
    DIRECTION OUTPUT ;
    USE SIGNAL ;
    PORT
      LAYER M4 ;
        RECT  0 20.592 0.192 20.616 ;
    END
  END o[176]
  PIN o[177]
    DIRECTION OUTPUT ;
    USE SIGNAL ;
    PORT
      LAYER M4 ;
        RECT  0 20.688 0.192 20.712 ;
    END
  END o[177]
  PIN o[178]
    DIRECTION OUTPUT ;
    USE SIGNAL ;
    PORT
      LAYER M4 ;
        RECT  0 20.784 0.192 20.808 ;
    END
  END o[178]
  PIN o[179]
    DIRECTION OUTPUT ;
    USE SIGNAL ;
    PORT
      LAYER M4 ;
        RECT  0 20.928 0.192 20.952 ;
    END
  END o[179]
  PIN o[17]
    DIRECTION OUTPUT ;
    USE SIGNAL ;
    PORT
      LAYER M4 ;
        RECT  0 3.984 0.192 4.008 ;
    END
  END o[17]
  PIN o[180]
    DIRECTION OUTPUT ;
    USE SIGNAL ;
    PORT
      LAYER M4 ;
        RECT  0 21.024 0.192 21.048 ;
    END
  END o[180]
  PIN o[181]
    DIRECTION OUTPUT ;
    USE SIGNAL ;
    PORT
      LAYER M4 ;
        RECT  0 21.12 0.192 21.144 ;
    END
  END o[181]
  PIN o[182]
    DIRECTION OUTPUT ;
    USE SIGNAL ;
    PORT
      LAYER M4 ;
        RECT  0 21.216 0.192 21.24 ;
    END
  END o[182]
  PIN o[183]
    DIRECTION OUTPUT ;
    USE SIGNAL ;
    PORT
      LAYER M4 ;
        RECT  0 21.312 0.192 21.336 ;
    END
  END o[183]
  PIN o[184]
    DIRECTION OUTPUT ;
    USE SIGNAL ;
    PORT
      LAYER M4 ;
        RECT  0 21.408 0.192 21.432 ;
    END
  END o[184]
  PIN o[185]
    DIRECTION OUTPUT ;
    USE SIGNAL ;
    PORT
      LAYER M4 ;
        RECT  0 21.552 0.192 21.576 ;
    END
  END o[185]
  PIN o[186]
    DIRECTION OUTPUT ;
    USE SIGNAL ;
    PORT
      LAYER M4 ;
        RECT  0 21.648 0.192 21.672 ;
    END
  END o[186]
  PIN o[187]
    DIRECTION OUTPUT ;
    USE SIGNAL ;
    PORT
      LAYER M4 ;
        RECT  0 21.744 0.192 21.768 ;
    END
  END o[187]
  PIN o[188]
    DIRECTION OUTPUT ;
    USE SIGNAL ;
    PORT
      LAYER M4 ;
        RECT  0 21.84 0.192 21.864 ;
    END
  END o[188]
  PIN o[189]
    DIRECTION OUTPUT ;
    USE SIGNAL ;
    PORT
      LAYER M4 ;
        RECT  0 21.936 0.192 21.96 ;
    END
  END o[189]
  PIN o[18]
    DIRECTION OUTPUT ;
    USE SIGNAL ;
    PORT
      LAYER M4 ;
        RECT  0 4.08 0.192 4.104 ;
    END
  END o[18]
  PIN o[190]
    DIRECTION OUTPUT ;
    USE SIGNAL ;
    PORT
      LAYER M4 ;
        RECT  0 22.032 0.192 22.056 ;
    END
  END o[190]
  PIN o[191]
    DIRECTION OUTPUT ;
    USE SIGNAL ;
    PORT
      LAYER M4 ;
        RECT  0 22.176 0.192 22.2 ;
    END
  END o[191]
  PIN o[192]
    DIRECTION OUTPUT ;
    USE SIGNAL ;
    PORT
      LAYER M4 ;
        RECT  0 22.272 0.192 22.296 ;
    END
  END o[192]
  PIN o[193]
    DIRECTION OUTPUT ;
    USE SIGNAL ;
    PORT
      LAYER M4 ;
        RECT  0 22.368 0.192 22.392 ;
    END
  END o[193]
  PIN o[194]
    DIRECTION OUTPUT ;
    USE SIGNAL ;
    PORT
      LAYER M4 ;
        RECT  0 22.464 0.192 22.488 ;
    END
  END o[194]
  PIN o[195]
    DIRECTION OUTPUT ;
    USE SIGNAL ;
    PORT
      LAYER M4 ;
        RECT  0 22.56 0.192 22.584 ;
    END
  END o[195]
  PIN o[196]
    DIRECTION OUTPUT ;
    USE SIGNAL ;
    PORT
      LAYER M4 ;
        RECT  0 22.656 0.192 22.68 ;
    END
  END o[196]
  PIN o[197]
    DIRECTION OUTPUT ;
    USE SIGNAL ;
    PORT
      LAYER M4 ;
        RECT  0 22.8 0.192 22.824 ;
    END
  END o[197]
  PIN o[198]
    DIRECTION OUTPUT ;
    USE SIGNAL ;
    PORT
      LAYER M4 ;
        RECT  0 22.896 0.192 22.92 ;
    END
  END o[198]
  PIN o[199]
    DIRECTION OUTPUT ;
    USE SIGNAL ;
    PORT
      LAYER M4 ;
        RECT  0 22.992 0.192 23.016 ;
    END
  END o[199]
  PIN o[19]
    DIRECTION OUTPUT ;
    USE SIGNAL ;
    PORT
      LAYER M4 ;
        RECT  0 4.224 0.192 4.248 ;
    END
  END o[19]
  PIN o[1]
    DIRECTION OUTPUT ;
    USE SIGNAL ;
    PORT
      LAYER M4 ;
        RECT  0 2.352 0.192 2.376 ;
    END
  END o[1]
  PIN o[200]
    DIRECTION OUTPUT ;
    USE SIGNAL ;
    PORT
      LAYER M4 ;
        RECT  0 23.088 0.192 23.112 ;
    END
  END o[200]
  PIN o[201]
    DIRECTION OUTPUT ;
    USE SIGNAL ;
    PORT
      LAYER M4 ;
        RECT  0 23.184 0.192 23.208 ;
    END
  END o[201]
  PIN o[202]
    DIRECTION OUTPUT ;
    USE SIGNAL ;
    PORT
      LAYER M4 ;
        RECT  0 23.328 0.192 23.352 ;
    END
  END o[202]
  PIN o[203]
    DIRECTION OUTPUT ;
    USE SIGNAL ;
    PORT
      LAYER M4 ;
        RECT  0 23.424 0.192 23.448 ;
    END
  END o[203]
  PIN o[204]
    DIRECTION OUTPUT ;
    USE SIGNAL ;
    PORT
      LAYER M4 ;
        RECT  0 23.52 0.192 23.544 ;
    END
  END o[204]
  PIN o[205]
    DIRECTION OUTPUT ;
    USE SIGNAL ;
    PORT
      LAYER M4 ;
        RECT  0 23.616 0.192 23.64 ;
    END
  END o[205]
  PIN o[206]
    DIRECTION OUTPUT ;
    USE SIGNAL ;
    PORT
      LAYER M4 ;
        RECT  0 23.712 0.192 23.736 ;
    END
  END o[206]
  PIN o[207]
    DIRECTION OUTPUT ;
    USE SIGNAL ;
    PORT
      LAYER M4 ;
        RECT  0 23.808 0.192 23.832 ;
    END
  END o[207]
  PIN o[208]
    DIRECTION OUTPUT ;
    USE SIGNAL ;
    PORT
      LAYER M4 ;
        RECT  0 23.952 0.192 23.976 ;
    END
  END o[208]
  PIN o[209]
    DIRECTION OUTPUT ;
    USE SIGNAL ;
    PORT
      LAYER M4 ;
        RECT  0 24.048 0.192 24.072 ;
    END
  END o[209]
  PIN o[20]
    DIRECTION OUTPUT ;
    USE SIGNAL ;
    PORT
      LAYER M4 ;
        RECT  0 4.32 0.192 4.344 ;
    END
  END o[20]
  PIN o[210]
    DIRECTION OUTPUT ;
    USE SIGNAL ;
    PORT
      LAYER M4 ;
        RECT  0 24.144 0.192 24.168 ;
    END
  END o[210]
  PIN o[211]
    DIRECTION OUTPUT ;
    USE SIGNAL ;
    PORT
      LAYER M4 ;
        RECT  0 24.24 0.192 24.264 ;
    END
  END o[211]
  PIN o[212]
    DIRECTION OUTPUT ;
    USE SIGNAL ;
    PORT
      LAYER M4 ;
        RECT  0 24.336 0.192 24.36 ;
    END
  END o[212]
  PIN o[213]
    DIRECTION OUTPUT ;
    USE SIGNAL ;
    PORT
      LAYER M4 ;
        RECT  0 24.432 0.192 24.456 ;
    END
  END o[213]
  PIN o[214]
    DIRECTION OUTPUT ;
    USE SIGNAL ;
    PORT
      LAYER M4 ;
        RECT  0 24.576 0.192 24.6 ;
    END
  END o[214]
  PIN o[215]
    DIRECTION OUTPUT ;
    USE SIGNAL ;
    PORT
      LAYER M4 ;
        RECT  0 24.672 0.192 24.696 ;
    END
  END o[215]
  PIN o[216]
    DIRECTION OUTPUT ;
    USE SIGNAL ;
    PORT
      LAYER M4 ;
        RECT  0 24.768 0.192 24.792 ;
    END
  END o[216]
  PIN o[217]
    DIRECTION OUTPUT ;
    USE SIGNAL ;
    PORT
      LAYER M4 ;
        RECT  0 24.864 0.192 24.888 ;
    END
  END o[217]
  PIN o[218]
    DIRECTION OUTPUT ;
    USE SIGNAL ;
    PORT
      LAYER M4 ;
        RECT  0 24.96 0.192 24.984 ;
    END
  END o[218]
  PIN o[219]
    DIRECTION OUTPUT ;
    USE SIGNAL ;
    PORT
      LAYER M4 ;
        RECT  0 25.056 0.192 25.08 ;
    END
  END o[219]
  PIN o[21]
    DIRECTION OUTPUT ;
    USE SIGNAL ;
    PORT
      LAYER M4 ;
        RECT  0 4.416 0.192 4.44 ;
    END
  END o[21]
  PIN o[220]
    DIRECTION OUTPUT ;
    USE SIGNAL ;
    PORT
      LAYER M4 ;
        RECT  0 25.2 0.192 25.224 ;
    END
  END o[220]
  PIN o[221]
    DIRECTION OUTPUT ;
    USE SIGNAL ;
    PORT
      LAYER M4 ;
        RECT  0 25.296 0.192 25.32 ;
    END
  END o[221]
  PIN o[222]
    DIRECTION OUTPUT ;
    USE SIGNAL ;
    PORT
      LAYER M4 ;
        RECT  0 25.392 0.192 25.416 ;
    END
  END o[222]
  PIN o[223]
    DIRECTION OUTPUT ;
    USE SIGNAL ;
    PORT
      LAYER M4 ;
        RECT  0 25.488 0.192 25.512 ;
    END
  END o[223]
  PIN o[224]
    DIRECTION OUTPUT ;
    USE SIGNAL ;
    PORT
      LAYER M4 ;
        RECT  0 25.584 0.192 25.608 ;
    END
  END o[224]
  PIN o[225]
    DIRECTION OUTPUT ;
    USE SIGNAL ;
    PORT
      LAYER M4 ;
        RECT  0 25.728 0.192 25.752 ;
    END
  END o[225]
  PIN o[226]
    DIRECTION OUTPUT ;
    USE SIGNAL ;
    PORT
      LAYER M4 ;
        RECT  0 25.824 0.192 25.848 ;
    END
  END o[226]
  PIN o[227]
    DIRECTION OUTPUT ;
    USE SIGNAL ;
    PORT
      LAYER M4 ;
        RECT  0 25.92 0.192 25.944 ;
    END
  END o[227]
  PIN o[228]
    DIRECTION OUTPUT ;
    USE SIGNAL ;
    PORT
      LAYER M4 ;
        RECT  0 26.016 0.192 26.04 ;
    END
  END o[228]
  PIN o[229]
    DIRECTION OUTPUT ;
    USE SIGNAL ;
    PORT
      LAYER M4 ;
        RECT  0 26.112 0.192 26.136 ;
    END
  END o[229]
  PIN o[22]
    DIRECTION OUTPUT ;
    USE SIGNAL ;
    PORT
      LAYER M4 ;
        RECT  0 4.512 0.192 4.536 ;
    END
  END o[22]
  PIN o[230]
    DIRECTION OUTPUT ;
    USE SIGNAL ;
    PORT
      LAYER M4 ;
        RECT  0 26.208 0.192 26.232 ;
    END
  END o[230]
  PIN o[231]
    DIRECTION OUTPUT ;
    USE SIGNAL ;
    PORT
      LAYER M4 ;
        RECT  0 26.352 0.192 26.376 ;
    END
  END o[231]
  PIN o[232]
    DIRECTION OUTPUT ;
    USE SIGNAL ;
    PORT
      LAYER M4 ;
        RECT  0 26.448 0.192 26.472 ;
    END
  END o[232]
  PIN o[233]
    DIRECTION OUTPUT ;
    USE SIGNAL ;
    PORT
      LAYER M4 ;
        RECT  0 26.544 0.192 26.568 ;
    END
  END o[233]
  PIN o[234]
    DIRECTION OUTPUT ;
    USE SIGNAL ;
    PORT
      LAYER M4 ;
        RECT  0 26.64 0.192 26.664 ;
    END
  END o[234]
  PIN o[235]
    DIRECTION OUTPUT ;
    USE SIGNAL ;
    PORT
      LAYER M4 ;
        RECT  0 26.736 0.192 26.76 ;
    END
  END o[235]
  PIN o[236]
    DIRECTION OUTPUT ;
    USE SIGNAL ;
    PORT
      LAYER M4 ;
        RECT  0 26.832 0.192 26.856 ;
    END
  END o[236]
  PIN o[237]
    DIRECTION OUTPUT ;
    USE SIGNAL ;
    PORT
      LAYER M4 ;
        RECT  0 26.976 0.192 27 ;
    END
  END o[237]
  PIN o[238]
    DIRECTION OUTPUT ;
    USE SIGNAL ;
    PORT
      LAYER M4 ;
        RECT  0 27.072 0.192 27.096 ;
    END
  END o[238]
  PIN o[239]
    DIRECTION OUTPUT ;
    USE SIGNAL ;
    PORT
      LAYER M4 ;
        RECT  0 27.168 0.192 27.192 ;
    END
  END o[239]
  PIN o[23]
    DIRECTION OUTPUT ;
    USE SIGNAL ;
    PORT
      LAYER M4 ;
        RECT  0 4.608 0.192 4.632 ;
    END
  END o[23]
  PIN o[240]
    DIRECTION OUTPUT ;
    USE SIGNAL ;
    PORT
      LAYER M4 ;
        RECT  0 27.264 0.192 27.288 ;
    END
  END o[240]
  PIN o[241]
    DIRECTION OUTPUT ;
    USE SIGNAL ;
    PORT
      LAYER M4 ;
        RECT  0 27.36 0.192 27.384 ;
    END
  END o[241]
  PIN o[242]
    DIRECTION OUTPUT ;
    USE SIGNAL ;
    PORT
      LAYER M4 ;
        RECT  0 27.504 0.192 27.528 ;
    END
  END o[242]
  PIN o[243]
    DIRECTION OUTPUT ;
    USE SIGNAL ;
    PORT
      LAYER M4 ;
        RECT  0 27.6 0.192 27.624 ;
    END
  END o[243]
  PIN o[244]
    DIRECTION OUTPUT ;
    USE SIGNAL ;
    PORT
      LAYER M4 ;
        RECT  0 27.696 0.192 27.72 ;
    END
  END o[244]
  PIN o[245]
    DIRECTION OUTPUT ;
    USE SIGNAL ;
    PORT
      LAYER M4 ;
        RECT  0 27.792 0.192 27.816 ;
    END
  END o[245]
  PIN o[246]
    DIRECTION OUTPUT ;
    USE SIGNAL ;
    PORT
      LAYER M4 ;
        RECT  0 27.888 0.192 27.912 ;
    END
  END o[246]
  PIN o[247]
    DIRECTION OUTPUT ;
    USE SIGNAL ;
    PORT
      LAYER M4 ;
        RECT  0 27.984 0.192 28.008 ;
    END
  END o[247]
  PIN o[248]
    DIRECTION OUTPUT ;
    USE SIGNAL ;
    PORT
      LAYER M4 ;
        RECT  0 28.128 0.192 28.152 ;
    END
  END o[248]
  PIN o[249]
    DIRECTION OUTPUT ;
    USE SIGNAL ;
    PORT
      LAYER M4 ;
        RECT  0 28.224 0.192 28.248 ;
    END
  END o[249]
  PIN o[24]
    DIRECTION OUTPUT ;
    USE SIGNAL ;
    PORT
      LAYER M4 ;
        RECT  0 4.752 0.192 4.776 ;
    END
  END o[24]
  PIN o[250]
    DIRECTION OUTPUT ;
    USE SIGNAL ;
    PORT
      LAYER M4 ;
        RECT  0 28.32 0.192 28.344 ;
    END
  END o[250]
  PIN o[251]
    DIRECTION OUTPUT ;
    USE SIGNAL ;
    PORT
      LAYER M4 ;
        RECT  0 28.416 0.192 28.44 ;
    END
  END o[251]
  PIN o[252]
    DIRECTION OUTPUT ;
    USE SIGNAL ;
    PORT
      LAYER M4 ;
        RECT  0 28.512 0.192 28.536 ;
    END
  END o[252]
  PIN o[253]
    DIRECTION OUTPUT ;
    USE SIGNAL ;
    PORT
      LAYER M4 ;
        RECT  0 28.608 0.192 28.632 ;
    END
  END o[253]
  PIN o[254]
    DIRECTION OUTPUT ;
    USE SIGNAL ;
    PORT
      LAYER M4 ;
        RECT  0 28.752 0.192 28.776 ;
    END
  END o[254]
  PIN o[255]
    DIRECTION OUTPUT ;
    USE SIGNAL ;
    PORT
      LAYER M4 ;
        RECT  0 28.848 0.192 28.872 ;
    END
  END o[255]
  PIN o[256]
    DIRECTION OUTPUT ;
    USE SIGNAL ;
    PORT
      LAYER M4 ;
        RECT  0 28.944 0.192 28.968 ;
    END
  END o[256]
  PIN o[257]
    DIRECTION OUTPUT ;
    USE SIGNAL ;
    PORT
      LAYER M4 ;
        RECT  0 29.04 0.192 29.064 ;
    END
  END o[257]
  PIN o[258]
    DIRECTION OUTPUT ;
    USE SIGNAL ;
    PORT
      LAYER M4 ;
        RECT  0 29.136 0.192 29.16 ;
    END
  END o[258]
  PIN o[259]
    DIRECTION OUTPUT ;
    USE SIGNAL ;
    PORT
      LAYER M4 ;
        RECT  0 29.232 0.192 29.256 ;
    END
  END o[259]
  PIN o[25]
    DIRECTION OUTPUT ;
    USE SIGNAL ;
    PORT
      LAYER M4 ;
        RECT  0 4.848 0.192 4.872 ;
    END
  END o[25]
  PIN o[260]
    DIRECTION OUTPUT ;
    USE SIGNAL ;
    PORT
      LAYER M4 ;
        RECT  0 29.376 0.192 29.4 ;
    END
  END o[260]
  PIN o[261]
    DIRECTION OUTPUT ;
    USE SIGNAL ;
    PORT
      LAYER M4 ;
        RECT  0 29.472 0.192 29.496 ;
    END
  END o[261]
  PIN o[262]
    DIRECTION OUTPUT ;
    USE SIGNAL ;
    PORT
      LAYER M4 ;
        RECT  0 29.568 0.192 29.592 ;
    END
  END o[262]
  PIN o[263]
    DIRECTION OUTPUT ;
    USE SIGNAL ;
    PORT
      LAYER M4 ;
        RECT  0 29.664 0.192 29.688 ;
    END
  END o[263]
  PIN o[264]
    DIRECTION OUTPUT ;
    USE SIGNAL ;
    PORT
      LAYER M4 ;
        RECT  0 29.76 0.192 29.784 ;
    END
  END o[264]
  PIN o[265]
    DIRECTION OUTPUT ;
    USE SIGNAL ;
    PORT
      LAYER M4 ;
        RECT  0 29.904 0.192 29.928 ;
    END
  END o[265]
  PIN o[266]
    DIRECTION OUTPUT ;
    USE SIGNAL ;
    PORT
      LAYER M4 ;
        RECT  0 30 0.192 30.024 ;
    END
  END o[266]
  PIN o[267]
    DIRECTION OUTPUT ;
    USE SIGNAL ;
    PORT
      LAYER M4 ;
        RECT  0 30.096 0.192 30.12 ;
    END
  END o[267]
  PIN o[268]
    DIRECTION OUTPUT ;
    USE SIGNAL ;
    PORT
      LAYER M4 ;
        RECT  0 30.192 0.192 30.216 ;
    END
  END o[268]
  PIN o[269]
    DIRECTION OUTPUT ;
    USE SIGNAL ;
    PORT
      LAYER M4 ;
        RECT  0 30.288 0.192 30.312 ;
    END
  END o[269]
  PIN o[26]
    DIRECTION OUTPUT ;
    USE SIGNAL ;
    PORT
      LAYER M4 ;
        RECT  0 4.944 0.192 4.968 ;
    END
  END o[26]
  PIN o[270]
    DIRECTION OUTPUT ;
    USE SIGNAL ;
    PORT
      LAYER M4 ;
        RECT  0 30.384 0.192 30.408 ;
    END
  END o[270]
  PIN o[271]
    DIRECTION OUTPUT ;
    USE SIGNAL ;
    PORT
      LAYER M4 ;
        RECT  0 30.528 0.192 30.552 ;
    END
  END o[271]
  PIN o[272]
    DIRECTION OUTPUT ;
    USE SIGNAL ;
    PORT
      LAYER M4 ;
        RECT  0 30.624 0.192 30.648 ;
    END
  END o[272]
  PIN o[273]
    DIRECTION OUTPUT ;
    USE SIGNAL ;
    PORT
      LAYER M4 ;
        RECT  0 30.72 0.192 30.744 ;
    END
  END o[273]
  PIN o[274]
    DIRECTION OUTPUT ;
    USE SIGNAL ;
    PORT
      LAYER M4 ;
        RECT  0 30.816 0.192 30.84 ;
    END
  END o[274]
  PIN o[275]
    DIRECTION OUTPUT ;
    USE SIGNAL ;
    PORT
      LAYER M4 ;
        RECT  0 30.912 0.192 30.936 ;
    END
  END o[275]
  PIN o[276]
    DIRECTION OUTPUT ;
    USE SIGNAL ;
    PORT
      LAYER M4 ;
        RECT  0 31.008 0.192 31.032 ;
    END
  END o[276]
  PIN o[277]
    DIRECTION OUTPUT ;
    USE SIGNAL ;
    PORT
      LAYER M4 ;
        RECT  0 31.152 0.192 31.176 ;
    END
  END o[277]
  PIN o[278]
    DIRECTION OUTPUT ;
    USE SIGNAL ;
    PORT
      LAYER M4 ;
        RECT  0 31.248 0.192 31.272 ;
    END
  END o[278]
  PIN o[279]
    DIRECTION OUTPUT ;
    USE SIGNAL ;
    PORT
      LAYER M4 ;
        RECT  0 31.344 0.192 31.368 ;
    END
  END o[279]
  PIN o[27]
    DIRECTION OUTPUT ;
    USE SIGNAL ;
    PORT
      LAYER M4 ;
        RECT  0 5.04 0.192 5.064 ;
    END
  END o[27]
  PIN o[280]
    DIRECTION OUTPUT ;
    USE SIGNAL ;
    PORT
      LAYER M4 ;
        RECT  0 31.44 0.192 31.464 ;
    END
  END o[280]
  PIN o[281]
    DIRECTION OUTPUT ;
    USE SIGNAL ;
    PORT
      LAYER M4 ;
        RECT  0 31.536 0.192 31.56 ;
    END
  END o[281]
  PIN o[282]
    DIRECTION OUTPUT ;
    USE SIGNAL ;
    PORT
      LAYER M4 ;
        RECT  0 31.632 0.192 31.656 ;
    END
  END o[282]
  PIN o[283]
    DIRECTION OUTPUT ;
    USE SIGNAL ;
    PORT
      LAYER M4 ;
        RECT  0 31.776 0.192 31.8 ;
    END
  END o[283]
  PIN o[284]
    DIRECTION OUTPUT ;
    USE SIGNAL ;
    PORT
      LAYER M4 ;
        RECT  0 31.872 0.192 31.896 ;
    END
  END o[284]
  PIN o[285]
    DIRECTION OUTPUT ;
    USE SIGNAL ;
    PORT
      LAYER M4 ;
        RECT  0 31.968 0.192 31.992 ;
    END
  END o[285]
  PIN o[286]
    DIRECTION OUTPUT ;
    USE SIGNAL ;
    PORT
      LAYER M4 ;
        RECT  0 32.064 0.192 32.088 ;
    END
  END o[286]
  PIN o[287]
    DIRECTION OUTPUT ;
    USE SIGNAL ;
    PORT
      LAYER M4 ;
        RECT  0 32.16 0.192 32.184 ;
    END
  END o[287]
  PIN o[288]
    DIRECTION OUTPUT ;
    USE SIGNAL ;
    PORT
      LAYER M4 ;
        RECT  0 32.304 0.192 32.328 ;
    END
  END o[288]
  PIN o[289]
    DIRECTION OUTPUT ;
    USE SIGNAL ;
    PORT
      LAYER M4 ;
        RECT  0 32.4 0.192 32.424 ;
    END
  END o[289]
  PIN o[28]
    DIRECTION OUTPUT ;
    USE SIGNAL ;
    PORT
      LAYER M4 ;
        RECT  0 5.136 0.192 5.16 ;
    END
  END o[28]
  PIN o[290]
    DIRECTION OUTPUT ;
    USE SIGNAL ;
    PORT
      LAYER M4 ;
        RECT  0 32.496 0.192 32.52 ;
    END
  END o[290]
  PIN o[291]
    DIRECTION OUTPUT ;
    USE SIGNAL ;
    PORT
      LAYER M4 ;
        RECT  0 32.592 0.192 32.616 ;
    END
  END o[291]
  PIN o[292]
    DIRECTION OUTPUT ;
    USE SIGNAL ;
    PORT
      LAYER M4 ;
        RECT  0 32.688 0.192 32.712 ;
    END
  END o[292]
  PIN o[293]
    DIRECTION OUTPUT ;
    USE SIGNAL ;
    PORT
      LAYER M4 ;
        RECT  0 32.784 0.192 32.808 ;
    END
  END o[293]
  PIN o[294]
    DIRECTION OUTPUT ;
    USE SIGNAL ;
    PORT
      LAYER M4 ;
        RECT  0 32.928 0.192 32.952 ;
    END
  END o[294]
  PIN o[295]
    DIRECTION OUTPUT ;
    USE SIGNAL ;
    PORT
      LAYER M4 ;
        RECT  0 33.024 0.192 33.048 ;
    END
  END o[295]
  PIN o[296]
    DIRECTION OUTPUT ;
    USE SIGNAL ;
    PORT
      LAYER M4 ;
        RECT  0 33.12 0.192 33.144 ;
    END
  END o[296]
  PIN o[297]
    DIRECTION OUTPUT ;
    USE SIGNAL ;
    PORT
      LAYER M4 ;
        RECT  0 33.216 0.192 33.24 ;
    END
  END o[297]
  PIN o[298]
    DIRECTION OUTPUT ;
    USE SIGNAL ;
    PORT
      LAYER M4 ;
        RECT  0 33.312 0.192 33.336 ;
    END
  END o[298]
  PIN o[299]
    DIRECTION OUTPUT ;
    USE SIGNAL ;
    PORT
      LAYER M4 ;
        RECT  0 33.408 0.192 33.432 ;
    END
  END o[299]
  PIN o[29]
    DIRECTION OUTPUT ;
    USE SIGNAL ;
    PORT
      LAYER M4 ;
        RECT  0 5.232 0.192 5.256 ;
    END
  END o[29]
  PIN o[2]
    DIRECTION OUTPUT ;
    USE SIGNAL ;
    PORT
      LAYER M4 ;
        RECT  0 2.448 0.192 2.472 ;
    END
  END o[2]
  PIN o[300]
    DIRECTION OUTPUT ;
    USE SIGNAL ;
    PORT
      LAYER M4 ;
        RECT  0 33.552 0.192 33.576 ;
    END
  END o[300]
  PIN o[301]
    DIRECTION OUTPUT ;
    USE SIGNAL ;
    PORT
      LAYER M4 ;
        RECT  0 33.648 0.192 33.672 ;
    END
  END o[301]
  PIN o[302]
    DIRECTION OUTPUT ;
    USE SIGNAL ;
    PORT
      LAYER M4 ;
        RECT  0 33.744 0.192 33.768 ;
    END
  END o[302]
  PIN o[303]
    DIRECTION OUTPUT ;
    USE SIGNAL ;
    PORT
      LAYER M4 ;
        RECT  0 33.84 0.192 33.864 ;
    END
  END o[303]
  PIN o[304]
    DIRECTION OUTPUT ;
    USE SIGNAL ;
    PORT
      LAYER M4 ;
        RECT  0 33.936 0.192 33.96 ;
    END
  END o[304]
  PIN o[305]
    DIRECTION OUTPUT ;
    USE SIGNAL ;
    PORT
      LAYER M4 ;
        RECT  0 34.032 0.192 34.056 ;
    END
  END o[305]
  PIN o[306]
    DIRECTION OUTPUT ;
    USE SIGNAL ;
    PORT
      LAYER M4 ;
        RECT  0 34.176 0.192 34.2 ;
    END
  END o[306]
  PIN o[307]
    DIRECTION OUTPUT ;
    USE SIGNAL ;
    PORT
      LAYER M4 ;
        RECT  0 34.272 0.192 34.296 ;
    END
  END o[307]
  PIN o[308]
    DIRECTION OUTPUT ;
    USE SIGNAL ;
    PORT
      LAYER M4 ;
        RECT  0 34.368 0.192 34.392 ;
    END
  END o[308]
  PIN o[309]
    DIRECTION OUTPUT ;
    USE SIGNAL ;
    PORT
      LAYER M4 ;
        RECT  0 34.464 0.192 34.488 ;
    END
  END o[309]
  PIN o[30]
    DIRECTION OUTPUT ;
    USE SIGNAL ;
    PORT
      LAYER M4 ;
        RECT  0 5.376 0.192 5.4 ;
    END
  END o[30]
  PIN o[310]
    DIRECTION OUTPUT ;
    USE SIGNAL ;
    PORT
      LAYER M4 ;
        RECT  0 34.56 0.192 34.584 ;
    END
  END o[310]
  PIN o[311]
    DIRECTION OUTPUT ;
    USE SIGNAL ;
    PORT
      LAYER M4 ;
        RECT  0 34.704 0.192 34.728 ;
    END
  END o[311]
  PIN o[312]
    DIRECTION OUTPUT ;
    USE SIGNAL ;
    PORT
      LAYER M4 ;
        RECT  0 34.8 0.192 34.824 ;
    END
  END o[312]
  PIN o[313]
    DIRECTION OUTPUT ;
    USE SIGNAL ;
    PORT
      LAYER M4 ;
        RECT  0 34.896 0.192 34.92 ;
    END
  END o[313]
  PIN o[314]
    DIRECTION OUTPUT ;
    USE SIGNAL ;
    PORT
      LAYER M4 ;
        RECT  0 34.992 0.192 35.016 ;
    END
  END o[314]
  PIN o[315]
    DIRECTION OUTPUT ;
    USE SIGNAL ;
    PORT
      LAYER M4 ;
        RECT  0 35.088 0.192 35.112 ;
    END
  END o[315]
  PIN o[316]
    DIRECTION OUTPUT ;
    USE SIGNAL ;
    PORT
      LAYER M4 ;
        RECT  0 35.184 0.192 35.208 ;
    END
  END o[316]
  PIN o[317]
    DIRECTION OUTPUT ;
    USE SIGNAL ;
    PORT
      LAYER M4 ;
        RECT  0 35.328 0.192 35.352 ;
    END
  END o[317]
  PIN o[318]
    DIRECTION OUTPUT ;
    USE SIGNAL ;
    PORT
      LAYER M4 ;
        RECT  0 35.424 0.192 35.448 ;
    END
  END o[318]
  PIN o[319]
    DIRECTION OUTPUT ;
    USE SIGNAL ;
    PORT
      LAYER M4 ;
        RECT  0 35.52 0.192 35.544 ;
    END
  END o[319]
  PIN o[31]
    DIRECTION OUTPUT ;
    USE SIGNAL ;
    PORT
      LAYER M4 ;
        RECT  0 5.472 0.192 5.496 ;
    END
  END o[31]
  PIN o[320]
    DIRECTION OUTPUT ;
    USE SIGNAL ;
    PORT
      LAYER M4 ;
        RECT  0 35.616 0.192 35.64 ;
    END
  END o[320]
  PIN o[321]
    DIRECTION OUTPUT ;
    USE SIGNAL ;
    PORT
      LAYER M4 ;
        RECT  0 35.712 0.192 35.736 ;
    END
  END o[321]
  PIN o[322]
    DIRECTION OUTPUT ;
    USE SIGNAL ;
    PORT
      LAYER M4 ;
        RECT  0 35.808 0.192 35.832 ;
    END
  END o[322]
  PIN o[323]
    DIRECTION OUTPUT ;
    USE SIGNAL ;
    PORT
      LAYER M4 ;
        RECT  0 35.952 0.192 35.976 ;
    END
  END o[323]
  PIN o[324]
    DIRECTION OUTPUT ;
    USE SIGNAL ;
    PORT
      LAYER M4 ;
        RECT  0 36.048 0.192 36.072 ;
    END
  END o[324]
  PIN o[325]
    DIRECTION OUTPUT ;
    USE SIGNAL ;
    PORT
      LAYER M4 ;
        RECT  0 36.144 0.192 36.168 ;
    END
  END o[325]
  PIN o[326]
    DIRECTION OUTPUT ;
    USE SIGNAL ;
    PORT
      LAYER M4 ;
        RECT  0 36.24 0.192 36.264 ;
    END
  END o[326]
  PIN o[327]
    DIRECTION OUTPUT ;
    USE SIGNAL ;
    PORT
      LAYER M4 ;
        RECT  0 36.336 0.192 36.36 ;
    END
  END o[327]
  PIN o[328]
    DIRECTION OUTPUT ;
    USE SIGNAL ;
    PORT
      LAYER M4 ;
        RECT  0 36.432 0.192 36.456 ;
    END
  END o[328]
  PIN o[329]
    DIRECTION OUTPUT ;
    USE SIGNAL ;
    PORT
      LAYER M4 ;
        RECT  0 36.576 0.192 36.6 ;
    END
  END o[329]
  PIN o[32]
    DIRECTION OUTPUT ;
    USE SIGNAL ;
    PORT
      LAYER M4 ;
        RECT  0 5.568 0.192 5.592 ;
    END
  END o[32]
  PIN o[330]
    DIRECTION OUTPUT ;
    USE SIGNAL ;
    PORT
      LAYER M4 ;
        RECT  0 36.672 0.192 36.696 ;
    END
  END o[330]
  PIN o[331]
    DIRECTION OUTPUT ;
    USE SIGNAL ;
    PORT
      LAYER M4 ;
        RECT  0 36.768 0.192 36.792 ;
    END
  END o[331]
  PIN o[332]
    DIRECTION OUTPUT ;
    USE SIGNAL ;
    PORT
      LAYER M4 ;
        RECT  0 36.864 0.192 36.888 ;
    END
  END o[332]
  PIN o[333]
    DIRECTION OUTPUT ;
    USE SIGNAL ;
    PORT
      LAYER M4 ;
        RECT  0 36.96 0.192 36.984 ;
    END
  END o[333]
  PIN o[334]
    DIRECTION OUTPUT ;
    USE SIGNAL ;
    PORT
      LAYER M4 ;
        RECT  0 37.104 0.192 37.128 ;
    END
  END o[334]
  PIN o[335]
    DIRECTION OUTPUT ;
    USE SIGNAL ;
    PORT
      LAYER M4 ;
        RECT  0 37.2 0.192 37.224 ;
    END
  END o[335]
  PIN o[336]
    DIRECTION OUTPUT ;
    USE SIGNAL ;
    PORT
      LAYER M4 ;
        RECT  0 37.296 0.192 37.32 ;
    END
  END o[336]
  PIN o[337]
    DIRECTION OUTPUT ;
    USE SIGNAL ;
    PORT
      LAYER M4 ;
        RECT  0 37.392 0.192 37.416 ;
    END
  END o[337]
  PIN o[338]
    DIRECTION OUTPUT ;
    USE SIGNAL ;
    PORT
      LAYER M4 ;
        RECT  0 37.488 0.192 37.512 ;
    END
  END o[338]
  PIN o[339]
    DIRECTION OUTPUT ;
    USE SIGNAL ;
    PORT
      LAYER M4 ;
        RECT  0 37.584 0.192 37.608 ;
    END
  END o[339]
  PIN o[33]
    DIRECTION OUTPUT ;
    USE SIGNAL ;
    PORT
      LAYER M4 ;
        RECT  0 5.664 0.192 5.688 ;
    END
  END o[33]
  PIN o[340]
    DIRECTION OUTPUT ;
    USE SIGNAL ;
    PORT
      LAYER M4 ;
        RECT  0 37.728 0.192 37.752 ;
    END
  END o[340]
  PIN o[341]
    DIRECTION OUTPUT ;
    USE SIGNAL ;
    PORT
      LAYER M4 ;
        RECT  0 37.824 0.192 37.848 ;
    END
  END o[341]
  PIN o[342]
    DIRECTION OUTPUT ;
    USE SIGNAL ;
    PORT
      LAYER M4 ;
        RECT  0 37.92 0.192 37.944 ;
    END
  END o[342]
  PIN o[343]
    DIRECTION OUTPUT ;
    USE SIGNAL ;
    PORT
      LAYER M4 ;
        RECT  0 38.016 0.192 38.04 ;
    END
  END o[343]
  PIN o[344]
    DIRECTION OUTPUT ;
    USE SIGNAL ;
    PORT
      LAYER M4 ;
        RECT  0 38.112 0.192 38.136 ;
    END
  END o[344]
  PIN o[345]
    DIRECTION OUTPUT ;
    USE SIGNAL ;
    PORT
      LAYER M4 ;
        RECT  0 38.208 0.192 38.232 ;
    END
  END o[345]
  PIN o[346]
    DIRECTION OUTPUT ;
    USE SIGNAL ;
    PORT
      LAYER M4 ;
        RECT  0 38.352 0.192 38.376 ;
    END
  END o[346]
  PIN o[347]
    DIRECTION OUTPUT ;
    USE SIGNAL ;
    PORT
      LAYER M4 ;
        RECT  0 38.448 0.192 38.472 ;
    END
  END o[347]
  PIN o[348]
    DIRECTION OUTPUT ;
    USE SIGNAL ;
    PORT
      LAYER M4 ;
        RECT  0 38.544 0.192 38.568 ;
    END
  END o[348]
  PIN o[349]
    DIRECTION OUTPUT ;
    USE SIGNAL ;
    PORT
      LAYER M4 ;
        RECT  0 38.64 0.192 38.664 ;
    END
  END o[349]
  PIN o[34]
    DIRECTION OUTPUT ;
    USE SIGNAL ;
    PORT
      LAYER M4 ;
        RECT  0 5.76 0.192 5.784 ;
    END
  END o[34]
  PIN o[350]
    DIRECTION OUTPUT ;
    USE SIGNAL ;
    PORT
      LAYER M4 ;
        RECT  0 38.736 0.192 38.76 ;
    END
  END o[350]
  PIN o[351]
    DIRECTION OUTPUT ;
    USE SIGNAL ;
    PORT
      LAYER M4 ;
        RECT  0 38.832 0.192 38.856 ;
    END
  END o[351]
  PIN o[352]
    DIRECTION OUTPUT ;
    USE SIGNAL ;
    PORT
      LAYER M4 ;
        RECT  0 38.976 0.192 39 ;
    END
  END o[352]
  PIN o[353]
    DIRECTION OUTPUT ;
    USE SIGNAL ;
    PORT
      LAYER M4 ;
        RECT  0 39.072 0.192 39.096 ;
    END
  END o[353]
  PIN o[354]
    DIRECTION OUTPUT ;
    USE SIGNAL ;
    PORT
      LAYER M4 ;
        RECT  0 39.168 0.192 39.192 ;
    END
  END o[354]
  PIN o[355]
    DIRECTION OUTPUT ;
    USE SIGNAL ;
    PORT
      LAYER M4 ;
        RECT  0 39.264 0.192 39.288 ;
    END
  END o[355]
  PIN o[356]
    DIRECTION OUTPUT ;
    USE SIGNAL ;
    PORT
      LAYER M4 ;
        RECT  0 39.36 0.192 39.384 ;
    END
  END o[356]
  PIN o[357]
    DIRECTION OUTPUT ;
    USE SIGNAL ;
    PORT
      LAYER M4 ;
        RECT  0 39.504 0.192 39.528 ;
    END
  END o[357]
  PIN o[358]
    DIRECTION OUTPUT ;
    USE SIGNAL ;
    PORT
      LAYER M4 ;
        RECT  0 39.6 0.192 39.624 ;
    END
  END o[358]
  PIN o[359]
    DIRECTION OUTPUT ;
    USE SIGNAL ;
    PORT
      LAYER M4 ;
        RECT  0 39.696 0.192 39.72 ;
    END
  END o[359]
  PIN o[35]
    DIRECTION OUTPUT ;
    USE SIGNAL ;
    PORT
      LAYER M4 ;
        RECT  0 5.856 0.192 5.88 ;
    END
  END o[35]
  PIN o[360]
    DIRECTION OUTPUT ;
    USE SIGNAL ;
    PORT
      LAYER M4 ;
        RECT  0 39.792 0.192 39.816 ;
    END
  END o[360]
  PIN o[361]
    DIRECTION OUTPUT ;
    USE SIGNAL ;
    PORT
      LAYER M4 ;
        RECT  0 39.888 0.192 39.912 ;
    END
  END o[361]
  PIN o[362]
    DIRECTION OUTPUT ;
    USE SIGNAL ;
    PORT
      LAYER M4 ;
        RECT  0 39.984 0.192 40.008 ;
    END
  END o[362]
  PIN o[363]
    DIRECTION OUTPUT ;
    USE SIGNAL ;
    PORT
      LAYER M4 ;
        RECT  0 40.128 0.192 40.152 ;
    END
  END o[363]
  PIN o[364]
    DIRECTION OUTPUT ;
    USE SIGNAL ;
    PORT
      LAYER M4 ;
        RECT  0 40.224 0.192 40.248 ;
    END
  END o[364]
  PIN o[365]
    DIRECTION OUTPUT ;
    USE SIGNAL ;
    PORT
      LAYER M4 ;
        RECT  0 40.32 0.192 40.344 ;
    END
  END o[365]
  PIN o[366]
    DIRECTION OUTPUT ;
    USE SIGNAL ;
    PORT
      LAYER M4 ;
        RECT  0 40.416 0.192 40.44 ;
    END
  END o[366]
  PIN o[367]
    DIRECTION OUTPUT ;
    USE SIGNAL ;
    PORT
      LAYER M4 ;
        RECT  0 40.512 0.192 40.536 ;
    END
  END o[367]
  PIN o[368]
    DIRECTION OUTPUT ;
    USE SIGNAL ;
    PORT
      LAYER M4 ;
        RECT  0 40.608 0.192 40.632 ;
    END
  END o[368]
  PIN o[369]
    DIRECTION OUTPUT ;
    USE SIGNAL ;
    PORT
      LAYER M4 ;
        RECT  0 40.752 0.192 40.776 ;
    END
  END o[369]
  PIN o[36]
    DIRECTION OUTPUT ;
    USE SIGNAL ;
    PORT
      LAYER M4 ;
        RECT  0 6 0.192 6.024 ;
    END
  END o[36]
  PIN o[370]
    DIRECTION OUTPUT ;
    USE SIGNAL ;
    PORT
      LAYER M4 ;
        RECT  0 40.848 0.192 40.872 ;
    END
  END o[370]
  PIN o[371]
    DIRECTION OUTPUT ;
    USE SIGNAL ;
    PORT
      LAYER M4 ;
        RECT  0 40.944 0.192 40.968 ;
    END
  END o[371]
  PIN o[372]
    DIRECTION OUTPUT ;
    USE SIGNAL ;
    PORT
      LAYER M4 ;
        RECT  0 41.04 0.192 41.064 ;
    END
  END o[372]
  PIN o[373]
    DIRECTION OUTPUT ;
    USE SIGNAL ;
    PORT
      LAYER M4 ;
        RECT  0 41.136 0.192 41.16 ;
    END
  END o[373]
  PIN o[374]
    DIRECTION OUTPUT ;
    USE SIGNAL ;
    PORT
      LAYER M4 ;
        RECT  0 41.232 0.192 41.256 ;
    END
  END o[374]
  PIN o[375]
    DIRECTION OUTPUT ;
    USE SIGNAL ;
    PORT
      LAYER M4 ;
        RECT  0 41.376 0.192 41.4 ;
    END
  END o[375]
  PIN o[376]
    DIRECTION OUTPUT ;
    USE SIGNAL ;
    PORT
      LAYER M4 ;
        RECT  0 41.472 0.192 41.496 ;
    END
  END o[376]
  PIN o[377]
    DIRECTION OUTPUT ;
    USE SIGNAL ;
    PORT
      LAYER M4 ;
        RECT  0 41.568 0.192 41.592 ;
    END
  END o[377]
  PIN o[378]
    DIRECTION OUTPUT ;
    USE SIGNAL ;
    PORT
      LAYER M4 ;
        RECT  0 41.664 0.192 41.688 ;
    END
  END o[378]
  PIN o[379]
    DIRECTION OUTPUT ;
    USE SIGNAL ;
    PORT
      LAYER M4 ;
        RECT  0 41.76 0.192 41.784 ;
    END
  END o[379]
  PIN o[37]
    DIRECTION OUTPUT ;
    USE SIGNAL ;
    PORT
      LAYER M4 ;
        RECT  0 6.096 0.192 6.12 ;
    END
  END o[37]
  PIN o[380]
    DIRECTION OUTPUT ;
    USE SIGNAL ;
    PORT
      LAYER M4 ;
        RECT  0 41.904 0.192 41.928 ;
    END
  END o[380]
  PIN o[381]
    DIRECTION OUTPUT ;
    USE SIGNAL ;
    PORT
      LAYER M4 ;
        RECT  0 42 0.192 42.024 ;
    END
  END o[381]
  PIN o[382]
    DIRECTION OUTPUT ;
    USE SIGNAL ;
    PORT
      LAYER M4 ;
        RECT  0 42.096 0.192 42.12 ;
    END
  END o[382]
  PIN o[383]
    DIRECTION OUTPUT ;
    USE SIGNAL ;
    PORT
      LAYER M4 ;
        RECT  0 42.192 0.192 42.216 ;
    END
  END o[383]
  PIN o[384]
    DIRECTION OUTPUT ;
    USE SIGNAL ;
    PORT
      LAYER M4 ;
        RECT  0 42.288 0.192 42.312 ;
    END
  END o[384]
  PIN o[385]
    DIRECTION OUTPUT ;
    USE SIGNAL ;
    PORT
      LAYER M4 ;
        RECT  0 42.384 0.192 42.408 ;
    END
  END o[385]
  PIN o[386]
    DIRECTION OUTPUT ;
    USE SIGNAL ;
    PORT
      LAYER M4 ;
        RECT  0 42.528 0.192 42.552 ;
    END
  END o[386]
  PIN o[387]
    DIRECTION OUTPUT ;
    USE SIGNAL ;
    PORT
      LAYER M4 ;
        RECT  0 42.624 0.192 42.648 ;
    END
  END o[387]
  PIN o[388]
    DIRECTION OUTPUT ;
    USE SIGNAL ;
    PORT
      LAYER M4 ;
        RECT  0 42.72 0.192 42.744 ;
    END
  END o[388]
  PIN o[389]
    DIRECTION OUTPUT ;
    USE SIGNAL ;
    PORT
      LAYER M4 ;
        RECT  0 42.816 0.192 42.84 ;
    END
  END o[389]
  PIN o[38]
    DIRECTION OUTPUT ;
    USE SIGNAL ;
    PORT
      LAYER M4 ;
        RECT  0 6.192 0.192 6.216 ;
    END
  END o[38]
  PIN o[390]
    DIRECTION OUTPUT ;
    USE SIGNAL ;
    PORT
      LAYER M4 ;
        RECT  0 42.912 0.192 42.936 ;
    END
  END o[390]
  PIN o[391]
    DIRECTION OUTPUT ;
    USE SIGNAL ;
    PORT
      LAYER M4 ;
        RECT  0 43.008 0.192 43.032 ;
    END
  END o[391]
  PIN o[392]
    DIRECTION OUTPUT ;
    USE SIGNAL ;
    PORT
      LAYER M4 ;
        RECT  0 43.152 0.192 43.176 ;
    END
  END o[392]
  PIN o[393]
    DIRECTION OUTPUT ;
    USE SIGNAL ;
    PORT
      LAYER M4 ;
        RECT  0 43.248 0.192 43.272 ;
    END
  END o[393]
  PIN o[394]
    DIRECTION OUTPUT ;
    USE SIGNAL ;
    PORT
      LAYER M4 ;
        RECT  0 43.344 0.192 43.368 ;
    END
  END o[394]
  PIN o[395]
    DIRECTION OUTPUT ;
    USE SIGNAL ;
    PORT
      LAYER M4 ;
        RECT  0 43.44 0.192 43.464 ;
    END
  END o[395]
  PIN o[396]
    DIRECTION OUTPUT ;
    USE SIGNAL ;
    PORT
      LAYER M4 ;
        RECT  0 43.536 0.192 43.56 ;
    END
  END o[396]
  PIN o[397]
    DIRECTION OUTPUT ;
    USE SIGNAL ;
    PORT
      LAYER M4 ;
        RECT  0 43.68 0.192 43.704 ;
    END
  END o[397]
  PIN o[398]
    DIRECTION OUTPUT ;
    USE SIGNAL ;
    PORT
      LAYER M4 ;
        RECT  0 43.776 0.192 43.8 ;
    END
  END o[398]
  PIN o[399]
    DIRECTION OUTPUT ;
    USE SIGNAL ;
    PORT
      LAYER M4 ;
        RECT  0 43.872 0.192 43.896 ;
    END
  END o[399]
  PIN o[39]
    DIRECTION OUTPUT ;
    USE SIGNAL ;
    PORT
      LAYER M4 ;
        RECT  0 6.288 0.192 6.312 ;
    END
  END o[39]
  PIN o[3]
    DIRECTION OUTPUT ;
    USE SIGNAL ;
    PORT
      LAYER M4 ;
        RECT  0 2.544 0.192 2.568 ;
    END
  END o[3]
  PIN o[400]
    DIRECTION OUTPUT ;
    USE SIGNAL ;
    PORT
      LAYER M4 ;
        RECT  0 43.968 0.192 43.992 ;
    END
  END o[400]
  PIN o[401]
    DIRECTION OUTPUT ;
    USE SIGNAL ;
    PORT
      LAYER M4 ;
        RECT  0 44.064 0.192 44.088 ;
    END
  END o[401]
  PIN o[402]
    DIRECTION OUTPUT ;
    USE SIGNAL ;
    PORT
      LAYER M4 ;
        RECT  0 44.16 0.192 44.184 ;
    END
  END o[402]
  PIN o[403]
    DIRECTION OUTPUT ;
    USE SIGNAL ;
    PORT
      LAYER M4 ;
        RECT  0 44.304 0.192 44.328 ;
    END
  END o[403]
  PIN o[404]
    DIRECTION OUTPUT ;
    USE SIGNAL ;
    PORT
      LAYER M4 ;
        RECT  0 44.4 0.192 44.424 ;
    END
  END o[404]
  PIN o[405]
    DIRECTION OUTPUT ;
    USE SIGNAL ;
    PORT
      LAYER M4 ;
        RECT  0 44.496 0.192 44.52 ;
    END
  END o[405]
  PIN o[406]
    DIRECTION OUTPUT ;
    USE SIGNAL ;
    PORT
      LAYER M4 ;
        RECT  0 44.592 0.192 44.616 ;
    END
  END o[406]
  PIN o[407]
    DIRECTION OUTPUT ;
    USE SIGNAL ;
    PORT
      LAYER M4 ;
        RECT  0 44.688 0.192 44.712 ;
    END
  END o[407]
  PIN o[408]
    DIRECTION OUTPUT ;
    USE SIGNAL ;
    PORT
      LAYER M4 ;
        RECT  0 44.784 0.192 44.808 ;
    END
  END o[408]
  PIN o[409]
    DIRECTION OUTPUT ;
    USE SIGNAL ;
    PORT
      LAYER M4 ;
        RECT  0 44.928 0.192 44.952 ;
    END
  END o[409]
  PIN o[40]
    DIRECTION OUTPUT ;
    USE SIGNAL ;
    PORT
      LAYER M4 ;
        RECT  0 6.384 0.192 6.408 ;
    END
  END o[40]
  PIN o[410]
    DIRECTION OUTPUT ;
    USE SIGNAL ;
    PORT
      LAYER M4 ;
        RECT  0 45.024 0.192 45.048 ;
    END
  END o[410]
  PIN o[411]
    DIRECTION OUTPUT ;
    USE SIGNAL ;
    PORT
      LAYER M4 ;
        RECT  0 45.12 0.192 45.144 ;
    END
  END o[411]
  PIN o[412]
    DIRECTION OUTPUT ;
    USE SIGNAL ;
    PORT
      LAYER M4 ;
        RECT  0 45.216 0.192 45.24 ;
    END
  END o[412]
  PIN o[413]
    DIRECTION OUTPUT ;
    USE SIGNAL ;
    PORT
      LAYER M4 ;
        RECT  0 45.312 0.192 45.336 ;
    END
  END o[413]
  PIN o[414]
    DIRECTION OUTPUT ;
    USE SIGNAL ;
    PORT
      LAYER M4 ;
        RECT  0 45.408 0.192 45.432 ;
    END
  END o[414]
  PIN o[415]
    DIRECTION OUTPUT ;
    USE SIGNAL ;
    PORT
      LAYER M4 ;
        RECT  0 45.552 0.192 45.576 ;
    END
  END o[415]
  PIN o[416]
    DIRECTION OUTPUT ;
    USE SIGNAL ;
    PORT
      LAYER M4 ;
        RECT  0 45.648 0.192 45.672 ;
    END
  END o[416]
  PIN o[417]
    DIRECTION OUTPUT ;
    USE SIGNAL ;
    PORT
      LAYER M4 ;
        RECT  0 45.744 0.192 45.768 ;
    END
  END o[417]
  PIN o[418]
    DIRECTION OUTPUT ;
    USE SIGNAL ;
    PORT
      LAYER M4 ;
        RECT  0 45.84 0.192 45.864 ;
    END
  END o[418]
  PIN o[419]
    DIRECTION OUTPUT ;
    USE SIGNAL ;
    PORT
      LAYER M4 ;
        RECT  0 45.936 0.192 45.96 ;
    END
  END o[419]
  PIN o[41]
    DIRECTION OUTPUT ;
    USE SIGNAL ;
    PORT
      LAYER M4 ;
        RECT  0 6.48 0.192 6.504 ;
    END
  END o[41]
  PIN o[420]
    DIRECTION OUTPUT ;
    USE SIGNAL ;
    PORT
      LAYER M4 ;
        RECT  0 46.08 0.192 46.104 ;
    END
  END o[420]
  PIN o[421]
    DIRECTION OUTPUT ;
    USE SIGNAL ;
    PORT
      LAYER M4 ;
        RECT  0 46.176 0.192 46.2 ;
    END
  END o[421]
  PIN o[422]
    DIRECTION OUTPUT ;
    USE SIGNAL ;
    PORT
      LAYER M4 ;
        RECT  0 46.272 0.192 46.296 ;
    END
  END o[422]
  PIN o[423]
    DIRECTION OUTPUT ;
    USE SIGNAL ;
    PORT
      LAYER M4 ;
        RECT  0 46.368 0.192 46.392 ;
    END
  END o[423]
  PIN o[424]
    DIRECTION OUTPUT ;
    USE SIGNAL ;
    PORT
      LAYER M4 ;
        RECT  0 46.464 0.192 46.488 ;
    END
  END o[424]
  PIN o[425]
    DIRECTION OUTPUT ;
    USE SIGNAL ;
    PORT
      LAYER M4 ;
        RECT  0 46.56 0.192 46.584 ;
    END
  END o[425]
  PIN o[426]
    DIRECTION OUTPUT ;
    USE SIGNAL ;
    PORT
      LAYER M4 ;
        RECT  0 46.704 0.192 46.728 ;
    END
  END o[426]
  PIN o[427]
    DIRECTION OUTPUT ;
    USE SIGNAL ;
    PORT
      LAYER M4 ;
        RECT  0 46.8 0.192 46.824 ;
    END
  END o[427]
  PIN o[428]
    DIRECTION OUTPUT ;
    USE SIGNAL ;
    PORT
      LAYER M4 ;
        RECT  0 46.896 0.192 46.92 ;
    END
  END o[428]
  PIN o[429]
    DIRECTION OUTPUT ;
    USE SIGNAL ;
    PORT
      LAYER M4 ;
        RECT  0 46.992 0.192 47.016 ;
    END
  END o[429]
  PIN o[42]
    DIRECTION OUTPUT ;
    USE SIGNAL ;
    PORT
      LAYER M4 ;
        RECT  0 6.624 0.192 6.648 ;
    END
  END o[42]
  PIN o[430]
    DIRECTION OUTPUT ;
    USE SIGNAL ;
    PORT
      LAYER M4 ;
        RECT  0 47.088 0.192 47.112 ;
    END
  END o[430]
  PIN o[431]
    DIRECTION OUTPUT ;
    USE SIGNAL ;
    PORT
      LAYER M4 ;
        RECT  0 47.184 0.192 47.208 ;
    END
  END o[431]
  PIN o[432]
    DIRECTION OUTPUT ;
    USE SIGNAL ;
    PORT
      LAYER M4 ;
        RECT  0 47.328 0.192 47.352 ;
    END
  END o[432]
  PIN o[433]
    DIRECTION OUTPUT ;
    USE SIGNAL ;
    PORT
      LAYER M4 ;
        RECT  0 47.424 0.192 47.448 ;
    END
  END o[433]
  PIN o[434]
    DIRECTION OUTPUT ;
    USE SIGNAL ;
    PORT
      LAYER M4 ;
        RECT  0 47.52 0.192 47.544 ;
    END
  END o[434]
  PIN o[435]
    DIRECTION OUTPUT ;
    USE SIGNAL ;
    PORT
      LAYER M4 ;
        RECT  0 47.616 0.192 47.64 ;
    END
  END o[435]
  PIN o[436]
    DIRECTION OUTPUT ;
    USE SIGNAL ;
    PORT
      LAYER M4 ;
        RECT  0 47.712 0.192 47.736 ;
    END
  END o[436]
  PIN o[437]
    DIRECTION OUTPUT ;
    USE SIGNAL ;
    PORT
      LAYER M4 ;
        RECT  0 47.808 0.192 47.832 ;
    END
  END o[437]
  PIN o[438]
    DIRECTION OUTPUT ;
    USE SIGNAL ;
    PORT
      LAYER M4 ;
        RECT  0 47.952 0.192 47.976 ;
    END
  END o[438]
  PIN o[439]
    DIRECTION OUTPUT ;
    USE SIGNAL ;
    PORT
      LAYER M4 ;
        RECT  0 48.048 0.192 48.072 ;
    END
  END o[439]
  PIN o[43]
    DIRECTION OUTPUT ;
    USE SIGNAL ;
    PORT
      LAYER M4 ;
        RECT  0 6.72 0.192 6.744 ;
    END
  END o[43]
  PIN o[440]
    DIRECTION OUTPUT ;
    USE SIGNAL ;
    PORT
      LAYER M4 ;
        RECT  0 48.144 0.192 48.168 ;
    END
  END o[440]
  PIN o[441]
    DIRECTION OUTPUT ;
    USE SIGNAL ;
    PORT
      LAYER M4 ;
        RECT  0 48.24 0.192 48.264 ;
    END
  END o[441]
  PIN o[442]
    DIRECTION OUTPUT ;
    USE SIGNAL ;
    PORT
      LAYER M4 ;
        RECT  0 48.336 0.192 48.36 ;
    END
  END o[442]
  PIN o[443]
    DIRECTION OUTPUT ;
    USE SIGNAL ;
    PORT
      LAYER M4 ;
        RECT  0 48.48 0.192 48.504 ;
    END
  END o[443]
  PIN o[444]
    DIRECTION OUTPUT ;
    USE SIGNAL ;
    PORT
      LAYER M4 ;
        RECT  0 48.576 0.192 48.6 ;
    END
  END o[444]
  PIN o[445]
    DIRECTION OUTPUT ;
    USE SIGNAL ;
    PORT
      LAYER M4 ;
        RECT  0 48.672 0.192 48.696 ;
    END
  END o[445]
  PIN o[446]
    DIRECTION OUTPUT ;
    USE SIGNAL ;
    PORT
      LAYER M4 ;
        RECT  0 48.768 0.192 48.792 ;
    END
  END o[446]
  PIN o[447]
    DIRECTION OUTPUT ;
    USE SIGNAL ;
    PORT
      LAYER M4 ;
        RECT  0 48.864 0.192 48.888 ;
    END
  END o[447]
  PIN o[448]
    DIRECTION OUTPUT ;
    USE SIGNAL ;
    PORT
      LAYER M4 ;
        RECT  0 48.96 0.192 48.984 ;
    END
  END o[448]
  PIN o[449]
    DIRECTION OUTPUT ;
    USE SIGNAL ;
    PORT
      LAYER M4 ;
        RECT  0 49.104 0.192 49.128 ;
    END
  END o[449]
  PIN o[44]
    DIRECTION OUTPUT ;
    USE SIGNAL ;
    PORT
      LAYER M4 ;
        RECT  0 6.816 0.192 6.84 ;
    END
  END o[44]
  PIN o[450]
    DIRECTION OUTPUT ;
    USE SIGNAL ;
    PORT
      LAYER M4 ;
        RECT  0 49.2 0.192 49.224 ;
    END
  END o[450]
  PIN o[451]
    DIRECTION OUTPUT ;
    USE SIGNAL ;
    PORT
      LAYER M4 ;
        RECT  0 49.296 0.192 49.32 ;
    END
  END o[451]
  PIN o[452]
    DIRECTION OUTPUT ;
    USE SIGNAL ;
    PORT
      LAYER M4 ;
        RECT  0 49.392 0.192 49.416 ;
    END
  END o[452]
  PIN o[453]
    DIRECTION OUTPUT ;
    USE SIGNAL ;
    PORT
      LAYER M4 ;
        RECT  0 49.488 0.192 49.512 ;
    END
  END o[453]
  PIN o[454]
    DIRECTION OUTPUT ;
    USE SIGNAL ;
    PORT
      LAYER M4 ;
        RECT  0 49.584 0.192 49.608 ;
    END
  END o[454]
  PIN o[455]
    DIRECTION OUTPUT ;
    USE SIGNAL ;
    PORT
      LAYER M4 ;
        RECT  0 49.728 0.192 49.752 ;
    END
  END o[455]
  PIN o[456]
    DIRECTION OUTPUT ;
    USE SIGNAL ;
    PORT
      LAYER M4 ;
        RECT  0 49.824 0.192 49.848 ;
    END
  END o[456]
  PIN o[457]
    DIRECTION OUTPUT ;
    USE SIGNAL ;
    PORT
      LAYER M4 ;
        RECT  0 49.92 0.192 49.944 ;
    END
  END o[457]
  PIN o[458]
    DIRECTION OUTPUT ;
    USE SIGNAL ;
    PORT
      LAYER M4 ;
        RECT  0 50.016 0.192 50.04 ;
    END
  END o[458]
  PIN o[459]
    DIRECTION OUTPUT ;
    USE SIGNAL ;
    PORT
      LAYER M4 ;
        RECT  0 50.112 0.192 50.136 ;
    END
  END o[459]
  PIN o[45]
    DIRECTION OUTPUT ;
    USE SIGNAL ;
    PORT
      LAYER M4 ;
        RECT  0 6.912 0.192 6.936 ;
    END
  END o[45]
  PIN o[460]
    DIRECTION OUTPUT ;
    USE SIGNAL ;
    PORT
      LAYER M4 ;
        RECT  0 50.208 0.192 50.232 ;
    END
  END o[460]
  PIN o[461]
    DIRECTION OUTPUT ;
    USE SIGNAL ;
    PORT
      LAYER M4 ;
        RECT  0 50.352 0.192 50.376 ;
    END
  END o[461]
  PIN o[462]
    DIRECTION OUTPUT ;
    USE SIGNAL ;
    PORT
      LAYER M4 ;
        RECT  0 50.448 0.192 50.472 ;
    END
  END o[462]
  PIN o[463]
    DIRECTION OUTPUT ;
    USE SIGNAL ;
    PORT
      LAYER M4 ;
        RECT  0 50.544 0.192 50.568 ;
    END
  END o[463]
  PIN o[464]
    DIRECTION OUTPUT ;
    USE SIGNAL ;
    PORT
      LAYER M4 ;
        RECT  0 50.64 0.192 50.664 ;
    END
  END o[464]
  PIN o[465]
    DIRECTION OUTPUT ;
    USE SIGNAL ;
    PORT
      LAYER M4 ;
        RECT  0 50.736 0.192 50.76 ;
    END
  END o[465]
  PIN o[466]
    DIRECTION OUTPUT ;
    USE SIGNAL ;
    PORT
      LAYER M4 ;
        RECT  0 50.88 0.192 50.904 ;
    END
  END o[466]
  PIN o[467]
    DIRECTION OUTPUT ;
    USE SIGNAL ;
    PORT
      LAYER M4 ;
        RECT  0 50.976 0.192 51 ;
    END
  END o[467]
  PIN o[468]
    DIRECTION OUTPUT ;
    USE SIGNAL ;
    PORT
      LAYER M4 ;
        RECT  0 51.072 0.192 51.096 ;
    END
  END o[468]
  PIN o[469]
    DIRECTION OUTPUT ;
    USE SIGNAL ;
    PORT
      LAYER M4 ;
        RECT  0 51.168 0.192 51.192 ;
    END
  END o[469]
  PIN o[46]
    DIRECTION OUTPUT ;
    USE SIGNAL ;
    PORT
      LAYER M4 ;
        RECT  0 7.008 0.192 7.032 ;
    END
  END o[46]
  PIN o[470]
    DIRECTION OUTPUT ;
    USE SIGNAL ;
    PORT
      LAYER M4 ;
        RECT  0 51.264 0.192 51.288 ;
    END
  END o[470]
  PIN o[471]
    DIRECTION OUTPUT ;
    USE SIGNAL ;
    PORT
      LAYER M4 ;
        RECT  0 51.36 0.192 51.384 ;
    END
  END o[471]
  PIN o[472]
    DIRECTION OUTPUT ;
    USE SIGNAL ;
    PORT
      LAYER M4 ;
        RECT  0 51.504 0.192 51.528 ;
    END
  END o[472]
  PIN o[473]
    DIRECTION OUTPUT ;
    USE SIGNAL ;
    PORT
      LAYER M4 ;
        RECT  0 51.6 0.192 51.624 ;
    END
  END o[473]
  PIN o[474]
    DIRECTION OUTPUT ;
    USE SIGNAL ;
    PORT
      LAYER M4 ;
        RECT  0 51.696 0.192 51.72 ;
    END
  END o[474]
  PIN o[475]
    DIRECTION OUTPUT ;
    USE SIGNAL ;
    PORT
      LAYER M4 ;
        RECT  0 51.792 0.192 51.816 ;
    END
  END o[475]
  PIN o[476]
    DIRECTION OUTPUT ;
    USE SIGNAL ;
    PORT
      LAYER M4 ;
        RECT  0 51.888 0.192 51.912 ;
    END
  END o[476]
  PIN o[477]
    DIRECTION OUTPUT ;
    USE SIGNAL ;
    PORT
      LAYER M4 ;
        RECT  0 51.984 0.192 52.008 ;
    END
  END o[477]
  PIN o[478]
    DIRECTION OUTPUT ;
    USE SIGNAL ;
    PORT
      LAYER M4 ;
        RECT  0 52.128 0.192 52.152 ;
    END
  END o[478]
  PIN o[479]
    DIRECTION OUTPUT ;
    USE SIGNAL ;
    PORT
      LAYER M4 ;
        RECT  0 52.224 0.192 52.248 ;
    END
  END o[479]
  PIN o[47]
    DIRECTION OUTPUT ;
    USE SIGNAL ;
    PORT
      LAYER M4 ;
        RECT  0 7.152 0.192 7.176 ;
    END
  END o[47]
  PIN o[480]
    DIRECTION OUTPUT ;
    USE SIGNAL ;
    PORT
      LAYER M4 ;
        RECT  0 52.32 0.192 52.344 ;
    END
  END o[480]
  PIN o[481]
    DIRECTION OUTPUT ;
    USE SIGNAL ;
    PORT
      LAYER M4 ;
        RECT  0 52.416 0.192 52.44 ;
    END
  END o[481]
  PIN o[482]
    DIRECTION OUTPUT ;
    USE SIGNAL ;
    PORT
      LAYER M4 ;
        RECT  0 52.512 0.192 52.536 ;
    END
  END o[482]
  PIN o[483]
    DIRECTION OUTPUT ;
    USE SIGNAL ;
    PORT
      LAYER M4 ;
        RECT  0 52.608 0.192 52.632 ;
    END
  END o[483]
  PIN o[484]
    DIRECTION OUTPUT ;
    USE SIGNAL ;
    PORT
      LAYER M4 ;
        RECT  0 52.752 0.192 52.776 ;
    END
  END o[484]
  PIN o[485]
    DIRECTION OUTPUT ;
    USE SIGNAL ;
    PORT
      LAYER M4 ;
        RECT  0 52.848 0.192 52.872 ;
    END
  END o[485]
  PIN o[486]
    DIRECTION OUTPUT ;
    USE SIGNAL ;
    PORT
      LAYER M4 ;
        RECT  0 52.944 0.192 52.968 ;
    END
  END o[486]
  PIN o[487]
    DIRECTION OUTPUT ;
    USE SIGNAL ;
    PORT
      LAYER M4 ;
        RECT  0 53.04 0.192 53.064 ;
    END
  END o[487]
  PIN o[488]
    DIRECTION OUTPUT ;
    USE SIGNAL ;
    PORT
      LAYER M4 ;
        RECT  0 53.136 0.192 53.16 ;
    END
  END o[488]
  PIN o[489]
    DIRECTION OUTPUT ;
    USE SIGNAL ;
    PORT
      LAYER M4 ;
        RECT  0 53.28 0.192 53.304 ;
    END
  END o[489]
  PIN o[48]
    DIRECTION OUTPUT ;
    USE SIGNAL ;
    PORT
      LAYER M4 ;
        RECT  0 7.248 0.192 7.272 ;
    END
  END o[48]
  PIN o[490]
    DIRECTION OUTPUT ;
    USE SIGNAL ;
    PORT
      LAYER M4 ;
        RECT  0 53.376 0.192 53.4 ;
    END
  END o[490]
  PIN o[491]
    DIRECTION OUTPUT ;
    USE SIGNAL ;
    PORT
      LAYER M4 ;
        RECT  0 53.472 0.192 53.496 ;
    END
  END o[491]
  PIN o[492]
    DIRECTION OUTPUT ;
    USE SIGNAL ;
    PORT
      LAYER M4 ;
        RECT  0 53.568 0.192 53.592 ;
    END
  END o[492]
  PIN o[493]
    DIRECTION OUTPUT ;
    USE SIGNAL ;
    PORT
      LAYER M4 ;
        RECT  0 53.664 0.192 53.688 ;
    END
  END o[493]
  PIN o[494]
    DIRECTION OUTPUT ;
    USE SIGNAL ;
    PORT
      LAYER M4 ;
        RECT  0 53.76 0.192 53.784 ;
    END
  END o[494]
  PIN o[495]
    DIRECTION OUTPUT ;
    USE SIGNAL ;
    PORT
      LAYER M4 ;
        RECT  0 53.904 0.192 53.928 ;
    END
  END o[495]
  PIN o[496]
    DIRECTION OUTPUT ;
    USE SIGNAL ;
    PORT
      LAYER M4 ;
        RECT  0 54 0.192 54.024 ;
    END
  END o[496]
  PIN o[497]
    DIRECTION OUTPUT ;
    USE SIGNAL ;
    PORT
      LAYER M4 ;
        RECT  0 54.096 0.192 54.12 ;
    END
  END o[497]
  PIN o[498]
    DIRECTION OUTPUT ;
    USE SIGNAL ;
    PORT
      LAYER M4 ;
        RECT  0 54.192 0.192 54.216 ;
    END
  END o[498]
  PIN o[499]
    DIRECTION OUTPUT ;
    USE SIGNAL ;
    PORT
      LAYER M4 ;
        RECT  0 54.288 0.192 54.312 ;
    END
  END o[499]
  PIN o[49]
    DIRECTION OUTPUT ;
    USE SIGNAL ;
    PORT
      LAYER M4 ;
        RECT  0 7.344 0.192 7.368 ;
    END
  END o[49]
  PIN o[4]
    DIRECTION OUTPUT ;
    USE SIGNAL ;
    PORT
      LAYER M4 ;
        RECT  0 2.64 0.192 2.664 ;
    END
  END o[4]
  PIN o[500]
    DIRECTION OUTPUT ;
    USE SIGNAL ;
    PORT
      LAYER M4 ;
        RECT  0 54.384 0.192 54.408 ;
    END
  END o[500]
  PIN o[501]
    DIRECTION OUTPUT ;
    USE SIGNAL ;
    PORT
      LAYER M4 ;
        RECT  0 54.528 0.192 54.552 ;
    END
  END o[501]
  PIN o[502]
    DIRECTION OUTPUT ;
    USE SIGNAL ;
    PORT
      LAYER M4 ;
        RECT  0 54.624 0.192 54.648 ;
    END
  END o[502]
  PIN o[503]
    DIRECTION OUTPUT ;
    USE SIGNAL ;
    PORT
      LAYER M4 ;
        RECT  0 54.72 0.192 54.744 ;
    END
  END o[503]
  PIN o[504]
    DIRECTION OUTPUT ;
    USE SIGNAL ;
    PORT
      LAYER M4 ;
        RECT  0 54.816 0.192 54.84 ;
    END
  END o[504]
  PIN o[505]
    DIRECTION OUTPUT ;
    USE SIGNAL ;
    PORT
      LAYER M4 ;
        RECT  0 54.912 0.192 54.936 ;
    END
  END o[505]
  PIN o[506]
    DIRECTION OUTPUT ;
    USE SIGNAL ;
    PORT
      LAYER M4 ;
        RECT  0 55.008 0.192 55.032 ;
    END
  END o[506]
  PIN o[507]
    DIRECTION OUTPUT ;
    USE SIGNAL ;
    PORT
      LAYER M4 ;
        RECT  0 55.152 0.192 55.176 ;
    END
  END o[507]
  PIN o[508]
    DIRECTION OUTPUT ;
    USE SIGNAL ;
    PORT
      LAYER M4 ;
        RECT  0 55.248 0.192 55.272 ;
    END
  END o[508]
  PIN o[509]
    DIRECTION OUTPUT ;
    USE SIGNAL ;
    PORT
      LAYER M4 ;
        RECT  0 55.344 0.192 55.368 ;
    END
  END o[509]
  PIN o[50]
    DIRECTION OUTPUT ;
    USE SIGNAL ;
    PORT
      LAYER M4 ;
        RECT  0 7.44 0.192 7.464 ;
    END
  END o[50]
  PIN o[510]
    DIRECTION OUTPUT ;
    USE SIGNAL ;
    PORT
      LAYER M4 ;
        RECT  0 55.44 0.192 55.464 ;
    END
  END o[510]
  PIN o[511]
    DIRECTION OUTPUT ;
    USE SIGNAL ;
    PORT
      LAYER M4 ;
        RECT  0 55.536 0.192 55.56 ;
    END
  END o[511]
  PIN o[512]
    DIRECTION OUTPUT ;
    USE SIGNAL ;
    PORT
      LAYER M4 ;
        RECT  0 55.68 0.192 55.704 ;
    END
  END o[512]
  PIN o[513]
    DIRECTION OUTPUT ;
    USE SIGNAL ;
    PORT
      LAYER M4 ;
        RECT  0 55.776 0.192 55.8 ;
    END
  END o[513]
  PIN o[514]
    DIRECTION OUTPUT ;
    USE SIGNAL ;
    PORT
      LAYER M4 ;
        RECT  0 55.872 0.192 55.896 ;
    END
  END o[514]
  PIN o[515]
    DIRECTION OUTPUT ;
    USE SIGNAL ;
    PORT
      LAYER M4 ;
        RECT  0 55.968 0.192 55.992 ;
    END
  END o[515]
  PIN o[516]
    DIRECTION OUTPUT ;
    USE SIGNAL ;
    PORT
      LAYER M4 ;
        RECT  0 56.064 0.192 56.088 ;
    END
  END o[516]
  PIN o[517]
    DIRECTION OUTPUT ;
    USE SIGNAL ;
    PORT
      LAYER M4 ;
        RECT  0 56.16 0.192 56.184 ;
    END
  END o[517]
  PIN o[518]
    DIRECTION OUTPUT ;
    USE SIGNAL ;
    PORT
      LAYER M4 ;
        RECT  0 56.304 0.192 56.328 ;
    END
  END o[518]
  PIN o[519]
    DIRECTION OUTPUT ;
    USE SIGNAL ;
    PORT
      LAYER M4 ;
        RECT  0 56.4 0.192 56.424 ;
    END
  END o[519]
  PIN o[51]
    DIRECTION OUTPUT ;
    USE SIGNAL ;
    PORT
      LAYER M4 ;
        RECT  0 7.536 0.192 7.56 ;
    END
  END o[51]
  PIN o[520]
    DIRECTION OUTPUT ;
    USE SIGNAL ;
    PORT
      LAYER M4 ;
        RECT  0 56.496 0.192 56.52 ;
    END
  END o[520]
  PIN o[521]
    DIRECTION OUTPUT ;
    USE SIGNAL ;
    PORT
      LAYER M4 ;
        RECT  0 56.592 0.192 56.616 ;
    END
  END o[521]
  PIN o[522]
    DIRECTION OUTPUT ;
    USE SIGNAL ;
    PORT
      LAYER M4 ;
        RECT  0 56.688 0.192 56.712 ;
    END
  END o[522]
  PIN o[523]
    DIRECTION OUTPUT ;
    USE SIGNAL ;
    PORT
      LAYER M4 ;
        RECT  0 56.784 0.192 56.808 ;
    END
  END o[523]
  PIN o[524]
    DIRECTION OUTPUT ;
    USE SIGNAL ;
    PORT
      LAYER M4 ;
        RECT  0 56.928 0.192 56.952 ;
    END
  END o[524]
  PIN o[525]
    DIRECTION OUTPUT ;
    USE SIGNAL ;
    PORT
      LAYER M4 ;
        RECT  0 57.024 0.192 57.048 ;
    END
  END o[525]
  PIN o[526]
    DIRECTION OUTPUT ;
    USE SIGNAL ;
    PORT
      LAYER M4 ;
        RECT  0 57.12 0.192 57.144 ;
    END
  END o[526]
  PIN o[527]
    DIRECTION OUTPUT ;
    USE SIGNAL ;
    PORT
      LAYER M4 ;
        RECT  0 57.216 0.192 57.24 ;
    END
  END o[527]
  PIN o[528]
    DIRECTION OUTPUT ;
    USE SIGNAL ;
    PORT
      LAYER M4 ;
        RECT  0 57.312 0.192 57.336 ;
    END
  END o[528]
  PIN o[529]
    DIRECTION OUTPUT ;
    USE SIGNAL ;
    PORT
      LAYER M4 ;
        RECT  0 57.456 0.192 57.48 ;
    END
  END o[529]
  PIN o[52]
    DIRECTION OUTPUT ;
    USE SIGNAL ;
    PORT
      LAYER M4 ;
        RECT  0 7.632 0.192 7.656 ;
    END
  END o[52]
  PIN o[530]
    DIRECTION OUTPUT ;
    USE SIGNAL ;
    PORT
      LAYER M4 ;
        RECT  0 57.552 0.192 57.576 ;
    END
  END o[530]
  PIN o[531]
    DIRECTION OUTPUT ;
    USE SIGNAL ;
    PORT
      LAYER M4 ;
        RECT  0 57.648 0.192 57.672 ;
    END
  END o[531]
  PIN o[532]
    DIRECTION OUTPUT ;
    USE SIGNAL ;
    PORT
      LAYER M4 ;
        RECT  0 57.744 0.192 57.768 ;
    END
  END o[532]
  PIN o[533]
    DIRECTION OUTPUT ;
    USE SIGNAL ;
    PORT
      LAYER M4 ;
        RECT  0 57.84 0.192 57.864 ;
    END
  END o[533]
  PIN o[534]
    DIRECTION OUTPUT ;
    USE SIGNAL ;
    PORT
      LAYER M4 ;
        RECT  0 57.936 0.192 57.96 ;
    END
  END o[534]
  PIN o[535]
    DIRECTION OUTPUT ;
    USE SIGNAL ;
    PORT
      LAYER M4 ;
        RECT  0 58.08 0.192 58.104 ;
    END
  END o[535]
  PIN o[536]
    DIRECTION OUTPUT ;
    USE SIGNAL ;
    PORT
      LAYER M4 ;
        RECT  0 58.176 0.192 58.2 ;
    END
  END o[536]
  PIN o[537]
    DIRECTION OUTPUT ;
    USE SIGNAL ;
    PORT
      LAYER M4 ;
        RECT  0 58.272 0.192 58.296 ;
    END
  END o[537]
  PIN o[538]
    DIRECTION OUTPUT ;
    USE SIGNAL ;
    PORT
      LAYER M4 ;
        RECT  0 58.368 0.192 58.392 ;
    END
  END o[538]
  PIN o[539]
    DIRECTION OUTPUT ;
    USE SIGNAL ;
    PORT
      LAYER M4 ;
        RECT  0 58.464 0.192 58.488 ;
    END
  END o[539]
  PIN o[53]
    DIRECTION OUTPUT ;
    USE SIGNAL ;
    PORT
      LAYER M4 ;
        RECT  0 7.776 0.192 7.8 ;
    END
  END o[53]
  PIN o[540]
    DIRECTION OUTPUT ;
    USE SIGNAL ;
    PORT
      LAYER M4 ;
        RECT  0 58.56 0.192 58.584 ;
    END
  END o[540]
  PIN o[541]
    DIRECTION OUTPUT ;
    USE SIGNAL ;
    PORT
      LAYER M4 ;
        RECT  0 58.704 0.192 58.728 ;
    END
  END o[541]
  PIN o[542]
    DIRECTION OUTPUT ;
    USE SIGNAL ;
    PORT
      LAYER M4 ;
        RECT  0 58.8 0.192 58.824 ;
    END
  END o[542]
  PIN o[543]
    DIRECTION OUTPUT ;
    USE SIGNAL ;
    PORT
      LAYER M4 ;
        RECT  0 58.896 0.192 58.92 ;
    END
  END o[543]
  PIN o[544]
    DIRECTION OUTPUT ;
    USE SIGNAL ;
    PORT
      LAYER M4 ;
        RECT  0 58.992 0.192 59.016 ;
    END
  END o[544]
  PIN o[545]
    DIRECTION OUTPUT ;
    USE SIGNAL ;
    PORT
      LAYER M4 ;
        RECT  0 59.088 0.192 59.112 ;
    END
  END o[545]
  PIN o[546]
    DIRECTION OUTPUT ;
    USE SIGNAL ;
    PORT
      LAYER M4 ;
        RECT  0 59.184 0.192 59.208 ;
    END
  END o[546]
  PIN o[547]
    DIRECTION OUTPUT ;
    USE SIGNAL ;
    PORT
      LAYER M4 ;
        RECT  0 59.328 0.192 59.352 ;
    END
  END o[547]
  PIN o[548]
    DIRECTION OUTPUT ;
    USE SIGNAL ;
    PORT
      LAYER M4 ;
        RECT  0 59.424 0.192 59.448 ;
    END
  END o[548]
  PIN o[549]
    DIRECTION OUTPUT ;
    USE SIGNAL ;
    PORT
      LAYER M4 ;
        RECT  0 59.52 0.192 59.544 ;
    END
  END o[549]
  PIN o[54]
    DIRECTION OUTPUT ;
    USE SIGNAL ;
    PORT
      LAYER M4 ;
        RECT  0 7.872 0.192 7.896 ;
    END
  END o[54]
  PIN o[550]
    DIRECTION OUTPUT ;
    USE SIGNAL ;
    PORT
      LAYER M4 ;
        RECT  0 59.616 0.192 59.64 ;
    END
  END o[550]
  PIN o[551]
    DIRECTION OUTPUT ;
    USE SIGNAL ;
    PORT
      LAYER M4 ;
        RECT  0 59.712 0.192 59.736 ;
    END
  END o[551]
  PIN o[552]
    DIRECTION OUTPUT ;
    USE SIGNAL ;
    PORT
      LAYER M4 ;
        RECT  0 59.856 0.192 59.88 ;
    END
  END o[552]
  PIN o[553]
    DIRECTION OUTPUT ;
    USE SIGNAL ;
    PORT
      LAYER M4 ;
        RECT  0 59.952 0.192 59.976 ;
    END
  END o[553]
  PIN o[554]
    DIRECTION OUTPUT ;
    USE SIGNAL ;
    PORT
      LAYER M4 ;
        RECT  0 60.048 0.192 60.072 ;
    END
  END o[554]
  PIN o[555]
    DIRECTION OUTPUT ;
    USE SIGNAL ;
    PORT
      LAYER M4 ;
        RECT  0 60.144 0.192 60.168 ;
    END
  END o[555]
  PIN o[556]
    DIRECTION OUTPUT ;
    USE SIGNAL ;
    PORT
      LAYER M4 ;
        RECT  0 60.24 0.192 60.264 ;
    END
  END o[556]
  PIN o[557]
    DIRECTION OUTPUT ;
    USE SIGNAL ;
    PORT
      LAYER M4 ;
        RECT  0 60.336 0.192 60.36 ;
    END
  END o[557]
  PIN o[558]
    DIRECTION OUTPUT ;
    USE SIGNAL ;
    PORT
      LAYER M4 ;
        RECT  0 60.48 0.192 60.504 ;
    END
  END o[558]
  PIN o[559]
    DIRECTION OUTPUT ;
    USE SIGNAL ;
    PORT
      LAYER M4 ;
        RECT  0 60.576 0.192 60.6 ;
    END
  END o[559]
  PIN o[55]
    DIRECTION OUTPUT ;
    USE SIGNAL ;
    PORT
      LAYER M4 ;
        RECT  0 7.968 0.192 7.992 ;
    END
  END o[55]
  PIN o[560]
    DIRECTION OUTPUT ;
    USE SIGNAL ;
    PORT
      LAYER M4 ;
        RECT  0 60.672 0.192 60.696 ;
    END
  END o[560]
  PIN o[561]
    DIRECTION OUTPUT ;
    USE SIGNAL ;
    PORT
      LAYER M4 ;
        RECT  0 60.768 0.192 60.792 ;
    END
  END o[561]
  PIN o[562]
    DIRECTION OUTPUT ;
    USE SIGNAL ;
    PORT
      LAYER M4 ;
        RECT  0 60.864 0.192 60.888 ;
    END
  END o[562]
  PIN o[563]
    DIRECTION OUTPUT ;
    USE SIGNAL ;
    PORT
      LAYER M4 ;
        RECT  0 60.96 0.192 60.984 ;
    END
  END o[563]
  PIN o[564]
    DIRECTION OUTPUT ;
    USE SIGNAL ;
    PORT
      LAYER M4 ;
        RECT  0 61.104 0.192 61.128 ;
    END
  END o[564]
  PIN o[565]
    DIRECTION OUTPUT ;
    USE SIGNAL ;
    PORT
      LAYER M4 ;
        RECT  0 61.2 0.192 61.224 ;
    END
  END o[565]
  PIN o[566]
    DIRECTION OUTPUT ;
    USE SIGNAL ;
    PORT
      LAYER M4 ;
        RECT  0 61.296 0.192 61.32 ;
    END
  END o[566]
  PIN o[567]
    DIRECTION OUTPUT ;
    USE SIGNAL ;
    PORT
      LAYER M4 ;
        RECT  0 61.392 0.192 61.416 ;
    END
  END o[567]
  PIN o[568]
    DIRECTION OUTPUT ;
    USE SIGNAL ;
    PORT
      LAYER M4 ;
        RECT  0 61.488 0.192 61.512 ;
    END
  END o[568]
  PIN o[569]
    DIRECTION OUTPUT ;
    USE SIGNAL ;
    PORT
      LAYER M4 ;
        RECT  0 61.584 0.192 61.608 ;
    END
  END o[569]
  PIN o[56]
    DIRECTION OUTPUT ;
    USE SIGNAL ;
    PORT
      LAYER M4 ;
        RECT  0 8.064 0.192 8.088 ;
    END
  END o[56]
  PIN o[570]
    DIRECTION OUTPUT ;
    USE SIGNAL ;
    PORT
      LAYER M4 ;
        RECT  0 61.728 0.192 61.752 ;
    END
  END o[570]
  PIN o[571]
    DIRECTION OUTPUT ;
    USE SIGNAL ;
    PORT
      LAYER M4 ;
        RECT  0 61.824 0.192 61.848 ;
    END
  END o[571]
  PIN o[572]
    DIRECTION OUTPUT ;
    USE SIGNAL ;
    PORT
      LAYER M4 ;
        RECT  0 61.92 0.192 61.944 ;
    END
  END o[572]
  PIN o[573]
    DIRECTION OUTPUT ;
    USE SIGNAL ;
    PORT
      LAYER M4 ;
        RECT  0 62.016 0.192 62.04 ;
    END
  END o[573]
  PIN o[574]
    DIRECTION OUTPUT ;
    USE SIGNAL ;
    PORT
      LAYER M4 ;
        RECT  0 62.112 0.192 62.136 ;
    END
  END o[574]
  PIN o[575]
    DIRECTION OUTPUT ;
    USE SIGNAL ;
    PORT
      LAYER M4 ;
        RECT  0 62.256 0.192 62.28 ;
    END
  END o[575]
  PIN o[576]
    DIRECTION OUTPUT ;
    USE SIGNAL ;
    PORT
      LAYER M4 ;
        RECT  0 62.352 0.192 62.376 ;
    END
  END o[576]
  PIN o[577]
    DIRECTION OUTPUT ;
    USE SIGNAL ;
    PORT
      LAYER M4 ;
        RECT  0 62.448 0.192 62.472 ;
    END
  END o[577]
  PIN o[578]
    DIRECTION OUTPUT ;
    USE SIGNAL ;
    PORT
      LAYER M4 ;
        RECT  0 62.544 0.192 62.568 ;
    END
  END o[578]
  PIN o[579]
    DIRECTION OUTPUT ;
    USE SIGNAL ;
    PORT
      LAYER M4 ;
        RECT  0 62.64 0.192 62.664 ;
    END
  END o[579]
  PIN o[57]
    DIRECTION OUTPUT ;
    USE SIGNAL ;
    PORT
      LAYER M4 ;
        RECT  0 8.16 0.192 8.184 ;
    END
  END o[57]
  PIN o[580]
    DIRECTION OUTPUT ;
    USE SIGNAL ;
    PORT
      LAYER M4 ;
        RECT  0 62.736 0.192 62.76 ;
    END
  END o[580]
  PIN o[581]
    DIRECTION OUTPUT ;
    USE SIGNAL ;
    PORT
      LAYER M4 ;
        RECT  0 62.88 0.192 62.904 ;
    END
  END o[581]
  PIN o[582]
    DIRECTION OUTPUT ;
    USE SIGNAL ;
    PORT
      LAYER M4 ;
        RECT  0 62.976 0.192 63 ;
    END
  END o[582]
  PIN o[583]
    DIRECTION OUTPUT ;
    USE SIGNAL ;
    PORT
      LAYER M4 ;
        RECT  0 63.072 0.192 63.096 ;
    END
  END o[583]
  PIN o[584]
    DIRECTION OUTPUT ;
    USE SIGNAL ;
    PORT
      LAYER M4 ;
        RECT  0 63.168 0.192 63.192 ;
    END
  END o[584]
  PIN o[585]
    DIRECTION OUTPUT ;
    USE SIGNAL ;
    PORT
      LAYER M4 ;
        RECT  0 63.264 0.192 63.288 ;
    END
  END o[585]
  PIN o[586]
    DIRECTION OUTPUT ;
    USE SIGNAL ;
    PORT
      LAYER M4 ;
        RECT  0 63.36 0.192 63.384 ;
    END
  END o[586]
  PIN o[587]
    DIRECTION OUTPUT ;
    USE SIGNAL ;
    PORT
      LAYER M4 ;
        RECT  0 63.504 0.192 63.528 ;
    END
  END o[587]
  PIN o[588]
    DIRECTION OUTPUT ;
    USE SIGNAL ;
    PORT
      LAYER M4 ;
        RECT  0 63.6 0.192 63.624 ;
    END
  END o[588]
  PIN o[589]
    DIRECTION OUTPUT ;
    USE SIGNAL ;
    PORT
      LAYER M4 ;
        RECT  0 63.696 0.192 63.72 ;
    END
  END o[589]
  PIN o[58]
    DIRECTION OUTPUT ;
    USE SIGNAL ;
    PORT
      LAYER M4 ;
        RECT  0 8.256 0.192 8.28 ;
    END
  END o[58]
  PIN o[590]
    DIRECTION OUTPUT ;
    USE SIGNAL ;
    PORT
      LAYER M4 ;
        RECT  0 63.792 0.192 63.816 ;
    END
  END o[590]
  PIN o[591]
    DIRECTION OUTPUT ;
    USE SIGNAL ;
    PORT
      LAYER M4 ;
        RECT  0 63.888 0.192 63.912 ;
    END
  END o[591]
  PIN o[592]
    DIRECTION OUTPUT ;
    USE SIGNAL ;
    PORT
      LAYER M4 ;
        RECT  0 63.984 0.192 64.008 ;
    END
  END o[592]
  PIN o[593]
    DIRECTION OUTPUT ;
    USE SIGNAL ;
    PORT
      LAYER M4 ;
        RECT  0 64.128 0.192 64.152 ;
    END
  END o[593]
  PIN o[594]
    DIRECTION OUTPUT ;
    USE SIGNAL ;
    PORT
      LAYER M4 ;
        RECT  0 64.224 0.192 64.248 ;
    END
  END o[594]
  PIN o[595]
    DIRECTION OUTPUT ;
    USE SIGNAL ;
    PORT
      LAYER M4 ;
        RECT  0 64.32 0.192 64.344 ;
    END
  END o[595]
  PIN o[596]
    DIRECTION OUTPUT ;
    USE SIGNAL ;
    PORT
      LAYER M4 ;
        RECT  0 64.416 0.192 64.44 ;
    END
  END o[596]
  PIN o[597]
    DIRECTION OUTPUT ;
    USE SIGNAL ;
    PORT
      LAYER M4 ;
        RECT  0 64.512 0.192 64.536 ;
    END
  END o[597]
  PIN o[598]
    DIRECTION OUTPUT ;
    USE SIGNAL ;
    PORT
      LAYER M4 ;
        RECT  0 64.656 0.192 64.68 ;
    END
  END o[598]
  PIN o[599]
    DIRECTION OUTPUT ;
    USE SIGNAL ;
    PORT
      LAYER M4 ;
        RECT  0 64.752 0.192 64.776 ;
    END
  END o[599]
  PIN o[59]
    DIRECTION OUTPUT ;
    USE SIGNAL ;
    PORT
      LAYER M4 ;
        RECT  0 8.4 0.192 8.424 ;
    END
  END o[59]
  PIN o[5]
    DIRECTION OUTPUT ;
    USE SIGNAL ;
    PORT
      LAYER M4 ;
        RECT  0 2.736 0.192 2.76 ;
    END
  END o[5]
  PIN o[600]
    DIRECTION OUTPUT ;
    USE SIGNAL ;
    PORT
      LAYER M4 ;
        RECT  0 64.848 0.192 64.872 ;
    END
  END o[600]
  PIN o[601]
    DIRECTION OUTPUT ;
    USE SIGNAL ;
    PORT
      LAYER M4 ;
        RECT  0 64.944 0.192 64.968 ;
    END
  END o[601]
  PIN o[602]
    DIRECTION OUTPUT ;
    USE SIGNAL ;
    PORT
      LAYER M4 ;
        RECT  0 65.04 0.192 65.064 ;
    END
  END o[602]
  PIN o[603]
    DIRECTION OUTPUT ;
    USE SIGNAL ;
    PORT
      LAYER M4 ;
        RECT  0 65.136 0.192 65.16 ;
    END
  END o[603]
  PIN o[604]
    DIRECTION OUTPUT ;
    USE SIGNAL ;
    PORT
      LAYER M4 ;
        RECT  0 65.28 0.192 65.304 ;
    END
  END o[604]
  PIN o[605]
    DIRECTION OUTPUT ;
    USE SIGNAL ;
    PORT
      LAYER M4 ;
        RECT  0 65.376 0.192 65.4 ;
    END
  END o[605]
  PIN o[606]
    DIRECTION OUTPUT ;
    USE SIGNAL ;
    PORT
      LAYER M4 ;
        RECT  0 65.472 0.192 65.496 ;
    END
  END o[606]
  PIN o[607]
    DIRECTION OUTPUT ;
    USE SIGNAL ;
    PORT
      LAYER M4 ;
        RECT  0 65.568 0.192 65.592 ;
    END
  END o[607]
  PIN o[608]
    DIRECTION OUTPUT ;
    USE SIGNAL ;
    PORT
      LAYER M4 ;
        RECT  0 65.664 0.192 65.688 ;
    END
  END o[608]
  PIN o[609]
    DIRECTION OUTPUT ;
    USE SIGNAL ;
    PORT
      LAYER M4 ;
        RECT  0 65.76 0.192 65.784 ;
    END
  END o[609]
  PIN o[60]
    DIRECTION OUTPUT ;
    USE SIGNAL ;
    PORT
      LAYER M4 ;
        RECT  0 8.496 0.192 8.52 ;
    END
  END o[60]
  PIN o[610]
    DIRECTION OUTPUT ;
    USE SIGNAL ;
    PORT
      LAYER M4 ;
        RECT  0 65.904 0.192 65.928 ;
    END
  END o[610]
  PIN o[611]
    DIRECTION OUTPUT ;
    USE SIGNAL ;
    PORT
      LAYER M4 ;
        RECT  0 66 0.192 66.024 ;
    END
  END o[611]
  PIN o[612]
    DIRECTION OUTPUT ;
    USE SIGNAL ;
    PORT
      LAYER M4 ;
        RECT  0 66.096 0.192 66.12 ;
    END
  END o[612]
  PIN o[613]
    DIRECTION OUTPUT ;
    USE SIGNAL ;
    PORT
      LAYER M4 ;
        RECT  0 66.192 0.192 66.216 ;
    END
  END o[613]
  PIN o[614]
    DIRECTION OUTPUT ;
    USE SIGNAL ;
    PORT
      LAYER M4 ;
        RECT  0 66.288 0.192 66.312 ;
    END
  END o[614]
  PIN o[615]
    DIRECTION OUTPUT ;
    USE SIGNAL ;
    PORT
      LAYER M4 ;
        RECT  0 66.384 0.192 66.408 ;
    END
  END o[615]
  PIN o[616]
    DIRECTION OUTPUT ;
    USE SIGNAL ;
    PORT
      LAYER M4 ;
        RECT  0 66.528 0.192 66.552 ;
    END
  END o[616]
  PIN o[617]
    DIRECTION OUTPUT ;
    USE SIGNAL ;
    PORT
      LAYER M4 ;
        RECT  0 66.624 0.192 66.648 ;
    END
  END o[617]
  PIN o[618]
    DIRECTION OUTPUT ;
    USE SIGNAL ;
    PORT
      LAYER M4 ;
        RECT  0 66.72 0.192 66.744 ;
    END
  END o[618]
  PIN o[619]
    DIRECTION OUTPUT ;
    USE SIGNAL ;
    PORT
      LAYER M4 ;
        RECT  0 66.816 0.192 66.84 ;
    END
  END o[619]
  PIN o[61]
    DIRECTION OUTPUT ;
    USE SIGNAL ;
    PORT
      LAYER M4 ;
        RECT  0 8.592 0.192 8.616 ;
    END
  END o[61]
  PIN o[620]
    DIRECTION OUTPUT ;
    USE SIGNAL ;
    PORT
      LAYER M4 ;
        RECT  0 66.912 0.192 66.936 ;
    END
  END o[620]
  PIN o[621]
    DIRECTION OUTPUT ;
    USE SIGNAL ;
    PORT
      LAYER M4 ;
        RECT  0 67.056 0.192 67.08 ;
    END
  END o[621]
  PIN o[622]
    DIRECTION OUTPUT ;
    USE SIGNAL ;
    PORT
      LAYER M4 ;
        RECT  0 67.152 0.192 67.176 ;
    END
  END o[622]
  PIN o[623]
    DIRECTION OUTPUT ;
    USE SIGNAL ;
    PORT
      LAYER M4 ;
        RECT  0 67.248 0.192 67.272 ;
    END
  END o[623]
  PIN o[624]
    DIRECTION OUTPUT ;
    USE SIGNAL ;
    PORT
      LAYER M4 ;
        RECT  0 67.344 0.192 67.368 ;
    END
  END o[624]
  PIN o[625]
    DIRECTION OUTPUT ;
    USE SIGNAL ;
    PORT
      LAYER M4 ;
        RECT  0 67.44 0.192 67.464 ;
    END
  END o[625]
  PIN o[626]
    DIRECTION OUTPUT ;
    USE SIGNAL ;
    PORT
      LAYER M4 ;
        RECT  0 67.536 0.192 67.56 ;
    END
  END o[626]
  PIN o[627]
    DIRECTION OUTPUT ;
    USE SIGNAL ;
    PORT
      LAYER M4 ;
        RECT  0 67.68 0.192 67.704 ;
    END
  END o[627]
  PIN o[628]
    DIRECTION OUTPUT ;
    USE SIGNAL ;
    PORT
      LAYER M4 ;
        RECT  0 67.776 0.192 67.8 ;
    END
  END o[628]
  PIN o[629]
    DIRECTION OUTPUT ;
    USE SIGNAL ;
    PORT
      LAYER M4 ;
        RECT  0 67.872 0.192 67.896 ;
    END
  END o[629]
  PIN o[62]
    DIRECTION OUTPUT ;
    USE SIGNAL ;
    PORT
      LAYER M4 ;
        RECT  0 8.688 0.192 8.712 ;
    END
  END o[62]
  PIN o[630]
    DIRECTION OUTPUT ;
    USE SIGNAL ;
    PORT
      LAYER M4 ;
        RECT  0 67.968 0.192 67.992 ;
    END
  END o[630]
  PIN o[631]
    DIRECTION OUTPUT ;
    USE SIGNAL ;
    PORT
      LAYER M4 ;
        RECT  0 68.064 0.192 68.088 ;
    END
  END o[631]
  PIN o[632]
    DIRECTION OUTPUT ;
    USE SIGNAL ;
    PORT
      LAYER M4 ;
        RECT  0 68.16 0.192 68.184 ;
    END
  END o[632]
  PIN o[633]
    DIRECTION OUTPUT ;
    USE SIGNAL ;
    PORT
      LAYER M4 ;
        RECT  0 68.304 0.192 68.328 ;
    END
  END o[633]
  PIN o[634]
    DIRECTION OUTPUT ;
    USE SIGNAL ;
    PORT
      LAYER M4 ;
        RECT  0 68.4 0.192 68.424 ;
    END
  END o[634]
  PIN o[635]
    DIRECTION OUTPUT ;
    USE SIGNAL ;
    PORT
      LAYER M4 ;
        RECT  0 68.496 0.192 68.52 ;
    END
  END o[635]
  PIN o[636]
    DIRECTION OUTPUT ;
    USE SIGNAL ;
    PORT
      LAYER M4 ;
        RECT  0 68.592 0.192 68.616 ;
    END
  END o[636]
  PIN o[637]
    DIRECTION OUTPUT ;
    USE SIGNAL ;
    PORT
      LAYER M4 ;
        RECT  0 68.688 0.192 68.712 ;
    END
  END o[637]
  PIN o[638]
    DIRECTION OUTPUT ;
    USE SIGNAL ;
    PORT
      LAYER M4 ;
        RECT  0 68.784 0.192 68.808 ;
    END
  END o[638]
  PIN o[639]
    DIRECTION OUTPUT ;
    USE SIGNAL ;
    PORT
      LAYER M4 ;
        RECT  0 68.928 0.192 68.952 ;
    END
  END o[639]
  PIN o[63]
    DIRECTION OUTPUT ;
    USE SIGNAL ;
    PORT
      LAYER M4 ;
        RECT  0 8.784 0.192 8.808 ;
    END
  END o[63]
  PIN o[640]
    DIRECTION OUTPUT ;
    USE SIGNAL ;
    PORT
      LAYER M4 ;
        RECT  0 69.024 0.192 69.048 ;
    END
  END o[640]
  PIN o[641]
    DIRECTION OUTPUT ;
    USE SIGNAL ;
    PORT
      LAYER M4 ;
        RECT  0 69.12 0.192 69.144 ;
    END
  END o[641]
  PIN o[642]
    DIRECTION OUTPUT ;
    USE SIGNAL ;
    PORT
      LAYER M4 ;
        RECT  0 69.216 0.192 69.24 ;
    END
  END o[642]
  PIN o[643]
    DIRECTION OUTPUT ;
    USE SIGNAL ;
    PORT
      LAYER M4 ;
        RECT  0 69.312 0.192 69.336 ;
    END
  END o[643]
  PIN o[644]
    DIRECTION OUTPUT ;
    USE SIGNAL ;
    PORT
      LAYER M4 ;
        RECT  0 69.456 0.192 69.48 ;
    END
  END o[644]
  PIN o[645]
    DIRECTION OUTPUT ;
    USE SIGNAL ;
    PORT
      LAYER M4 ;
        RECT  0 69.552 0.192 69.576 ;
    END
  END o[645]
  PIN o[646]
    DIRECTION OUTPUT ;
    USE SIGNAL ;
    PORT
      LAYER M4 ;
        RECT  0 69.648 0.192 69.672 ;
    END
  END o[646]
  PIN o[647]
    DIRECTION OUTPUT ;
    USE SIGNAL ;
    PORT
      LAYER M4 ;
        RECT  0 69.744 0.192 69.768 ;
    END
  END o[647]
  PIN o[648]
    DIRECTION OUTPUT ;
    USE SIGNAL ;
    PORT
      LAYER M4 ;
        RECT  0 69.84 0.192 69.864 ;
    END
  END o[648]
  PIN o[649]
    DIRECTION OUTPUT ;
    USE SIGNAL ;
    PORT
      LAYER M4 ;
        RECT  0 69.936 0.192 69.96 ;
    END
  END o[649]
  PIN o[64]
    DIRECTION OUTPUT ;
    USE SIGNAL ;
    PORT
      LAYER M4 ;
        RECT  0 8.88 0.192 8.904 ;
    END
  END o[64]
  PIN o[650]
    DIRECTION OUTPUT ;
    USE SIGNAL ;
    PORT
      LAYER M4 ;
        RECT  0 70.08 0.192 70.104 ;
    END
  END o[650]
  PIN o[651]
    DIRECTION OUTPUT ;
    USE SIGNAL ;
    PORT
      LAYER M4 ;
        RECT  0 70.176 0.192 70.2 ;
    END
  END o[651]
  PIN o[652]
    DIRECTION OUTPUT ;
    USE SIGNAL ;
    PORT
      LAYER M4 ;
        RECT  0 70.272 0.192 70.296 ;
    END
  END o[652]
  PIN o[653]
    DIRECTION OUTPUT ;
    USE SIGNAL ;
    PORT
      LAYER M4 ;
        RECT  0 70.368 0.192 70.392 ;
    END
  END o[653]
  PIN o[654]
    DIRECTION OUTPUT ;
    USE SIGNAL ;
    PORT
      LAYER M4 ;
        RECT  0 70.464 0.192 70.488 ;
    END
  END o[654]
  PIN o[655]
    DIRECTION OUTPUT ;
    USE SIGNAL ;
    PORT
      LAYER M4 ;
        RECT  0 70.56 0.192 70.584 ;
    END
  END o[655]
  PIN o[656]
    DIRECTION OUTPUT ;
    USE SIGNAL ;
    PORT
      LAYER M4 ;
        RECT  0 70.704 0.192 70.728 ;
    END
  END o[656]
  PIN o[657]
    DIRECTION OUTPUT ;
    USE SIGNAL ;
    PORT
      LAYER M4 ;
        RECT  0 70.8 0.192 70.824 ;
    END
  END o[657]
  PIN o[658]
    DIRECTION OUTPUT ;
    USE SIGNAL ;
    PORT
      LAYER M4 ;
        RECT  0 70.896 0.192 70.92 ;
    END
  END o[658]
  PIN o[659]
    DIRECTION OUTPUT ;
    USE SIGNAL ;
    PORT
      LAYER M4 ;
        RECT  0 70.992 0.192 71.016 ;
    END
  END o[659]
  PIN o[65]
    DIRECTION OUTPUT ;
    USE SIGNAL ;
    PORT
      LAYER M4 ;
        RECT  0 9.024 0.192 9.048 ;
    END
  END o[65]
  PIN o[660]
    DIRECTION OUTPUT ;
    USE SIGNAL ;
    PORT
      LAYER M4 ;
        RECT  0 71.088 0.192 71.112 ;
    END
  END o[660]
  PIN o[661]
    DIRECTION OUTPUT ;
    USE SIGNAL ;
    PORT
      LAYER M4 ;
        RECT  0 71.232 0.192 71.256 ;
    END
  END o[661]
  PIN o[662]
    DIRECTION OUTPUT ;
    USE SIGNAL ;
    PORT
      LAYER M4 ;
        RECT  0 71.328 0.192 71.352 ;
    END
  END o[662]
  PIN o[663]
    DIRECTION OUTPUT ;
    USE SIGNAL ;
    PORT
      LAYER M4 ;
        RECT  0 71.424 0.192 71.448 ;
    END
  END o[663]
  PIN o[664]
    DIRECTION OUTPUT ;
    USE SIGNAL ;
    PORT
      LAYER M4 ;
        RECT  0 71.52 0.192 71.544 ;
    END
  END o[664]
  PIN o[665]
    DIRECTION OUTPUT ;
    USE SIGNAL ;
    PORT
      LAYER M4 ;
        RECT  0 71.616 0.192 71.64 ;
    END
  END o[665]
  PIN o[666]
    DIRECTION OUTPUT ;
    USE SIGNAL ;
    PORT
      LAYER M4 ;
        RECT  0 71.712 0.192 71.736 ;
    END
  END o[666]
  PIN o[667]
    DIRECTION OUTPUT ;
    USE SIGNAL ;
    PORT
      LAYER M4 ;
        RECT  0 71.856 0.192 71.88 ;
    END
  END o[667]
  PIN o[668]
    DIRECTION OUTPUT ;
    USE SIGNAL ;
    PORT
      LAYER M4 ;
        RECT  0 71.952 0.192 71.976 ;
    END
  END o[668]
  PIN o[669]
    DIRECTION OUTPUT ;
    USE SIGNAL ;
    PORT
      LAYER M4 ;
        RECT  0 72.048 0.192 72.072 ;
    END
  END o[669]
  PIN o[66]
    DIRECTION OUTPUT ;
    USE SIGNAL ;
    PORT
      LAYER M4 ;
        RECT  0 9.12 0.192 9.144 ;
    END
  END o[66]
  PIN o[670]
    DIRECTION OUTPUT ;
    USE SIGNAL ;
    PORT
      LAYER M4 ;
        RECT  0 72.144 0.192 72.168 ;
    END
  END o[670]
  PIN o[671]
    DIRECTION OUTPUT ;
    USE SIGNAL ;
    PORT
      LAYER M4 ;
        RECT  0 72.24 0.192 72.264 ;
    END
  END o[671]
  PIN o[672]
    DIRECTION OUTPUT ;
    USE SIGNAL ;
    PORT
      LAYER M4 ;
        RECT  0 72.336 0.192 72.36 ;
    END
  END o[672]
  PIN o[673]
    DIRECTION OUTPUT ;
    USE SIGNAL ;
    PORT
      LAYER M4 ;
        RECT  0 72.48 0.192 72.504 ;
    END
  END o[673]
  PIN o[674]
    DIRECTION OUTPUT ;
    USE SIGNAL ;
    PORT
      LAYER M4 ;
        RECT  0 72.576 0.192 72.6 ;
    END
  END o[674]
  PIN o[675]
    DIRECTION OUTPUT ;
    USE SIGNAL ;
    PORT
      LAYER M4 ;
        RECT  0 72.672 0.192 72.696 ;
    END
  END o[675]
  PIN o[676]
    DIRECTION OUTPUT ;
    USE SIGNAL ;
    PORT
      LAYER M4 ;
        RECT  0 72.768 0.192 72.792 ;
    END
  END o[676]
  PIN o[677]
    DIRECTION OUTPUT ;
    USE SIGNAL ;
    PORT
      LAYER M4 ;
        RECT  0 72.864 0.192 72.888 ;
    END
  END o[677]
  PIN o[678]
    DIRECTION OUTPUT ;
    USE SIGNAL ;
    PORT
      LAYER M4 ;
        RECT  0 72.96 0.192 72.984 ;
    END
  END o[678]
  PIN o[679]
    DIRECTION OUTPUT ;
    USE SIGNAL ;
    PORT
      LAYER M4 ;
        RECT  0 73.104 0.192 73.128 ;
    END
  END o[679]
  PIN o[67]
    DIRECTION OUTPUT ;
    USE SIGNAL ;
    PORT
      LAYER M4 ;
        RECT  0 9.216 0.192 9.24 ;
    END
  END o[67]
  PIN o[680]
    DIRECTION OUTPUT ;
    USE SIGNAL ;
    PORT
      LAYER M4 ;
        RECT  0 73.2 0.192 73.224 ;
    END
  END o[680]
  PIN o[681]
    DIRECTION OUTPUT ;
    USE SIGNAL ;
    PORT
      LAYER M4 ;
        RECT  0 73.296 0.192 73.32 ;
    END
  END o[681]
  PIN o[68]
    DIRECTION OUTPUT ;
    USE SIGNAL ;
    PORT
      LAYER M4 ;
        RECT  0 9.312 0.192 9.336 ;
    END
  END o[68]
  PIN o[69]
    DIRECTION OUTPUT ;
    USE SIGNAL ;
    PORT
      LAYER M4 ;
        RECT  0 9.408 0.192 9.432 ;
    END
  END o[69]
  PIN o[6]
    DIRECTION OUTPUT ;
    USE SIGNAL ;
    PORT
      LAYER M4 ;
        RECT  0 2.832 0.192 2.856 ;
    END
  END o[6]
  PIN o[70]
    DIRECTION OUTPUT ;
    USE SIGNAL ;
    PORT
      LAYER M4 ;
        RECT  0 9.552 0.192 9.576 ;
    END
  END o[70]
  PIN o[71]
    DIRECTION OUTPUT ;
    USE SIGNAL ;
    PORT
      LAYER M4 ;
        RECT  0 9.648 0.192 9.672 ;
    END
  END o[71]
  PIN o[72]
    DIRECTION OUTPUT ;
    USE SIGNAL ;
    PORT
      LAYER M4 ;
        RECT  0 9.744 0.192 9.768 ;
    END
  END o[72]
  PIN o[73]
    DIRECTION OUTPUT ;
    USE SIGNAL ;
    PORT
      LAYER M4 ;
        RECT  0 9.84 0.192 9.864 ;
    END
  END o[73]
  PIN o[74]
    DIRECTION OUTPUT ;
    USE SIGNAL ;
    PORT
      LAYER M4 ;
        RECT  0 9.936 0.192 9.96 ;
    END
  END o[74]
  PIN o[75]
    DIRECTION OUTPUT ;
    USE SIGNAL ;
    PORT
      LAYER M4 ;
        RECT  0 10.032 0.192 10.056 ;
    END
  END o[75]
  PIN o[76]
    DIRECTION OUTPUT ;
    USE SIGNAL ;
    PORT
      LAYER M4 ;
        RECT  0 10.176 0.192 10.2 ;
    END
  END o[76]
  PIN o[77]
    DIRECTION OUTPUT ;
    USE SIGNAL ;
    PORT
      LAYER M4 ;
        RECT  0 10.272 0.192 10.296 ;
    END
  END o[77]
  PIN o[78]
    DIRECTION OUTPUT ;
    USE SIGNAL ;
    PORT
      LAYER M4 ;
        RECT  0 10.368 0.192 10.392 ;
    END
  END o[78]
  PIN o[79]
    DIRECTION OUTPUT ;
    USE SIGNAL ;
    PORT
      LAYER M4 ;
        RECT  0 10.464 0.192 10.488 ;
    END
  END o[79]
  PIN o[7]
    DIRECTION OUTPUT ;
    USE SIGNAL ;
    PORT
      LAYER M4 ;
        RECT  0 2.976 0.192 3 ;
    END
  END o[7]
  PIN o[80]
    DIRECTION OUTPUT ;
    USE SIGNAL ;
    PORT
      LAYER M4 ;
        RECT  0 10.56 0.192 10.584 ;
    END
  END o[80]
  PIN o[81]
    DIRECTION OUTPUT ;
    USE SIGNAL ;
    PORT
      LAYER M4 ;
        RECT  0 10.656 0.192 10.68 ;
    END
  END o[81]
  PIN o[82]
    DIRECTION OUTPUT ;
    USE SIGNAL ;
    PORT
      LAYER M4 ;
        RECT  0 10.8 0.192 10.824 ;
    END
  END o[82]
  PIN o[83]
    DIRECTION OUTPUT ;
    USE SIGNAL ;
    PORT
      LAYER M4 ;
        RECT  0 10.896 0.192 10.92 ;
    END
  END o[83]
  PIN o[84]
    DIRECTION OUTPUT ;
    USE SIGNAL ;
    PORT
      LAYER M4 ;
        RECT  0 10.992 0.192 11.016 ;
    END
  END o[84]
  PIN o[85]
    DIRECTION OUTPUT ;
    USE SIGNAL ;
    PORT
      LAYER M4 ;
        RECT  0 11.088 0.192 11.112 ;
    END
  END o[85]
  PIN o[86]
    DIRECTION OUTPUT ;
    USE SIGNAL ;
    PORT
      LAYER M4 ;
        RECT  0 11.184 0.192 11.208 ;
    END
  END o[86]
  PIN o[87]
    DIRECTION OUTPUT ;
    USE SIGNAL ;
    PORT
      LAYER M4 ;
        RECT  0 11.28 0.192 11.304 ;
    END
  END o[87]
  PIN o[88]
    DIRECTION OUTPUT ;
    USE SIGNAL ;
    PORT
      LAYER M4 ;
        RECT  0 11.424 0.192 11.448 ;
    END
  END o[88]
  PIN o[89]
    DIRECTION OUTPUT ;
    USE SIGNAL ;
    PORT
      LAYER M4 ;
        RECT  0 11.52 0.192 11.544 ;
    END
  END o[89]
  PIN o[8]
    DIRECTION OUTPUT ;
    USE SIGNAL ;
    PORT
      LAYER M4 ;
        RECT  0 3.072 0.192 3.096 ;
    END
  END o[8]
  PIN o[90]
    DIRECTION OUTPUT ;
    USE SIGNAL ;
    PORT
      LAYER M4 ;
        RECT  0 11.616 0.192 11.64 ;
    END
  END o[90]
  PIN o[91]
    DIRECTION OUTPUT ;
    USE SIGNAL ;
    PORT
      LAYER M4 ;
        RECT  0 11.712 0.192 11.736 ;
    END
  END o[91]
  PIN o[92]
    DIRECTION OUTPUT ;
    USE SIGNAL ;
    PORT
      LAYER M4 ;
        RECT  0 11.808 0.192 11.832 ;
    END
  END o[92]
  PIN o[93]
    DIRECTION OUTPUT ;
    USE SIGNAL ;
    PORT
      LAYER M4 ;
        RECT  0 11.952 0.192 11.976 ;
    END
  END o[93]
  PIN o[94]
    DIRECTION OUTPUT ;
    USE SIGNAL ;
    PORT
      LAYER M4 ;
        RECT  0 12.048 0.192 12.072 ;
    END
  END o[94]
  PIN o[95]
    DIRECTION OUTPUT ;
    USE SIGNAL ;
    PORT
      LAYER M4 ;
        RECT  0 12.144 0.192 12.168 ;
    END
  END o[95]
  PIN o[96]
    DIRECTION OUTPUT ;
    USE SIGNAL ;
    PORT
      LAYER M4 ;
        RECT  0 12.24 0.192 12.264 ;
    END
  END o[96]
  PIN o[97]
    DIRECTION OUTPUT ;
    USE SIGNAL ;
    PORT
      LAYER M4 ;
        RECT  0 12.336 0.192 12.36 ;
    END
  END o[97]
  PIN o[98]
    DIRECTION OUTPUT ;
    USE SIGNAL ;
    PORT
      LAYER M4 ;
        RECT  0 12.432 0.192 12.456 ;
    END
  END o[98]
  PIN o[99]
    DIRECTION OUTPUT ;
    USE SIGNAL ;
    PORT
      LAYER M4 ;
        RECT  0 12.576 0.192 12.6 ;
    END
  END o[99]
  PIN o[9]
    DIRECTION OUTPUT ;
    USE SIGNAL ;
    PORT
      LAYER M4 ;
        RECT  0 3.168 0.192 3.192 ;
    END
  END o[9]
  PIN rs
    DIRECTION INPUT ;
    USE SIGNAL ;
    PORT
      LAYER M5 ;
        RECT  11.856 75.408 11.88 75.6 ;
    END
  END rs
  PIN VDD
    DIRECTION INOUT ;
    USE POWER ;
    PORT
      LAYER M5 ;
        RECT  13.392 2.151 13.512 73.449 ;
        RECT  10.692 2.151 10.812 73.449 ;
        RECT  7.992 2.151 8.112 73.449 ;
        RECT  5.292 2.151 5.412 73.449 ;
        RECT  2.592 2.151 2.712 73.449 ;
    END
  END VDD
  PIN VSS
    DIRECTION INOUT ;
    USE GROUND ;
    PORT
      LAYER M5 ;
        RECT  13.2 2.137 13.32 73.463 ;
        RECT  10.5 2.137 10.62 73.463 ;
        RECT  7.8 2.137 7.92 73.463 ;
        RECT  5.1 2.137 5.22 73.463 ;
        RECT  2.4 2.137 2.52 73.463 ;
    END
  END VSS
  OBS
    LAYER RVTN ;
     RECT  2.16 2.16 15.12 2.295 ;
     RECT  2.16 2.565 15.12 2.835 ;
     RECT  2.16 3.105 15.12 3.375 ;
     RECT  2.16 3.645 15.12 3.915 ;
     RECT  2.16 4.185 15.12 4.455 ;
     RECT  2.16 4.725 15.12 4.995 ;
     RECT  2.16 5.265 15.12 5.535 ;
     RECT  2.16 5.805 15.12 6.075 ;
     RECT  2.16 6.345 15.12 6.615 ;
     RECT  2.16 6.885 15.12 7.155 ;
     RECT  2.16 7.425 15.12 7.695 ;
     RECT  2.16 7.965 15.12 8.235 ;
     RECT  2.16 8.505 15.12 8.775 ;
     RECT  2.16 9.045 15.12 9.315 ;
     RECT  2.16 9.585 15.12 9.855 ;
     RECT  2.16 10.125 15.12 10.395 ;
     RECT  2.16 10.665 15.12 10.935 ;
     RECT  2.16 11.205 15.12 11.475 ;
     RECT  2.16 11.745 15.12 12.015 ;
     RECT  2.16 12.285 15.12 12.555 ;
     RECT  2.16 12.825 15.12 13.095 ;
     RECT  2.16 13.365 15.12 13.635 ;
     RECT  2.16 13.905 15.12 14.175 ;
     RECT  2.16 14.445 15.12 14.715 ;
     RECT  2.16 14.985 15.12 15.255 ;
     RECT  2.16 15.525 15.12 15.795 ;
     RECT  2.16 16.065 15.12 16.335 ;
     RECT  2.16 16.605 15.12 16.875 ;
     RECT  2.16 17.145 15.12 17.415 ;
     RECT  2.16 17.685 15.12 17.955 ;
     RECT  2.16 18.225 15.12 18.495 ;
     RECT  2.16 18.765 15.12 19.035 ;
     RECT  2.16 19.305 15.12 19.575 ;
     RECT  2.16 19.845 15.12 20.115 ;
     RECT  2.16 20.385 15.12 20.655 ;
     RECT  2.16 20.925 15.12 21.195 ;
     RECT  2.16 21.465 15.12 21.735 ;
     RECT  2.16 22.005 15.12 22.275 ;
     RECT  2.16 22.545 15.12 22.815 ;
     RECT  2.16 23.085 15.12 23.355 ;
     RECT  2.16 23.625 15.12 23.895 ;
     RECT  2.16 24.165 15.12 24.435 ;
     RECT  2.16 24.705 15.12 24.975 ;
     RECT  2.16 25.245 15.12 25.515 ;
     RECT  2.16 25.785 15.12 26.055 ;
     RECT  2.16 26.325 15.12 26.595 ;
     RECT  2.16 26.865 15.12 27.135 ;
     RECT  2.16 27.405 15.12 27.675 ;
     RECT  2.16 27.945 15.12 28.215 ;
     RECT  2.16 28.485 15.12 28.755 ;
     RECT  2.16 29.025 15.12 29.295 ;
     RECT  2.16 29.565 15.12 29.835 ;
     RECT  2.16 30.105 15.12 30.375 ;
     RECT  2.16 30.645 15.12 30.915 ;
     RECT  2.16 31.185 15.12 31.455 ;
     RECT  2.16 31.725 15.12 31.995 ;
     RECT  2.16 32.265 15.12 32.535 ;
     RECT  2.16 32.805 15.12 33.075 ;
     RECT  2.16 33.345 15.12 33.615 ;
     RECT  2.16 33.885 15.12 34.155 ;
     RECT  2.16 34.425 15.12 34.695 ;
     RECT  2.16 34.965 15.12 35.235 ;
     RECT  2.16 35.505 15.12 35.775 ;
     RECT  2.16 36.045 15.12 36.315 ;
     RECT  2.16 36.585 15.12 36.855 ;
     RECT  2.16 37.125 15.12 37.395 ;
     RECT  2.16 37.665 15.12 37.935 ;
     RECT  2.16 38.205 15.12 38.475 ;
     RECT  2.16 38.745 15.12 39.015 ;
     RECT  2.16 39.285 15.12 39.555 ;
     RECT  2.16 39.825 15.12 40.095 ;
     RECT  2.16 40.365 15.12 40.635 ;
     RECT  2.16 40.905 15.12 41.175 ;
     RECT  2.16 41.445 15.12 41.715 ;
     RECT  2.16 41.985 15.12 42.255 ;
     RECT  2.16 42.525 15.12 42.795 ;
     RECT  2.16 43.065 15.12 43.335 ;
     RECT  2.16 43.605 15.12 43.875 ;
     RECT  2.16 44.145 15.12 44.415 ;
     RECT  2.16 44.685 15.12 44.955 ;
     RECT  2.16 45.225 15.12 45.495 ;
     RECT  2.16 45.765 15.12 46.035 ;
     RECT  2.16 46.305 15.12 46.575 ;
     RECT  2.16 46.845 15.12 47.115 ;
     RECT  2.16 47.385 15.12 47.655 ;
     RECT  2.16 47.925 15.12 48.195 ;
     RECT  2.16 48.465 15.12 48.735 ;
     RECT  2.16 49.005 15.12 49.275 ;
     RECT  2.16 49.545 15.12 49.815 ;
     RECT  2.16 50.085 15.12 50.355 ;
     RECT  2.16 50.625 15.12 50.895 ;
     RECT  2.16 51.165 15.12 51.435 ;
     RECT  2.16 51.705 15.12 51.975 ;
     RECT  2.16 52.245 15.12 52.515 ;
     RECT  2.16 52.785 15.12 53.055 ;
     RECT  2.16 53.325 15.12 53.595 ;
     RECT  2.16 53.865 15.12 54.135 ;
     RECT  2.16 54.405 15.12 54.675 ;
     RECT  2.16 54.945 15.12 55.215 ;
     RECT  2.16 55.485 15.12 55.755 ;
     RECT  2.16 56.025 15.12 56.295 ;
     RECT  2.16 56.565 15.12 56.835 ;
     RECT  2.16 57.105 15.12 57.375 ;
     RECT  2.16 57.645 15.12 57.915 ;
     RECT  2.16 58.185 15.12 58.455 ;
     RECT  2.16 58.725 15.12 58.995 ;
     RECT  2.16 59.265 15.12 59.535 ;
     RECT  2.16 59.805 15.12 60.075 ;
     RECT  2.16 60.345 15.12 60.615 ;
     RECT  2.16 60.885 15.12 61.155 ;
     RECT  2.16 61.425 15.12 61.695 ;
     RECT  2.16 61.965 15.12 62.235 ;
     RECT  2.16 62.505 15.12 62.775 ;
     RECT  2.16 63.045 15.12 63.315 ;
     RECT  2.16 63.585 15.12 63.855 ;
     RECT  2.16 64.125 15.12 64.395 ;
     RECT  2.16 64.665 15.12 64.935 ;
     RECT  2.16 65.205 15.12 65.475 ;
     RECT  2.16 65.745 15.12 66.015 ;
     RECT  2.16 66.285 15.12 66.555 ;
     RECT  2.16 66.825 15.12 67.095 ;
     RECT  2.16 67.365 15.12 67.635 ;
     RECT  2.16 67.905 15.12 68.175 ;
     RECT  2.16 68.445 15.12 68.715 ;
     RECT  2.16 68.985 15.12 69.255 ;
     RECT  2.16 69.525 15.12 69.795 ;
     RECT  2.16 70.065 15.12 70.335 ;
     RECT  2.16 70.605 15.12 70.875 ;
     RECT  2.16 71.145 15.12 71.415 ;
     RECT  2.16 71.685 15.12 71.955 ;
     RECT  2.16 72.225 15.12 72.495 ;
     RECT  2.16 72.765 15.12 73.035 ;
     RECT  2.16 73.305 15.12 73.44 ;
    LAYER RVTP ;
     RECT  2.16 2.295 15.12 2.565 ;
     RECT  2.16 2.835 15.12 3.105 ;
     RECT  2.16 3.375 15.12 3.645 ;
     RECT  2.16 3.915 15.12 4.185 ;
     RECT  2.16 4.455 15.12 4.725 ;
     RECT  2.16 4.995 15.12 5.265 ;
     RECT  2.16 5.535 15.12 5.805 ;
     RECT  2.16 6.075 15.12 6.345 ;
     RECT  2.16 6.615 15.12 6.885 ;
     RECT  2.16 7.155 15.12 7.425 ;
     RECT  2.16 7.695 15.12 7.965 ;
     RECT  2.16 8.235 15.12 8.505 ;
     RECT  2.16 8.775 15.12 9.045 ;
     RECT  2.16 9.315 15.12 9.585 ;
     RECT  2.16 9.855 15.12 10.125 ;
     RECT  2.16 10.395 15.12 10.665 ;
     RECT  2.16 10.935 15.12 11.205 ;
     RECT  2.16 11.475 15.12 11.745 ;
     RECT  2.16 12.015 15.12 12.285 ;
     RECT  2.16 12.555 15.12 12.825 ;
     RECT  2.16 13.095 15.12 13.365 ;
     RECT  2.16 13.635 15.12 13.905 ;
     RECT  2.16 14.175 15.12 14.445 ;
     RECT  2.16 14.715 15.12 14.985 ;
     RECT  2.16 15.255 15.12 15.525 ;
     RECT  2.16 15.795 15.12 16.065 ;
     RECT  2.16 16.335 15.12 16.605 ;
     RECT  2.16 16.875 15.12 17.145 ;
     RECT  2.16 17.415 15.12 17.685 ;
     RECT  2.16 17.955 15.12 18.225 ;
     RECT  2.16 18.495 15.12 18.765 ;
     RECT  2.16 19.035 15.12 19.305 ;
     RECT  2.16 19.575 15.12 19.845 ;
     RECT  2.16 20.115 15.12 20.385 ;
     RECT  2.16 20.655 15.12 20.925 ;
     RECT  2.16 21.195 15.12 21.465 ;
     RECT  2.16 21.735 15.12 22.005 ;
     RECT  2.16 22.275 15.12 22.545 ;
     RECT  2.16 22.815 15.12 23.085 ;
     RECT  2.16 23.355 15.12 23.625 ;
     RECT  2.16 23.895 15.12 24.165 ;
     RECT  2.16 24.435 15.12 24.705 ;
     RECT  2.16 24.975 15.12 25.245 ;
     RECT  2.16 25.515 15.12 25.785 ;
     RECT  2.16 26.055 15.12 26.325 ;
     RECT  2.16 26.595 15.12 26.865 ;
     RECT  2.16 27.135 15.12 27.405 ;
     RECT  2.16 27.675 15.12 27.945 ;
     RECT  2.16 28.215 15.12 28.485 ;
     RECT  2.16 28.755 15.12 29.025 ;
     RECT  2.16 29.295 15.12 29.565 ;
     RECT  2.16 29.835 15.12 30.105 ;
     RECT  2.16 30.375 15.12 30.645 ;
     RECT  2.16 30.915 15.12 31.185 ;
     RECT  2.16 31.455 15.12 31.725 ;
     RECT  2.16 31.995 15.12 32.265 ;
     RECT  2.16 32.535 15.12 32.805 ;
     RECT  2.16 33.075 15.12 33.345 ;
     RECT  2.16 33.615 15.12 33.885 ;
     RECT  2.16 34.155 15.12 34.425 ;
     RECT  2.16 34.695 15.12 34.965 ;
     RECT  2.16 35.235 15.12 35.505 ;
     RECT  2.16 35.775 15.12 36.045 ;
     RECT  2.16 36.315 15.12 36.585 ;
     RECT  2.16 36.855 15.12 37.125 ;
     RECT  2.16 37.395 15.12 37.665 ;
     RECT  2.16 37.935 15.12 38.205 ;
     RECT  2.16 38.475 15.12 38.745 ;
     RECT  2.16 39.015 15.12 39.285 ;
     RECT  2.16 39.555 15.12 39.825 ;
     RECT  2.16 40.095 15.12 40.365 ;
     RECT  2.16 40.635 15.12 40.905 ;
     RECT  2.16 41.175 15.12 41.445 ;
     RECT  2.16 41.715 15.12 41.985 ;
     RECT  2.16 42.255 15.12 42.525 ;
     RECT  2.16 42.795 15.12 43.065 ;
     RECT  2.16 43.335 15.12 43.605 ;
     RECT  2.16 43.875 15.12 44.145 ;
     RECT  2.16 44.415 15.12 44.685 ;
     RECT  2.16 44.955 15.12 45.225 ;
     RECT  2.16 45.495 15.12 45.765 ;
     RECT  2.16 46.035 15.12 46.305 ;
     RECT  2.16 46.575 15.12 46.845 ;
     RECT  2.16 47.115 15.12 47.385 ;
     RECT  2.16 47.655 15.12 47.925 ;
     RECT  2.16 48.195 15.12 48.465 ;
     RECT  2.16 48.735 15.12 49.005 ;
     RECT  2.16 49.275 15.12 49.545 ;
     RECT  2.16 49.815 15.12 50.085 ;
     RECT  2.16 50.355 15.12 50.625 ;
     RECT  2.16 50.895 15.12 51.165 ;
     RECT  2.16 51.435 15.12 51.705 ;
     RECT  2.16 51.975 15.12 52.245 ;
     RECT  2.16 52.515 15.12 52.785 ;
     RECT  2.16 53.055 15.12 53.325 ;
     RECT  2.16 53.595 15.12 53.865 ;
     RECT  2.16 54.135 15.12 54.405 ;
     RECT  2.16 54.675 15.12 54.945 ;
     RECT  2.16 55.215 15.12 55.485 ;
     RECT  2.16 55.755 15.12 56.025 ;
     RECT  2.16 56.295 15.12 56.565 ;
     RECT  2.16 56.835 15.12 57.105 ;
     RECT  2.16 57.375 15.12 57.645 ;
     RECT  2.16 57.915 15.12 58.185 ;
     RECT  2.16 58.455 15.12 58.725 ;
     RECT  2.16 58.995 15.12 59.265 ;
     RECT  2.16 59.535 15.12 59.805 ;
     RECT  2.16 60.075 15.12 60.345 ;
     RECT  2.16 60.615 15.12 60.885 ;
     RECT  2.16 61.155 15.12 61.425 ;
     RECT  2.16 61.695 15.12 61.965 ;
     RECT  2.16 62.235 15.12 62.505 ;
     RECT  2.16 62.775 15.12 63.045 ;
     RECT  2.16 63.315 15.12 63.585 ;
     RECT  2.16 63.855 15.12 64.125 ;
     RECT  2.16 64.395 15.12 64.665 ;
     RECT  2.16 64.935 15.12 65.205 ;
     RECT  2.16 65.475 15.12 65.745 ;
     RECT  2.16 66.015 15.12 66.285 ;
     RECT  2.16 66.555 15.12 66.825 ;
     RECT  2.16 67.095 15.12 67.365 ;
     RECT  2.16 67.635 15.12 67.905 ;
     RECT  2.16 68.175 15.12 68.445 ;
     RECT  2.16 68.715 15.12 68.985 ;
     RECT  2.16 69.255 15.12 69.525 ;
     RECT  2.16 69.795 15.12 70.065 ;
     RECT  2.16 70.335 15.12 70.605 ;
     RECT  2.16 70.875 15.12 71.145 ;
     RECT  2.16 71.415 15.12 71.685 ;
     RECT  2.16 71.955 15.12 72.225 ;
     RECT  2.16 72.495 15.12 72.765 ;
     RECT  2.16 73.035 15.12 73.305 ;
    LAYER M1 ;
     RECT  2.16 2.151 15.12 73.449 ;
    LAYER M2 ;
     RECT  0.211 64.944 0.283 64.962 ;
     RECT  0.211 10.368 0.311 10.386 ;
     RECT  0.211 23.751 0.311 23.958 ;
     RECT  0.211 29.07 0.311 29.088 ;
     RECT  0.211 42.732 0.311 42.75 ;
     RECT  0.211 45.351 0.311 45.594 ;
     RECT  0.283 64.944 0.311 65.034 ;
     RECT  0.211 2.691 0.347 2.898 ;
     RECT  0.311 65.016 0.383 65.034 ;
     RECT  0.283 49.896 0.455 49.914 ;
     RECT  0.427 72.036 0.527 72.054 ;
     RECT  0.211 15.876 0.535 15.894 ;
     RECT  0.211 44.316 0.535 44.334 ;
     RECT  0.247 49.014 0.535 49.032 ;
     RECT  0.211 68.958 0.535 68.976 ;
     RECT  0.535 52.866 0.571 52.884 ;
     RECT  0.571 52.866 0.671 52.974 ;
     RECT  0.535 48.204 1.139 49.032 ;
     RECT  1.139 48.204 1.211 48.834 ;
     RECT  0.535 3.96 2.16 3.978 ;
     RECT  0.535 11.376 2.16 11.394 ;
     RECT  0.535 15.876 2.16 16.362 ;
     RECT  0.535 17.586 2.16 18.054 ;
     RECT  0.535 21.546 2.16 21.564 ;
     RECT  0.535 22.716 2.16 22.734 ;
     RECT  0.535 26.766 2.16 27.324 ;
     RECT  0.211 31.356 2.16 31.374 ;
     RECT  0.535 43.038 2.16 44.334 ;
     RECT  0.211 47.286 2.16 47.304 ;
     RECT  1.211 48.204 2.16 48.762 ;
     RECT  0.671 52.866 2.16 52.884 ;
     RECT  0.535 57.384 2.16 57.402 ;
     RECT  0.535 58.626 2.16 58.644 ;
     RECT  0.535 63.09 2.16 63.108 ;
     RECT  0.535 67.806 2.16 68.976 ;
     RECT  2.16 2.151 2.659 73.449 ;
     RECT  2.659 2.106 2.839 73.449 ;
     RECT  2.839 2.034 3.847 73.449 ;
     RECT  3.847 2.034 6.763 73.53 ;
     RECT  6.763 1.962 7.663 73.53 ;
     RECT  7.663 1.962 8.123 73.566 ;
     RECT  8.123 2.034 9.995 73.566 ;
     RECT  9.995 2.034 12.703 73.53 ;
     RECT  12.703 1.998 14.387 73.53 ;
     RECT  14.387 1.998 14.531 73.449 ;
     RECT  14.531 2.034 15.12 73.449 ;
     RECT  15.12 69.534 15.395 73.296 ;
     RECT  15.12 2.034 15.431 4.68 ;
     RECT  15.12 5.778 15.431 10.728 ;
     RECT  15.12 12.87 15.431 18.558 ;
     RECT  15.12 19.62 15.431 27.936 ;
     RECT  15.12 28.8 15.431 29.016 ;
     RECT  15.12 29.844 15.431 34.488 ;
     RECT  15.12 35.28 15.431 36.378 ;
     RECT  15.12 37.17 15.431 46.638 ;
     RECT  15.12 47.394 15.431 53.01 ;
     RECT  15.12 53.91 15.431 68.706 ;
     RECT  15.395 70.614 15.431 73.296 ;
     RECT  15.431 23.166 15.467 24.228 ;
     RECT  15.431 35.55 15.467 36.378 ;
     RECT  15.431 40.716 15.467 42.48 ;
     RECT  15.431 46.35 15.467 46.638 ;
     RECT  15.431 49.248 15.467 52.776 ;
     RECT  15.431 56.538 15.467 57.636 ;
     RECT  15.431 58.428 15.467 59.526 ;
     RECT  15.431 65.142 15.467 67.428 ;
     RECT  15.395 69.534 15.467 69.858 ;
     RECT  15.431 25.02 15.503 26.82 ;
     RECT  15.431 29.88 15.503 32.454 ;
     RECT  15.467 66.834 15.503 67.428 ;
     RECT  15.431 2.034 16.007 2.088 ;
     RECT  15.431 19.62 16.007 22.104 ;
     RECT  15.503 30.078 16.007 32.454 ;
     RECT  15.467 40.716 16.007 40.734 ;
     RECT  15.467 51.642 16.007 52.776 ;
     RECT  15.431 62.172 16.007 64.35 ;
     RECT  15.467 65.142 16.007 65.772 ;
     RECT  16.007 32.436 16.043 32.454 ;
     RECT  15.431 55.224 16.511 55.278 ;
     RECT  16.007 2.07 16.547 2.088 ;
     RECT  15.431 3.654 16.547 4.68 ;
     RECT  15.431 5.85 16.547 6.408 ;
     RECT  15.431 7.164 16.547 8.334 ;
     RECT  15.431 9.288 16.547 9.306 ;
     RECT  15.431 10.098 16.547 10.692 ;
     RECT  15.431 12.87 16.547 13.392 ;
     RECT  15.431 14.922 16.547 17.64 ;
     RECT  15.431 18.54 16.547 18.558 ;
     RECT  16.007 19.62 16.547 21.762 ;
     RECT  15.467 23.832 16.547 23.85 ;
     RECT  15.503 25.02 16.547 25.038 ;
     RECT  15.503 25.83 16.547 26.82 ;
     RECT  16.007 30.078 16.547 31.518 ;
     RECT  15.431 33.39 16.547 33.408 ;
     RECT  15.467 35.55 16.547 36.036 ;
     RECT  15.431 37.602 16.547 37.764 ;
     RECT  15.431 38.718 16.547 38.736 ;
     RECT  15.431 39.906 16.547 39.924 ;
     RECT  15.467 41.49 16.547 42.48 ;
     RECT  15.431 43.272 16.547 44.982 ;
     RECT  15.431 47.43 16.547 48.42 ;
     RECT  15.467 49.248 16.547 50.418 ;
     RECT  16.007 51.642 16.547 52.542 ;
     RECT  15.431 54.45 16.547 54.468 ;
     RECT  16.511 55.26 16.547 55.278 ;
     RECT  15.467 56.538 16.547 57.366 ;
     RECT  15.467 59.04 16.547 59.058 ;
     RECT  15.431 60.588 16.547 61.38 ;
     RECT  16.007 62.172 16.547 62.874 ;
     RECT  16.007 64.332 16.547 64.35 ;
     RECT  16.007 65.754 16.547 65.772 ;
     RECT  15.503 66.834 16.547 66.852 ;
     RECT  15.467 69.534 16.547 69.552 ;
     RECT  15.431 71.082 16.547 71.784 ;
     RECT  15.431 72.54 16.547 73.062 ;
     RECT  16.547 10.17 16.583 10.188 ;
     RECT  15.12 11.754 16.583 12.078 ;
     RECT  16.547 16.308 16.583 16.596 ;
     RECT  16.547 19.89 16.583 20.106 ;
     RECT  16.547 26.064 16.583 26.082 ;
     RECT  16.547 41.49 16.583 42.354 ;
     RECT  16.547 43.416 16.583 43.749 ;
     RECT  16.547 44.73 16.583 44.748 ;
     RECT  16.547 71.766 16.583 71.784 ;
     RECT  16.547 72.738 16.583 73.062 ;
     RECT  16.547 30.078 16.619 30.789 ;
     RECT  16.583 43.65 16.619 43.749 ;
     RECT  16.583 11.916 16.655 11.934 ;
     RECT  16.583 41.49 17.059 41.67 ;
     RECT  15.467 46.35 17.059 46.368 ;
     RECT  16.547 47.7 17.059 48.42 ;
     RECT  16.547 50.211 17.059 50.418 ;
     RECT  16.547 51.642 17.059 51.696 ;
     RECT  17.059 2.772 17.159 2.79 ;
     RECT  17.059 5.274 17.159 5.292 ;
     RECT  17.059 7.128 17.159 7.146 ;
     RECT  17.059 9.252 17.159 9.27 ;
     RECT  17.059 12.798 17.159 12.816 ;
     RECT  17.059 13.608 17.159 13.626 ;
     RECT  16.583 16.578 17.159 16.596 ;
     RECT  17.059 17.811 17.159 17.982 ;
     RECT  16.583 20.088 17.159 20.106 ;
     RECT  16.547 20.898 17.159 21.186 ;
     RECT  17.059 24.066 17.159 24.084 ;
     RECT  17.059 27.99 17.159 28.71 ;
     RECT  17.059 32.238 17.159 32.256 ;
     RECT  17.059 33.282 17.159 33.3 ;
     RECT  17.059 34.902 17.159 34.92 ;
     RECT  17.059 39.528 17.159 39.78 ;
     RECT  17.059 41.382 17.159 41.67 ;
     RECT  16.619 43.731 17.159 43.749 ;
     RECT  17.059 46.008 17.159 46.638 ;
     RECT  17.059 47.7 17.159 49.194 ;
     RECT  17.059 50.211 17.159 51.696 ;
     RECT  17.059 56.034 17.159 56.052 ;
     RECT  16.547 56.844 17.159 57.132 ;
     RECT  16.547 61.092 17.159 61.11 ;
     RECT  17.059 66.258 17.159 66.546 ;
     RECT  17.059 67.374 17.159 67.392 ;
     RECT  17.059 68.148 17.159 68.166 ;
     RECT  16.583 72.738 17.159 72.756 ;
    LAYER M3 ;
     RECT  8.1 1.957 8.118 2.029 ;
     RECT  7.668 2.029 8.118 2.065 ;
     RECT  15.984 2.029 16.002 2.065 ;
     RECT  2.844 2.029 2.862 2.101 ;
     RECT  7.668 2.065 8.262 2.101 ;
     RECT  14.508 1.993 14.526 2.101 ;
     RECT  2.664 2.101 2.862 2.129 ;
     RECT  2.664 2.129 2.697 2.143 ;
     RECT  5.652 2.101 5.67 2.143 ;
     RECT  12.708 1.993 12.726 2.143 ;
     RECT  13.824 2.101 14.526 2.143 ;
     RECT  2.415 2.143 2.697 2.191 ;
     RECT  10.515 2.143 10.605 2.191 ;
     RECT  15.984 2.065 16.542 2.203 ;
     RECT  5.115 2.143 5.67 2.263 ;
     RECT  7.596 2.101 8.262 2.299 ;
     RECT  9.468 2.251 9.486 2.299 ;
     RECT  10.515 2.191 11.178 2.299 ;
     RECT  6.768 1.957 6.786 2.335 ;
     RECT  7.596 2.299 11.718 2.335 ;
     RECT  12.708 2.143 14.526 2.335 ;
     RECT  4.536 2.263 5.67 2.347 ;
     RECT  15.408 2.203 16.542 2.381 ;
     RECT  6.624 2.335 14.526 2.461 ;
     RECT  15.408 2.381 16.002 2.461 ;
     RECT  0.216 2.443 0.234 2.491 ;
     RECT  4.464 2.347 5.67 2.533 ;
     RECT  6.624 2.461 16.002 2.533 ;
     RECT  4.464 2.533 16.002 2.573 ;
     RECT  3.564 2.461 3.582 2.587 ;
     RECT  4.464 2.573 15.426 2.587 ;
     RECT  0.216 2.491 0.342 2.731 ;
     RECT  3.564 2.587 15.426 2.759 ;
     RECT  17.064 2.731 17.082 2.767 ;
     RECT  3.564 2.759 13.842 2.813 ;
     RECT  17.064 2.767 17.154 2.813 ;
     RECT  0.216 2.731 0.414 2.861 ;
     RECT  2.304 2.191 2.697 3.001 ;
     RECT  0.216 2.861 0.342 3.005 ;
     RECT  3.564 2.813 5.922 3.029 ;
     RECT  0.252 3.005 0.342 3.053 ;
     RECT  2.304 3.001 2.754 3.064 ;
     RECT  3.564 3.029 5.742 3.064 ;
     RECT  2.304 3.064 5.742 3.163 ;
     RECT  2.268 3.163 5.742 3.299 ;
     RECT  7.272 2.813 13.842 3.335 ;
     RECT  2.304 3.299 5.742 3.407 ;
     RECT  14.832 2.759 15.426 3.407 ;
     RECT  16.524 3.451 16.542 3.676 ;
     RECT  16.488 3.676 16.542 3.725 ;
     RECT  0.252 3.053 0.27 3.821 ;
     RECT  2.304 3.407 4.338 3.839 ;
     RECT  5.115 3.407 5.742 3.839 ;
     RECT  7.344 3.335 13.842 3.869 ;
     RECT  7.344 3.869 13.734 3.983 ;
     RECT  2.304 3.839 3.33 4.019 ;
     RECT  0.54 3.955 0.558 4.109 ;
     RECT  6.264 4.081 6.282 4.253 ;
     RECT  4.104 3.839 4.338 4.261 ;
     RECT  5.115 3.839 5.397 4.261 ;
     RECT  7.344 3.983 13.662 4.495 ;
     RECT  7.308 4.495 13.662 4.541 ;
     RECT  2.304 4.019 3.294 4.559 ;
     RECT  4.104 4.261 5.397 4.621 ;
     RECT  14.832 3.407 14.922 4.651 ;
     RECT  16.524 3.725 16.542 4.685 ;
     RECT  7.344 4.541 13.662 4.729 ;
     RECT  14.832 4.651 15.03 4.729 ;
     RECT  4.104 4.621 5.454 4.765 ;
     RECT  2.304 4.559 2.697 4.828 ;
     RECT  3.42 4.765 5.454 4.829 ;
     RECT  2.268 4.828 2.697 4.919 ;
     RECT  7.344 4.729 15.03 4.919 ;
     RECT  7.344 4.919 13.842 4.973 ;
     RECT  3.42 4.829 4.374 5.063 ;
     RECT  3.42 5.063 4.23 5.189 ;
     RECT  12.24 4.973 13.842 5.213 ;
     RECT  17.064 5.227 17.082 5.269 ;
     RECT  17.064 5.269 17.154 5.309 ;
     RECT  2.304 4.919 2.697 5.341 ;
     RECT  3.42 5.189 4.158 5.341 ;
     RECT  7.344 4.973 11.214 5.611 ;
     RECT  5.115 4.829 5.397 5.701 ;
     RECT  7.236 5.611 11.214 5.755 ;
     RECT  14.832 4.919 15.03 5.755 ;
     RECT  5.115 5.701 5.562 5.837 ;
     RECT  5.115 5.837 5.397 5.881 ;
     RECT  2.304 5.341 4.158 5.971 ;
     RECT  5.004 5.881 5.397 5.971 ;
     RECT  12.24 5.213 13.554 5.971 ;
     RECT  7.128 5.755 11.214 6.043 ;
     RECT  12.24 5.971 13.842 6.043 ;
     RECT  6.228 6.043 6.246 6.079 ;
     RECT  7.128 6.043 13.842 6.079 ;
     RECT  6.228 6.079 13.842 6.179 ;
     RECT  7.164 6.179 13.842 6.221 ;
     RECT  14.832 5.755 15.426 6.313 ;
     RECT  7.236 6.221 13.842 6.691 ;
     RECT  14.616 6.313 15.426 6.691 ;
     RECT  7.236 6.691 15.426 6.809 ;
     RECT  14.508 6.809 15.426 6.845 ;
     RECT  2.304 5.971 5.397 6.961 ;
     RECT  7.236 6.809 13.734 6.961 ;
     RECT  2.268 6.961 5.397 7.037 ;
     RECT  2.304 7.037 5.397 7.079 ;
     RECT  16.524 5.563 16.542 7.099 ;
     RECT  16.524 7.099 17.154 7.151 ;
     RECT  16.524 7.151 17.082 7.181 ;
     RECT  2.304 7.079 2.79 7.373 ;
     RECT  3.528 7.079 5.397 7.385 ;
     RECT  7.128 6.961 13.734 7.387 ;
     RECT  6.84 7.387 13.734 7.427 ;
     RECT  3.672 7.385 5.397 7.675 ;
     RECT  3.672 7.675 5.706 7.691 ;
     RECT  7.344 7.427 13.734 7.723 ;
     RECT  5.115 7.691 5.706 7.735 ;
     RECT  7.344 7.723 13.842 7.757 ;
     RECT  7.38 7.757 13.842 7.861 ;
     RECT  14.832 6.845 15.426 7.861 ;
     RECT  5.115 7.735 5.922 7.889 ;
     RECT  7.38 7.861 15.426 7.961 ;
     RECT  1.26 7.867 1.278 7.963 ;
     RECT  1.152 7.963 1.278 7.997 ;
     RECT  3.672 7.691 4.374 7.997 ;
     RECT  2.304 7.373 2.697 8.155 ;
     RECT  3.672 7.997 4.086 8.155 ;
     RECT  1.152 7.997 1.17 8.237 ;
     RECT  16.524 7.181 16.542 8.525 ;
     RECT  2.304 8.155 4.086 8.671 ;
     RECT  7.416 7.961 15.426 8.699 ;
     RECT  2.268 8.671 4.086 8.717 ;
     RECT  2.304 8.717 4.086 8.771 ;
     RECT  5.115 7.889 5.706 8.771 ;
     RECT  3.708 8.771 4.086 8.779 ;
     RECT  5.115 8.771 5.397 8.779 ;
     RECT  3.708 8.779 5.397 8.879 ;
     RECT  17.064 9.211 17.082 9.247 ;
     RECT  7.416 8.699 13.842 9.259 ;
     RECT  17.064 9.247 17.154 9.283 ;
     RECT  16.524 9.283 17.154 9.293 ;
     RECT  6.804 9.259 13.842 9.617 ;
     RECT  7.344 9.617 13.842 9.677 ;
     RECT  4.068 8.879 5.397 9.751 ;
     RECT  14.832 8.699 15.426 9.851 ;
     RECT  3.996 9.751 5.397 9.883 ;
     RECT  2.304 8.771 2.97 9.895 ;
     RECT  3.816 9.883 5.397 9.895 ;
     RECT  0.252 9.787 0.27 10.123 ;
     RECT  16.524 9.293 16.578 10.171 ;
     RECT  15.984 10.171 16.578 10.193 ;
     RECT  12.528 9.677 13.842 10.291 ;
     RECT  0.252 10.123 0.306 10.348 ;
     RECT  7.344 9.677 11.79 10.411 ;
     RECT  15.984 10.193 16.542 10.463 ;
     RECT  7.236 10.411 11.79 10.555 ;
     RECT  12.528 10.291 13.986 10.555 ;
     RECT  0.216 10.348 0.306 10.589 ;
     RECT  14.832 9.851 14.85 10.603 ;
     RECT  0.252 10.589 0.306 10.637 ;
     RECT  14.832 10.603 15.426 10.733 ;
     RECT  0.252 10.637 0.27 10.829 ;
     RECT  2.304 9.895 5.397 10.867 ;
     RECT  6.228 10.471 6.246 10.867 ;
     RECT  7.236 10.555 13.986 10.867 ;
     RECT  2.304 10.867 6.246 10.933 ;
     RECT  7.02 10.867 13.986 10.933 ;
     RECT  2.304 10.933 13.986 10.939 ;
     RECT  14.832 10.733 15.102 11.003 ;
     RECT  2.304 10.939 14.058 11.281 ;
     RECT  14.832 11.003 14.886 11.281 ;
     RECT  0.54 11.371 0.558 11.453 ;
     RECT  2.304 11.281 14.886 11.471 ;
     RECT  16.524 10.463 16.542 11.611 ;
     RECT  5.004 11.471 14.886 11.669 ;
     RECT  5.115 11.669 14.886 11.821 ;
     RECT  5.115 11.821 15.426 11.849 ;
     RECT  7.416 11.849 15.426 11.885 ;
     RECT  16.524 11.611 16.578 11.911 ;
     RECT  7.416 11.885 14.958 11.975 ;
     RECT  14.832 11.975 14.958 12.281 ;
     RECT  2.304 11.471 4.23 12.331 ;
     RECT  2.304 12.331 4.338 12.451 ;
     RECT  5.115 11.849 6.318 12.451 ;
     RECT  2.304 12.451 6.318 12.479 ;
     RECT  2.304 12.479 6.066 12.515 ;
     RECT  7.416 11.975 13.986 12.595 ;
     RECT  7.344 12.595 13.986 12.721 ;
     RECT  14.832 12.281 14.886 12.721 ;
     RECT  16.524 11.911 16.65 12.763 ;
     RECT  16.524 12.763 17.082 12.793 ;
     RECT  16.524 12.793 17.154 12.845 ;
     RECT  0.252 11.995 0.27 12.989 ;
     RECT  16.524 12.845 16.542 13.063 ;
     RECT  7.344 12.721 14.886 13.099 ;
     RECT  15.984 13.063 16.542 13.133 ;
     RECT  7.2 13.099 14.886 13.483 ;
     RECT  7.2 13.483 15.426 13.531 ;
     RECT  2.304 12.515 5.397 13.559 ;
     RECT  6.732 13.531 15.426 13.559 ;
     RECT  16.524 13.133 16.542 13.579 ;
     RECT  16.524 13.579 17.154 13.631 ;
     RECT  6.732 13.559 14.058 13.661 ;
     RECT  16.524 13.631 17.082 13.661 ;
     RECT  6.84 13.661 14.058 14.099 ;
     RECT  2.304 13.559 4.266 14.395 ;
     RECT  5.115 13.559 5.397 14.395 ;
     RECT  6.84 14.099 14.022 14.917 ;
     RECT  14.832 13.559 15.426 14.917 ;
     RECT  0.252 14.395 0.27 14.957 ;
     RECT  2.304 14.395 5.397 14.957 ;
     RECT  6.624 14.917 15.426 14.989 ;
     RECT  6.372 14.989 15.426 15.323 ;
     RECT  6.624 15.323 15.426 15.389 ;
     RECT  6.696 15.389 15.426 15.592 ;
     RECT  2.304 14.957 3.762 15.691 ;
     RECT  2.268 15.691 3.762 15.719 ;
     RECT  5.115 14.957 5.397 15.727 ;
     RECT  3.816 15.763 3.834 15.787 ;
     RECT  2.268 15.719 3.078 15.791 ;
     RECT  3.816 15.787 3.942 15.821 ;
     RECT  4.968 15.727 5.397 15.835 ;
     RECT  3.924 15.821 3.942 15.899 ;
     RECT  0.216 15.871 0.234 15.917 ;
     RECT  6.696 15.592 15.462 16.097 ;
     RECT  4.968 15.835 5.886 16.231 ;
     RECT  16.524 13.661 16.542 16.303 ;
     RECT  4.212 16.231 5.886 16.375 ;
     RECT  6.696 16.097 15.426 16.375 ;
     RECT  4.212 16.375 15.426 16.439 ;
     RECT  4.212 16.439 6.282 16.541 ;
     RECT  16.524 16.303 16.578 16.555 ;
     RECT  16.524 16.555 17.082 16.573 ;
     RECT  0.54 16.339 0.558 16.637 ;
     RECT  16.524 16.573 17.154 16.637 ;
     RECT  4.212 16.541 5.814 16.651 ;
     RECT  2.304 15.791 3.078 16.795 ;
     RECT  14.796 16.439 15.426 16.877 ;
     RECT  2.304 16.795 3.114 16.951 ;
     RECT  3.996 16.651 5.814 16.951 ;
     RECT  0.252 16.651 0.27 17.069 ;
     RECT  2.304 16.951 5.814 17.069 ;
     RECT  7.2 16.439 13.842 17.221 ;
     RECT  14.796 16.877 15.03 17.221 ;
     RECT  7.2 17.221 15.03 17.311 ;
     RECT  6.984 17.311 15.03 17.405 ;
     RECT  6.408 17.455 6.426 17.501 ;
     RECT  7.2 17.405 15.03 17.609 ;
     RECT  0.54 17.563 0.594 17.611 ;
     RECT  16.524 16.637 16.542 17.645 ;
     RECT  0.54 17.611 0.666 17.651 ;
     RECT  7.344 17.609 15.03 17.707 ;
     RECT  2.304 17.069 5.397 17.755 ;
     RECT  2.268 17.755 5.397 17.879 ;
     RECT  7.344 17.707 15.426 17.951 ;
     RECT  17.064 17.755 17.154 17.987 ;
     RECT  17.064 17.987 17.082 18.029 ;
     RECT  7.416 17.951 15.426 18.227 ;
     RECT  2.412 17.879 4.374 18.269 ;
     RECT  0.54 17.651 0.558 18.317 ;
     RECT  7.416 18.227 14.958 18.455 ;
     RECT  4.14 18.269 4.374 18.563 ;
     RECT  16.524 18.427 16.614 18.563 ;
     RECT  2.412 18.269 3.402 18.619 ;
     RECT  12.456 18.455 14.958 18.689 ;
     RECT  12.456 18.689 13.842 18.725 ;
     RECT  7.416 18.455 11.358 18.733 ;
     RECT  4.14 18.563 4.158 18.749 ;
     RECT  12.492 18.725 13.842 18.761 ;
     RECT  14.832 18.689 14.958 18.797 ;
     RECT  5.112 17.879 5.397 18.805 ;
     RECT  5.112 18.805 5.778 18.841 ;
     RECT  16.56 18.563 16.614 18.893 ;
     RECT  5.112 18.841 5.814 18.931 ;
     RECT  7.308 18.733 11.358 19.003 ;
     RECT  4.896 18.931 5.814 19.075 ;
     RECT  6.804 19.003 11.358 19.075 ;
     RECT  4.896 19.075 11.358 19.085 ;
     RECT  2.304 18.619 3.402 19.201 ;
     RECT  4.896 19.085 6.57 19.337 ;
     RECT  16.56 18.893 16.578 19.339 ;
     RECT  2.304 19.201 4.122 19.471 ;
     RECT  4.896 19.337 5.397 19.471 ;
     RECT  14.832 18.797 14.85 19.579 ;
     RECT  7.308 19.085 11.358 19.615 ;
     RECT  7.308 19.615 11.718 19.627 ;
     RECT  12.564 18.761 13.842 19.627 ;
     RECT  6.408 19.337 6.57 19.661 ;
     RECT  7.308 19.627 13.842 19.741 ;
     RECT  14.832 19.579 14.886 19.771 ;
     RECT  6.552 19.661 6.57 19.949 ;
     RECT  14.832 19.771 14.958 20.011 ;
     RECT  7.308 19.741 13.914 20.047 ;
     RECT  16.524 19.339 16.578 20.059 ;
     RECT  16.524 20.059 17.154 20.111 ;
     RECT  16.524 20.111 17.082 20.141 ;
     RECT  0.396 20.059 0.414 20.155 ;
     RECT  0.288 20.155 0.414 20.189 ;
     RECT  2.304 19.471 5.397 20.191 ;
     RECT  2.304 20.191 5.454 20.309 ;
     RECT  14.832 20.011 15.426 20.317 ;
     RECT  0.288 20.189 0.306 20.333 ;
     RECT  5.115 20.309 5.454 20.353 ;
     RECT  14.796 20.317 15.426 20.417 ;
     RECT  14.832 20.417 15.426 20.525 ;
     RECT  5.115 20.353 5.526 20.849 ;
     RECT  16.524 20.141 16.542 20.875 ;
     RECT  6.804 20.047 13.914 20.921 ;
     RECT  0.252 20.875 0.27 21.053 ;
     RECT  2.304 20.309 4.014 21.091 ;
     RECT  5.115 20.849 5.397 21.091 ;
     RECT  6.804 20.921 13.734 21.091 ;
     RECT  6.264 21.091 13.734 21.149 ;
     RECT  16.524 20.875 17.154 21.2 ;
     RECT  2.304 21.091 5.397 21.532 ;
     RECT  2.268 21.532 5.397 21.659 ;
     RECT  0.54 21.541 0.558 21.677 ;
     RECT  14.868 20.525 15.426 21.691 ;
     RECT  2.304 21.659 5.397 21.695 ;
     RECT  3.42 21.695 5.397 21.739 ;
     RECT  6.264 21.149 13.626 21.739 ;
     RECT  16.524 21.2 16.542 21.767 ;
     RECT  14.832 21.691 15.426 21.811 ;
     RECT  3.42 21.739 13.626 21.937 ;
     RECT  14.4 21.811 15.426 21.937 ;
     RECT  3.42 21.937 15.426 22.081 ;
     RECT  3.42 22.081 16.002 22.199 ;
     RECT  6.804 22.199 16.002 22.235 ;
     RECT  6.804 22.235 14.058 22.253 ;
     RECT  14.832 22.235 16.002 22.301 ;
     RECT  2.304 21.695 2.697 22.549 ;
     RECT  3.42 22.199 5.634 22.549 ;
     RECT  2.304 22.549 5.634 22.781 ;
     RECT  0.54 22.711 0.558 22.829 ;
     RECT  6.804 22.253 13.914 22.981 ;
     RECT  14.832 22.301 15.426 22.981 ;
     RECT  16.524 22.555 16.542 23.083 ;
     RECT  6.804 22.981 15.426 23.161 ;
     RECT  2.304 22.781 5.397 23.179 ;
     RECT  2.268 23.179 5.397 23.279 ;
     RECT  6.804 23.161 15.462 23.279 ;
     RECT  6.804 23.279 14.454 23.315 ;
     RECT  2.304 23.279 5.397 23.357 ;
     RECT  15.408 23.279 15.462 23.357 ;
     RECT  0.216 23.515 0.234 23.563 ;
     RECT  4.824 23.357 5.397 23.611 ;
     RECT  4.824 23.611 5.958 23.665 ;
     RECT  6.804 23.315 13.842 23.665 ;
     RECT  4.824 23.665 13.842 23.933 ;
     RECT  16.524 23.083 16.578 24.043 ;
     RECT  16.524 24.043 17.082 24.061 ;
     RECT  0.216 23.563 0.306 24.077 ;
     RECT  0.288 24.077 0.306 24.125 ;
     RECT  16.524 24.061 17.154 24.125 ;
     RECT  15.408 23.357 15.426 24.139 ;
     RECT  14.832 24.139 15.426 24.187 ;
     RECT  14.832 24.187 15.462 24.233 ;
     RECT  6.228 23.933 13.842 24.241 ;
     RECT  2.304 23.357 4.05 24.331 ;
     RECT  4.824 23.933 5.397 24.331 ;
     RECT  6.228 24.241 13.914 24.331 ;
     RECT  6.228 24.331 13.95 24.359 ;
     RECT  6.732 24.359 13.95 24.461 ;
     RECT  2.304 24.331 5.397 24.467 ;
     RECT  6.84 24.461 13.95 24.509 ;
     RECT  6.84 24.509 13.497 24.773 ;
     RECT  2.304 24.467 3.114 24.899 ;
     RECT  3.96 24.467 5.397 24.899 ;
     RECT  6.912 24.773 13.497 25.085 ;
     RECT  4.104 24.899 5.397 25.141 ;
     RECT  4.104 25.141 5.454 25.169 ;
     RECT  14.832 24.233 15.426 25.195 ;
     RECT  14.832 25.195 15.498 25.313 ;
     RECT  7.128 25.085 13.497 25.321 ;
     RECT  14.832 25.313 15.426 25.321 ;
     RECT  4.14 25.169 5.454 25.483 ;
     RECT  7.128 25.321 13.842 25.511 ;
     RECT  4.14 25.483 5.634 25.709 ;
     RECT  16.524 24.125 16.542 25.819 ;
     RECT  16.524 25.819 16.578 25.853 ;
     RECT  7.2 25.511 13.842 25.861 ;
     RECT  14.58 25.321 15.426 25.861 ;
     RECT  4.14 25.709 5.526 25.951 ;
     RECT  16.56 25.853 16.578 26.087 ;
     RECT  4.104 25.951 5.526 26.107 ;
     RECT  7.2 25.861 15.426 26.251 ;
     RECT  6.84 26.251 15.426 26.299 ;
     RECT  6.264 26.299 15.426 26.429 ;
     RECT  3.744 26.107 5.526 26.563 ;
     RECT  6.264 26.429 13.842 26.563 ;
     RECT  2.304 24.899 2.862 26.587 ;
     RECT  3.744 26.563 13.842 26.587 ;
     RECT  2.304 26.587 13.842 26.627 ;
     RECT  0.252 25.915 0.27 26.761 ;
     RECT  3.744 26.627 13.842 26.789 ;
     RECT  16.524 26.683 16.542 26.825 ;
     RECT  3.96 26.789 5.454 26.969 ;
     RECT  14.616 26.429 15.426 27.059 ;
     RECT  6.228 26.789 13.842 27.239 ;
     RECT  0.252 26.761 0.558 27.293 ;
     RECT  6.804 27.239 13.842 27.301 ;
     RECT  0.54 27.293 0.558 27.389 ;
     RECT  2.304 26.627 2.898 27.499 ;
     RECT  3.96 26.969 5.397 27.595 ;
     RECT  2.268 27.499 2.898 27.677 ;
     RECT  2.304 27.677 2.898 27.751 ;
     RECT  3.852 27.595 5.397 27.751 ;
     RECT  6.804 27.301 14.022 27.779 ;
     RECT  7.128 27.779 14.022 27.821 ;
     RECT  7.344 27.821 14.022 27.841 ;
     RECT  14.832 27.059 15.426 27.841 ;
     RECT  2.304 27.751 5.397 27.917 ;
     RECT  4.68 27.917 5.397 27.949 ;
     RECT  7.344 27.841 15.426 27.965 ;
     RECT  17.136 27.976 17.154 27.985 ;
     RECT  4.68 27.949 5.778 28.409 ;
     RECT  5.115 28.409 5.778 28.561 ;
     RECT  17.064 27.985 17.154 28.715 ;
     RECT  5.115 28.561 6.282 28.733 ;
     RECT  17.136 28.715 17.154 28.733 ;
     RECT  7.344 27.965 14.922 28.747 ;
     RECT  2.304 27.917 3.942 28.787 ;
     RECT  3.924 28.787 3.942 28.795 ;
     RECT  0.288 28.795 0.306 28.843 ;
     RECT  5.115 28.733 5.886 28.949 ;
     RECT  7.344 28.747 15.426 28.985 ;
     RECT  0.216 28.843 0.306 29.093 ;
     RECT  0.252 29.093 0.306 29.131 ;
     RECT  7.344 28.985 11.43 29.227 ;
     RECT  0.252 29.131 0.414 29.261 ;
     RECT  0.252 29.261 0.306 29.357 ;
     RECT  3.924 28.795 4.266 29.489 ;
     RECT  12.168 28.985 15.426 29.489 ;
     RECT  7.056 29.227 11.43 29.549 ;
     RECT  5.115 28.949 5.397 29.563 ;
     RECT  2.304 28.787 3.186 29.731 ;
     RECT  14.832 29.489 15.426 29.803 ;
     RECT  0.252 29.357 0.27 29.837 ;
     RECT  12.168 29.489 13.914 29.837 ;
     RECT  14.832 29.803 15.498 29.903 ;
     RECT  7.344 29.549 11.43 29.911 ;
     RECT  12.168 29.837 13.842 29.911 ;
     RECT  16.524 29.899 16.542 30.073 ;
     RECT  2.304 29.731 3.51 30.187 ;
     RECT  7.344 29.911 13.842 30.283 ;
     RECT  2.268 30.187 3.51 30.299 ;
     RECT  2.304 30.299 3.51 30.451 ;
     RECT  4.32 29.563 5.397 30.451 ;
     RECT  7.092 30.283 13.842 30.605 ;
     RECT  12.024 30.605 13.842 30.653 ;
     RECT  2.304 30.451 5.397 30.713 ;
     RECT  16.524 30.073 16.614 30.794 ;
     RECT  14.832 29.903 14.85 30.811 ;
     RECT  7.092 30.605 11.178 30.847 ;
     RECT  7.056 30.847 11.178 30.859 ;
     RECT  0.396 30.811 0.414 30.907 ;
     RECT  6.984 30.859 11.178 30.911 ;
     RECT  14.832 30.811 14.922 30.911 ;
     RECT  0.288 30.907 0.414 30.941 ;
     RECT  2.304 30.713 4.374 31.019 ;
     RECT  14.868 30.911 14.922 31.051 ;
     RECT  0.288 30.941 0.306 31.133 ;
     RECT  12.024 30.653 13.806 31.145 ;
     RECT  14.868 31.051 15.426 31.253 ;
     RECT  0.216 31.339 0.234 31.379 ;
     RECT  3.816 31.019 4.374 31.379 ;
     RECT  5.115 30.713 5.397 31.495 ;
     RECT  16.524 30.794 16.542 31.523 ;
     RECT  12.456 31.145 13.806 31.531 ;
     RECT  14.868 31.253 14.958 31.675 ;
     RECT  5.115 31.495 5.742 31.757 ;
     RECT  7.056 30.911 11.178 31.801 ;
     RECT  7.056 31.801 11.214 31.915 ;
     RECT  12.456 31.531 13.914 31.915 ;
     RECT  2.304 31.019 3.042 31.927 ;
     RECT  3.816 31.379 4.266 31.927 ;
     RECT  14.832 31.675 14.958 31.927 ;
     RECT  6.804 31.915 11.214 31.963 ;
     RECT  12.06 31.915 13.914 31.963 ;
     RECT  14.796 31.927 14.958 32.107 ;
     RECT  15.984 32.071 16.002 32.107 ;
     RECT  6.804 31.963 13.914 32.161 ;
     RECT  14.796 32.107 16.002 32.161 ;
     RECT  6.804 32.161 16.002 32.203 ;
     RECT  17.064 32.203 17.082 32.233 ;
     RECT  2.304 31.927 4.266 32.251 ;
     RECT  17.064 32.233 17.154 32.261 ;
     RECT  0.288 32.155 0.306 32.285 ;
     RECT  17.136 32.261 17.154 32.285 ;
     RECT  5.115 31.757 5.397 32.305 ;
     RECT  6.768 32.203 16.002 32.369 ;
     RECT  12.564 32.369 16.002 32.431 ;
     RECT  2.304 32.251 4.302 32.491 ;
     RECT  5.04 32.305 5.397 32.491 ;
     RECT  12.564 32.431 16.038 32.573 ;
     RECT  2.304 32.491 5.397 32.575 ;
     RECT  2.304 32.575 6.03 32.701 ;
     RECT  6.768 32.369 11.718 32.701 ;
     RECT  2.304 32.701 11.718 32.729 ;
     RECT  6.552 32.729 11.718 32.765 ;
     RECT  2.304 32.729 3.51 32.999 ;
     RECT  6.588 32.765 11.718 33.115 ;
     RECT  12.564 32.573 15.426 33.115 ;
     RECT  16.524 33.163 16.542 33.259 ;
     RECT  16.524 33.259 17.082 33.277 ;
     RECT  16.524 33.277 17.154 33.341 ;
     RECT  16.524 33.341 16.542 33.413 ;
     RECT  4.248 32.729 5.67 33.539 ;
     RECT  6.588 33.115 15.426 33.539 ;
     RECT  2.304 32.999 3.474 33.781 ;
     RECT  4.248 33.539 5.526 33.781 ;
     RECT  6.588 33.539 14.058 33.817 ;
     RECT  1.368 33.739 1.386 33.869 ;
     RECT  2.304 33.781 5.526 33.989 ;
     RECT  6.264 33.817 14.058 33.989 ;
     RECT  12.06 33.989 14.058 34.079 ;
     RECT  6.264 33.989 11.214 34.493 ;
     RECT  2.304 33.989 5.397 34.619 ;
     RECT  6.768 34.493 11.214 34.771 ;
     RECT  12.06 34.079 13.806 34.771 ;
     RECT  17.136 34.888 17.154 34.897 ;
     RECT  17.064 34.897 17.154 34.925 ;
     RECT  0.252 34.795 0.27 34.973 ;
     RECT  3.996 34.619 5.397 34.973 ;
     RECT  6.768 34.771 13.806 34.973 ;
     RECT  17.064 34.925 17.082 34.973 ;
     RECT  4.752 34.973 5.397 35.033 ;
     RECT  6.84 34.973 13.806 35.165 ;
     RECT  7.344 35.165 13.806 35.195 ;
     RECT  1.152 33.931 1.17 35.261 ;
     RECT  14.832 33.539 15.426 35.303 ;
     RECT  3.996 34.973 4.014 35.453 ;
     RECT  4.788 35.033 5.397 35.453 ;
     RECT  7.452 35.195 13.806 35.473 ;
     RECT  14.832 35.303 14.85 35.473 ;
     RECT  4.86 35.453 5.397 35.501 ;
     RECT  5.115 35.501 5.397 35.545 ;
     RECT  2.304 34.619 3.078 35.707 ;
     RECT  2.304 35.707 3.114 36.013 ;
     RECT  16.524 35.467 16.542 36.041 ;
     RECT  7.452 35.473 14.85 36.049 ;
     RECT  7.452 36.049 14.922 36.085 ;
     RECT  6.912 36.085 14.922 36.091 ;
     RECT  5.115 35.545 6.03 36.121 ;
     RECT  6.912 36.091 15.426 36.121 ;
     RECT  2.304 36.013 3.51 36.211 ;
     RECT  5.115 36.121 15.426 36.239 ;
     RECT  2.304 36.211 4.014 36.283 ;
     RECT  14.832 36.239 15.426 36.283 ;
     RECT  14.832 36.283 15.462 36.383 ;
     RECT  5.115 36.239 13.914 36.413 ;
     RECT  1.152 36.283 1.17 36.461 ;
     RECT  6.228 36.413 13.914 36.617 ;
     RECT  6.804 36.617 13.914 36.689 ;
     RECT  5.115 36.413 5.397 36.751 ;
     RECT  2.304 36.283 4.23 37.021 ;
     RECT  5.076 36.751 5.397 37.021 ;
     RECT  14.832 36.383 15.426 37.391 ;
     RECT  6.84 36.689 13.914 37.579 ;
     RECT  2.304 37.021 5.397 37.597 ;
     RECT  6.264 37.579 13.914 37.705 ;
     RECT  14.832 37.391 14.886 37.705 ;
     RECT  6.264 37.705 14.886 38.137 ;
     RECT  6.264 38.137 15.426 38.189 ;
     RECT  14.292 38.189 14.886 38.201 ;
     RECT  2.304 37.597 5.418 38.371 ;
     RECT  6.264 38.189 13.554 38.371 ;
     RECT  0.252 38.251 0.27 38.381 ;
     RECT  2.304 38.371 13.554 38.477 ;
     RECT  2.304 38.477 5.85 38.579 ;
     RECT  2.304 38.579 5.814 38.669 ;
     RECT  16.524 37.531 16.542 38.741 ;
     RECT  6.84 38.477 13.554 38.971 ;
     RECT  14.292 38.201 14.85 38.971 ;
     RECT  6.84 38.971 14.85 39.019 ;
     RECT  6.84 39.019 15.426 39.047 ;
     RECT  7.272 39.047 15.426 39.245 ;
     RECT  2.304 38.669 5.397 39.281 ;
     RECT  2.304 39.281 4.23 39.389 ;
     RECT  6.408 39.361 6.426 39.479 ;
     RECT  17.136 39.499 17.154 39.523 ;
     RECT  17.064 39.523 17.154 39.821 ;
     RECT  16.524 39.901 16.542 39.965 ;
     RECT  2.304 39.389 2.697 39.979 ;
     RECT  7.272 39.245 13.842 39.991 ;
     RECT  2.268 39.979 2.697 40.019 ;
     RECT  3.492 39.389 4.23 40.027 ;
     RECT  5.115 39.281 5.397 40.027 ;
     RECT  3.492 40.027 5.397 40.091 ;
     RECT  7.092 39.991 13.914 40.123 ;
     RECT  3.636 40.091 5.397 40.135 ;
     RECT  7.092 40.123 13.95 40.135 ;
     RECT  3.636 40.135 6.102 40.289 ;
     RECT  7.092 40.135 14.022 40.445 ;
     RECT  7.092 40.445 13.842 40.567 ;
     RECT  14.832 39.245 15.426 40.711 ;
     RECT  3.636 40.289 5.886 40.829 ;
     RECT  14.832 40.711 16.002 40.829 ;
     RECT  3.96 40.829 5.886 40.937 ;
     RECT  2.304 40.019 2.697 41.071 ;
     RECT  14.832 40.829 15.462 41.207 ;
     RECT  2.304 41.071 2.826 41.215 ;
     RECT  7.02 40.567 13.842 41.251 ;
     RECT  14.832 41.207 15.426 41.251 ;
     RECT  16.524 41.323 16.542 41.368 ;
     RECT  6.804 41.251 13.842 41.419 ;
     RECT  14.58 41.251 15.426 41.441 ;
     RECT  2.304 41.215 3.186 41.639 ;
     RECT  3.996 40.937 5.397 41.639 ;
     RECT  16.524 41.368 17.154 41.693 ;
     RECT  14.832 41.441 15.426 41.711 ;
     RECT  6.264 41.419 13.842 41.755 ;
     RECT  6.264 41.755 14.094 41.819 ;
     RECT  6.264 41.819 13.914 41.989 ;
     RECT  4.032 41.639 5.397 42.061 ;
     RECT  6.228 41.989 13.914 42.061 ;
     RECT  2.304 41.639 3.078 42.088 ;
     RECT  2.268 42.088 3.078 42.179 ;
     RECT  2.304 42.179 3.078 42.413 ;
     RECT  2.415 42.413 3.078 42.421 ;
     RECT  4.032 42.061 13.914 42.421 ;
     RECT  16.524 41.693 16.578 42.509 ;
     RECT  14.832 41.711 14.958 42.529 ;
     RECT  2.415 42.421 13.914 42.565 ;
     RECT  2.415 42.565 14.058 42.593 ;
     RECT  3.996 42.593 14.058 42.601 ;
     RECT  14.832 42.529 15.426 42.601 ;
     RECT  0.288 42.571 0.306 42.619 ;
     RECT  3.996 42.601 15.426 42.755 ;
     RECT  0.216 42.619 0.306 42.764 ;
     RECT  14.832 42.755 15.426 42.797 ;
     RECT  0.252 42.764 0.306 43.033 ;
     RECT  0.252 43.033 0.558 43.133 ;
     RECT  14.832 42.797 15.066 43.133 ;
     RECT  2.415 42.593 3.186 43.141 ;
     RECT  2.268 43.141 3.186 43.277 ;
     RECT  3.996 42.755 13.77 43.277 ;
     RECT  3.996 43.277 6.102 43.295 ;
     RECT  6.876 43.277 13.77 43.295 ;
     RECT  2.304 43.277 3.186 43.375 ;
     RECT  3.996 43.295 5.562 43.375 ;
     RECT  0.288 43.133 0.558 43.387 ;
     RECT  16.524 42.509 16.542 43.411 ;
     RECT  0.288 43.387 0.63 43.439 ;
     RECT  16.524 43.411 16.578 43.483 ;
     RECT  6.912 43.295 13.77 43.531 ;
     RECT  14.832 43.133 14.886 43.537 ;
     RECT  16.524 43.483 16.614 43.675 ;
     RECT  6.912 43.531 13.842 43.681 ;
     RECT  6.912 43.681 14.022 43.709 ;
     RECT  16.524 43.675 17.154 43.754 ;
     RECT  16.524 43.754 17.082 43.757 ;
     RECT  2.304 43.375 5.562 43.799 ;
     RECT  14.796 43.537 14.886 43.799 ;
     RECT  7.344 43.709 14.022 43.835 ;
     RECT  16.524 43.757 16.578 43.843 ;
     RECT  2.304 43.799 2.718 43.901 ;
     RECT  0.288 43.439 0.558 43.997 ;
     RECT  14.868 43.799 14.886 44.107 ;
     RECT  15.984 43.843 16.578 44.107 ;
     RECT  14.868 44.107 16.578 44.213 ;
     RECT  0.216 44.299 0.234 44.339 ;
     RECT  7.344 43.835 13.842 44.491 ;
     RECT  4.14 43.799 5.562 44.653 ;
     RECT  6.912 44.491 13.842 44.689 ;
     RECT  15.984 44.213 16.578 44.753 ;
     RECT  6.768 44.689 13.842 44.851 ;
     RECT  4.14 44.653 5.742 44.879 ;
     RECT  6.768 44.851 13.914 44.951 ;
     RECT  15.984 44.753 16.542 44.987 ;
     RECT  15.984 44.987 16.002 45.005 ;
     RECT  7.128 44.951 13.914 45.149 ;
     RECT  0.216 45.115 0.234 45.163 ;
     RECT  14.832 44.539 14.85 45.163 ;
     RECT  7.272 45.149 13.914 45.193 ;
     RECT  14.832 45.163 14.886 45.193 ;
     RECT  7.272 45.193 14.886 45.259 ;
     RECT  2.304 43.901 2.697 45.265 ;
     RECT  0.216 45.163 0.306 45.403 ;
     RECT  7.272 45.259 14.922 45.403 ;
     RECT  2.304 45.265 3.006 45.451 ;
     RECT  0.216 45.403 0.414 45.581 ;
     RECT  2.304 45.451 3.114 45.661 ;
     RECT  4.86 44.879 5.706 45.661 ;
     RECT  0.216 45.581 0.306 45.677 ;
     RECT  0.252 45.677 0.306 45.725 ;
     RECT  2.304 45.661 3.15 45.733 ;
     RECT  4.428 45.661 5.706 45.739 ;
     RECT  4.428 45.739 6.102 45.769 ;
     RECT  4.428 45.769 6.174 45.797 ;
     RECT  6.156 45.797 6.174 45.841 ;
     RECT  2.304 45.733 3.546 45.869 ;
     RECT  4.428 45.797 5.397 45.931 ;
     RECT  7.272 45.403 15.426 45.931 ;
     RECT  2.304 45.869 3.186 45.959 ;
     RECT  17.136 45.979 17.154 46.003 ;
     RECT  0.252 45.725 0.27 46.061 ;
     RECT  3.996 45.931 5.397 46.061 ;
     RECT  6.984 45.931 15.426 46.067 ;
     RECT  17.064 46.003 17.154 46.123 ;
     RECT  6.156 45.841 6.246 46.139 ;
     RECT  6.984 46.067 14.058 46.139 ;
     RECT  6.984 46.139 13.914 46.171 ;
     RECT  6.804 46.171 13.914 46.349 ;
     RECT  16.524 46.123 17.154 46.373 ;
     RECT  1.152 46.363 1.17 46.541 ;
     RECT  14.832 46.067 15.426 46.555 ;
     RECT  14.832 46.555 15.462 46.643 ;
     RECT  17.064 46.373 17.154 46.643 ;
     RECT  17.064 46.643 17.082 46.685 ;
     RECT  4.068 46.061 5.397 46.813 ;
     RECT  4.068 46.813 5.778 46.877 ;
     RECT  6.84 46.349 13.914 46.885 ;
     RECT  2.304 45.959 2.826 46.891 ;
     RECT  4.068 46.877 5.706 46.921 ;
     RECT  6.84 46.885 14.058 46.973 ;
     RECT  3.924 46.921 5.706 47.035 ;
     RECT  12.096 46.973 14.058 47.039 ;
     RECT  2.304 46.891 2.862 47.083 ;
     RECT  3.636 47.035 5.706 47.083 ;
     RECT  2.304 47.083 5.706 47.111 ;
     RECT  6.84 46.973 11.322 47.155 ;
     RECT  6.624 47.155 11.322 47.309 ;
     RECT  2.304 47.111 5.397 47.353 ;
     RECT  0.216 47.281 0.234 47.357 ;
     RECT  14.832 46.643 14.958 47.371 ;
     RECT  2.268 47.353 5.397 47.549 ;
     RECT  16.524 47.179 16.542 47.659 ;
     RECT  2.304 47.549 5.397 47.687 ;
     RECT  6.804 47.309 11.322 47.695 ;
     RECT  12.096 47.039 13.842 47.695 ;
     RECT  2.304 47.687 4.302 47.696 ;
     RECT  14.832 47.371 15.426 47.723 ;
     RECT  6.804 47.695 13.842 47.821 ;
     RECT  14.832 47.723 14.85 47.821 ;
     RECT  2.304 47.696 2.862 47.849 ;
     RECT  6.804 47.821 14.85 47.885 ;
     RECT  1.152 47.899 1.17 48.043 ;
     RECT  5.04 47.687 5.397 48.091 ;
     RECT  1.152 48.043 1.278 48.199 ;
     RECT  5.04 48.091 5.526 48.227 ;
     RECT  6.804 47.885 14.094 48.299 ;
     RECT  2.304 47.849 2.826 48.389 ;
     RECT  6.912 48.299 14.094 48.389 ;
     RECT  3.672 47.696 4.302 48.433 ;
     RECT  5.04 48.227 5.397 48.433 ;
     RECT  16.524 47.659 17.154 48.461 ;
     RECT  7.452 48.389 14.094 48.497 ;
     RECT  14.832 47.885 14.85 48.619 ;
     RECT  12.42 48.497 14.094 48.659 ;
     RECT  0.54 48.199 1.278 48.701 ;
     RECT  3.672 48.433 5.397 48.739 ;
     RECT  0.54 48.701 1.206 48.839 ;
     RECT  0.54 48.839 1.17 48.845 ;
     RECT  0.54 48.845 1.134 48.859 ;
     RECT  0.252 48.859 1.134 49.037 ;
     RECT  0.432 49.037 1.134 49.043 ;
     RECT  14.832 48.619 15.426 49.045 ;
     RECT  0.432 49.043 0.558 49.133 ;
     RECT  2.304 48.389 2.697 49.171 ;
     RECT  3.42 48.739 5.397 49.171 ;
     RECT  7.452 48.497 11.43 49.207 ;
     RECT  16.56 48.461 17.154 49.229 ;
     RECT  16.56 49.229 16.614 49.237 ;
     RECT  2.304 49.171 5.397 49.351 ;
     RECT  7.236 49.207 11.43 49.351 ;
     RECT  12.42 48.659 13.734 49.351 ;
     RECT  7.236 49.351 13.734 49.441 ;
     RECT  14.508 49.045 15.426 49.441 ;
     RECT  7.236 49.441 15.426 49.747 ;
     RECT  0.432 49.133 0.45 49.819 ;
     RECT  6.804 49.747 15.426 49.819 ;
     RECT  0.288 49.819 0.45 49.867 ;
     RECT  0.288 49.867 0.522 49.919 ;
     RECT  0.432 49.919 0.522 49.949 ;
     RECT  2.304 49.351 5.67 50.117 ;
     RECT  5.115 50.117 5.67 50.125 ;
     RECT  6.588 49.819 15.426 50.125 ;
     RECT  0.504 49.949 0.522 50.141 ;
     RECT  16.524 49.237 16.614 50.2 ;
     RECT  16.524 50.2 17.082 50.206 ;
     RECT  2.304 50.117 4.338 50.351 ;
     RECT  5.115 50.125 15.426 50.423 ;
     RECT  16.524 50.206 17.154 50.423 ;
     RECT  6.84 50.423 15.426 50.429 ;
     RECT  2.304 50.351 3.258 50.549 ;
     RECT  5.115 50.423 5.778 50.549 ;
     RECT  2.304 50.549 3.186 50.621 ;
     RECT  2.304 50.621 3.114 50.728 ;
     RECT  7.2 50.429 15.426 50.827 ;
     RECT  3.996 50.351 4.338 50.863 ;
     RECT  3.996 50.863 4.374 50.909 ;
     RECT  4.212 50.909 4.374 50.935 ;
     RECT  5.115 50.549 5.67 50.935 ;
     RECT  1.152 51.019 1.17 51.067 ;
     RECT  4.212 50.935 5.67 51.089 ;
     RECT  7.2 50.827 15.462 51.149 ;
     RECT  7.2 51.149 15.426 51.161 ;
     RECT  4.212 51.089 5.526 51.269 ;
     RECT  2.268 50.728 3.114 51.293 ;
     RECT  7.2 51.161 14.886 51.331 ;
     RECT  7.02 51.331 14.886 51.355 ;
     RECT  6.732 51.355 14.886 51.389 ;
     RECT  2.304 51.293 3.114 51.451 ;
     RECT  17.064 50.423 17.154 51.547 ;
     RECT  1.152 51.067 1.278 51.595 ;
     RECT  1.152 51.595 1.386 51.677 ;
     RECT  4.212 51.269 5.397 51.709 ;
     RECT  1.368 51.677 1.386 51.725 ;
     RECT  16.524 51.547 17.154 51.725 ;
     RECT  6.732 51.389 11.07 51.773 ;
     RECT  0.252 50.971 0.27 51.821 ;
     RECT  2.304 51.451 3.33 51.871 ;
     RECT  4.068 51.709 5.397 51.871 ;
     RECT  11.988 51.389 14.886 51.883 ;
     RECT  11.988 51.883 15.138 51.979 ;
     RECT  2.304 51.871 5.397 52.027 ;
     RECT  2.088 52.027 5.397 52.157 ;
     RECT  7.02 51.773 11.07 52.171 ;
     RECT  2.268 52.157 5.397 52.321 ;
     RECT  2.268 52.321 5.454 52.445 ;
     RECT  16.524 51.725 16.542 52.547 ;
     RECT  7.02 52.171 11.178 52.555 ;
     RECT  11.988 51.979 15.426 52.555 ;
     RECT  7.02 52.555 15.426 52.681 ;
     RECT  6.372 52.681 15.426 52.753 ;
     RECT  2.304 52.445 5.454 52.829 ;
     RECT  6.372 52.753 16.002 52.861 ;
     RECT  0.54 52.861 0.558 52.939 ;
     RECT  0.54 52.939 0.594 52.951 ;
     RECT  6.3 52.861 16.002 52.979 ;
     RECT  2.304 52.829 5.397 53.015 ;
     RECT  0.54 52.951 0.666 53.021 ;
     RECT  4.212 53.015 5.397 53.021 ;
     RECT  0.54 53.021 0.558 53.069 ;
     RECT  7.056 52.979 16.002 53.069 ;
     RECT  2.304 53.015 3.33 53.357 ;
     RECT  0.252 53.323 0.27 53.501 ;
     RECT  4.248 53.021 5.397 53.941 ;
     RECT  1.152 53.947 1.17 53.995 ;
     RECT  4.212 53.941 5.397 54.031 ;
     RECT  7.056 53.069 15.426 54.091 ;
     RECT  6.588 54.091 15.426 54.175 ;
     RECT  4.14 54.031 5.397 54.301 ;
     RECT  1.152 53.995 1.278 54.413 ;
     RECT  6.408 54.175 15.426 54.427 ;
     RECT  2.304 53.357 3.042 54.481 ;
     RECT  1.152 54.413 1.17 54.509 ;
     RECT  2.232 54.481 3.042 54.557 ;
     RECT  6.264 54.427 15.426 54.599 ;
     RECT  2.304 54.557 3.042 54.607 ;
     RECT  3.996 54.301 5.397 54.607 ;
     RECT  6.264 54.599 13.842 54.893 ;
     RECT  2.304 54.607 5.397 54.905 ;
     RECT  3.6 54.905 5.397 55.111 ;
     RECT  6.264 54.893 13.734 55.111 ;
     RECT  16.524 54.283 16.542 55.195 ;
     RECT  16.488 55.195 16.542 55.247 ;
     RECT  16.524 55.247 16.542 55.283 ;
     RECT  3.6 55.111 13.734 55.445 ;
     RECT  3.6 55.445 5.994 55.517 ;
     RECT  2.304 54.905 2.697 55.651 ;
     RECT  6.732 55.445 13.734 55.651 ;
     RECT  2.304 55.651 2.826 55.771 ;
     RECT  3.6 55.517 4.158 55.771 ;
     RECT  14.832 54.599 15.426 56.021 ;
     RECT  17.136 56.011 17.154 56.029 ;
     RECT  17.064 56.029 17.154 56.057 ;
     RECT  17.064 56.057 17.082 56.093 ;
     RECT  2.304 55.771 4.158 56.155 ;
     RECT  5.004 55.517 5.994 56.219 ;
     RECT  2.268 56.155 4.158 56.291 ;
     RECT  2.304 56.291 4.158 56.336 ;
     RECT  6.732 55.651 13.914 56.363 ;
     RECT  2.304 56.336 2.862 56.489 ;
     RECT  3.636 56.336 4.158 56.525 ;
     RECT  3.708 56.525 4.158 56.641 ;
     RECT  5.004 56.219 5.814 56.641 ;
     RECT  2.304 56.489 2.79 56.669 ;
     RECT  14.904 56.021 15.426 56.779 ;
     RECT  1.26 56.683 1.278 56.813 ;
     RECT  16.524 56.347 16.542 56.827 ;
     RECT  16.524 56.827 17.154 57.149 ;
     RECT  7.272 56.363 13.914 57.181 ;
     RECT  3.708 56.641 5.814 57.271 ;
     RECT  7.272 57.181 14.058 57.271 ;
     RECT  6.804 57.271 14.058 57.341 ;
     RECT  3.708 57.271 5.886 57.343 ;
     RECT  0.252 56.251 0.27 57.379 ;
     RECT  2.412 56.669 2.79 57.379 ;
     RECT  2.412 57.379 2.826 57.403 ;
     RECT  0.252 57.379 0.558 57.437 ;
     RECT  7.344 57.341 14.058 57.499 ;
     RECT  14.832 56.779 15.426 57.499 ;
     RECT  2.304 57.403 2.826 57.577 ;
     RECT  3.708 57.343 5.994 57.577 ;
     RECT  7.344 57.499 15.426 57.595 ;
     RECT  0.54 57.437 0.558 57.677 ;
     RECT  2.304 57.577 5.994 57.839 ;
     RECT  2.304 57.839 5.886 57.911 ;
     RECT  7.344 57.595 15.462 57.983 ;
     RECT  7.344 57.983 11.754 58.075 ;
     RECT  3.96 57.911 5.886 58.109 ;
     RECT  7.164 58.075 11.754 58.115 ;
     RECT  3.96 58.109 5.598 58.289 ;
     RECT  12.492 57.983 15.462 58.451 ;
     RECT  0.396 58.363 0.414 58.459 ;
     RECT  0.288 58.459 0.414 58.621 ;
     RECT  1.152 57.883 1.17 58.621 ;
     RECT  0.288 58.621 1.17 58.685 ;
     RECT  0.54 58.685 1.17 58.733 ;
     RECT  7.236 58.115 11.754 58.765 ;
     RECT  12.492 58.451 15.426 58.765 ;
     RECT  6.264 58.891 6.282 58.955 ;
     RECT  2.304 57.911 3.222 58.987 ;
     RECT  3.96 58.289 5.397 58.987 ;
     RECT  2.304 58.987 5.397 59.099 ;
     RECT  7.236 58.765 15.426 59.189 ;
     RECT  2.304 59.099 2.754 59.213 ;
     RECT  7.344 59.189 15.426 59.26 ;
     RECT  1.152 58.733 1.17 59.323 ;
     RECT  3.528 59.099 5.397 59.341 ;
     RECT  3.528 59.341 5.886 59.459 ;
     RECT  3.528 59.459 5.598 59.504 ;
     RECT  7.344 59.26 15.462 59.531 ;
     RECT  1.152 59.323 1.278 59.549 ;
     RECT  7.344 59.531 15.426 59.947 ;
     RECT  7.272 59.947 15.426 60.007 ;
     RECT  2.304 59.213 2.697 60.241 ;
     RECT  6.948 60.007 15.426 60.305 ;
     RECT  1.152 59.549 1.17 60.317 ;
     RECT  2.304 60.241 2.862 60.331 ;
     RECT  3.636 59.504 5.598 60.331 ;
     RECT  6.948 60.305 13.734 60.349 ;
     RECT  2.304 60.331 5.598 60.413 ;
     RECT  3.42 60.413 5.598 60.619 ;
     RECT  3.42 60.619 5.958 60.647 ;
     RECT  6.84 60.349 13.734 60.809 ;
     RECT  5.115 60.647 5.958 60.917 ;
     RECT  2.304 60.413 2.697 60.955 ;
     RECT  6.84 60.809 13.698 60.989 ;
     RECT  6.84 60.989 13.662 61.051 ;
     RECT  16.524 57.149 16.542 61.051 ;
     RECT  16.524 61.051 17.082 61.087 ;
     RECT  16.524 61.087 17.154 61.133 ;
     RECT  14.832 60.305 15.426 61.147 ;
     RECT  14.58 61.147 15.426 61.259 ;
     RECT  2.268 60.955 2.697 61.387 ;
     RECT  3.42 60.647 4.302 61.387 ;
     RECT  16.524 61.133 16.542 61.421 ;
     RECT  2.268 61.387 4.302 61.435 ;
     RECT  5.115 60.917 5.397 61.435 ;
     RECT  2.268 61.435 5.397 61.493 ;
     RECT  4.932 61.493 5.397 61.663 ;
     RECT  6.732 61.051 13.662 61.699 ;
     RECT  6.66 61.699 13.662 61.771 ;
     RECT  2.268 61.493 4.014 61.799 ;
     RECT  4.932 61.663 5.454 61.861 ;
     RECT  14.832 61.259 15.426 62.033 ;
     RECT  14.832 62.033 14.994 62.141 ;
     RECT  6.66 61.771 14.058 62.155 ;
     RECT  6.264 62.155 14.058 62.239 ;
     RECT  14.832 62.141 14.922 62.239 ;
     RECT  2.304 61.799 4.014 62.251 ;
     RECT  4.932 61.861 5.526 62.275 ;
     RECT  6.264 62.239 14.922 62.275 ;
     RECT  2.304 62.251 4.158 62.299 ;
     RECT  4.932 62.275 14.922 62.299 ;
     RECT  16.524 62.167 16.542 62.635 ;
     RECT  0.252 61.291 0.27 62.669 ;
     RECT  15.984 62.635 16.542 62.879 ;
     RECT  2.304 62.299 14.922 62.971 ;
     RECT  2.304 62.971 14.994 63.005 ;
     RECT  6.696 63.005 14.994 63.245 ;
     RECT  0.54 63.085 0.558 63.293 ;
     RECT  6.732 63.245 14.994 63.293 ;
     RECT  14.328 63.293 14.994 63.341 ;
     RECT  14.472 63.341 14.994 63.355 ;
     RECT  15.984 62.879 16.002 63.355 ;
     RECT  2.304 63.005 5.958 63.653 ;
     RECT  2.304 63.653 4.014 63.821 ;
     RECT  6.732 63.293 13.554 63.851 ;
     RECT  14.472 63.355 16.002 63.917 ;
     RECT  2.304 63.821 3.078 64.219 ;
     RECT  4.824 63.653 5.958 64.315 ;
     RECT  6.732 63.851 11.826 64.315 ;
     RECT  2.268 64.219 3.078 64.319 ;
     RECT  16.524 64.171 16.578 64.355 ;
     RECT  12.564 63.851 13.554 64.399 ;
     RECT  14.472 63.917 15.426 64.399 ;
     RECT  3.996 63.821 4.014 64.411 ;
     RECT  4.824 64.315 11.826 64.411 ;
     RECT  2.304 64.319 3.078 64.561 ;
     RECT  3.996 64.411 11.826 64.561 ;
     RECT  16.56 64.355 16.578 64.637 ;
     RECT  2.304 64.561 11.826 64.741 ;
     RECT  12.564 64.399 15.426 64.741 ;
     RECT  2.304 64.741 15.426 64.877 ;
     RECT  6.84 64.877 15.426 64.967 ;
     RECT  6.876 64.967 15.426 64.973 ;
     RECT  0.216 64.939 0.306 64.987 ;
     RECT  0.216 64.987 0.378 65.039 ;
     RECT  0.216 65.039 0.27 65.069 ;
     RECT  7.236 64.973 15.426 65.137 ;
     RECT  16.524 65.131 16.542 65.137 ;
     RECT  7.236 65.137 16.542 65.261 ;
     RECT  7.236 65.261 15.462 65.713 ;
     RECT  0.252 65.069 0.27 65.741 ;
     RECT  2.304 64.877 5.706 65.741 ;
     RECT  6.84 65.713 15.462 65.741 ;
     RECT  16.524 65.261 16.542 65.777 ;
     RECT  5.115 65.741 5.706 65.947 ;
     RECT  6.84 65.741 13.554 65.947 ;
     RECT  14.364 65.741 15.462 65.975 ;
     RECT  14.652 65.975 15.462 66.083 ;
     RECT  2.304 65.741 4.374 66.209 ;
     RECT  2.304 66.209 4.23 66.325 ;
     RECT  2.232 66.325 4.23 66.413 ;
     RECT  5.115 65.947 13.554 66.475 ;
     RECT  14.724 66.083 15.462 66.551 ;
     RECT  17.064 66.235 17.154 66.56 ;
     RECT  14.724 66.551 15.426 66.623 ;
     RECT  16.524 66.619 16.542 66.857 ;
     RECT  5.115 66.475 13.734 67.019 ;
     RECT  2.304 66.413 4.23 67.099 ;
     RECT  5.115 67.019 5.397 67.099 ;
     RECT  6.264 67.019 13.734 67.099 ;
     RECT  6.264 67.099 13.842 67.229 ;
     RECT  2.304 67.099 5.397 67.243 ;
     RECT  6.84 67.229 13.842 67.261 ;
     RECT  17.064 67.339 17.082 67.369 ;
     RECT  17.064 67.369 17.154 67.397 ;
     RECT  14.832 66.623 15.426 67.405 ;
     RECT  2.088 67.243 5.397 67.421 ;
     RECT  2.268 67.421 5.397 67.565 ;
     RECT  14.832 67.405 15.498 67.565 ;
     RECT  6.84 67.261 13.914 67.801 ;
     RECT  14.832 67.565 15.426 67.801 ;
     RECT  0.54 67.801 0.558 67.867 ;
     RECT  0.54 67.867 0.666 67.997 ;
     RECT  6.84 67.801 15.426 68.107 ;
     RECT  17.136 67.397 17.154 68.143 ;
     RECT  17.064 68.143 17.154 68.171 ;
     RECT  17.064 68.171 17.082 68.189 ;
     RECT  6.768 68.107 15.426 68.347 ;
     RECT  6.408 68.347 15.426 68.369 ;
     RECT  6.408 68.369 14.022 68.405 ;
     RECT  0.54 67.997 0.558 68.429 ;
     RECT  2.304 67.565 5.397 68.639 ;
     RECT  7.02 68.405 14.022 68.675 ;
     RECT  14.832 68.369 15.426 68.711 ;
     RECT  5.115 68.639 5.397 68.731 ;
     RECT  0.252 68.731 0.27 68.953 ;
     RECT  2.304 68.639 4.086 68.953 ;
     RECT  5.115 68.731 5.67 68.953 ;
     RECT  0.216 68.953 0.27 68.962 ;
     RECT  0.216 68.962 0.234 69.053 ;
     RECT  2.232 68.953 4.086 69.089 ;
     RECT  5.115 68.953 6.03 69.179 ;
     RECT  5.115 69.179 5.742 69.293 ;
     RECT  7.272 68.675 14.022 69.331 ;
     RECT  14.832 68.711 14.886 69.547 ;
     RECT  7.272 69.331 14.094 69.565 ;
     RECT  14.832 69.547 15.426 69.565 ;
     RECT  2.304 69.089 4.086 69.691 ;
     RECT  5.115 69.293 5.397 69.691 ;
     RECT  2.304 69.691 4.266 69.727 ;
     RECT  5.004 69.691 5.397 69.727 ;
     RECT  7.272 69.565 15.426 69.739 ;
     RECT  7.272 69.739 15.462 69.763 ;
     RECT  0.396 69.739 0.414 69.835 ;
     RECT  6.984 69.763 15.462 69.863 ;
     RECT  0.288 69.835 0.414 69.869 ;
     RECT  0.288 69.869 0.306 70.013 ;
     RECT  2.304 69.727 5.397 70.013 ;
     RECT  16.524 68.347 16.542 70.061 ;
     RECT  6.984 69.863 15.426 70.363 ;
     RECT  6.804 70.363 15.426 70.367 ;
     RECT  14.58 70.367 15.426 70.637 ;
     RECT  4.032 70.013 5.397 70.681 ;
     RECT  2.304 70.013 3.222 70.699 ;
     RECT  2.268 70.699 3.222 70.799 ;
     RECT  2.304 70.799 3.222 70.807 ;
     RECT  4.032 70.681 5.706 70.843 ;
     RECT  6.804 70.367 13.842 70.843 ;
     RECT  2.304 70.807 3.258 70.951 ;
     RECT  4.032 70.843 13.842 70.951 ;
     RECT  2.304 70.951 13.842 71.069 ;
     RECT  6.876 71.069 13.842 71.179 ;
     RECT  14.58 70.637 15.066 71.179 ;
     RECT  16.524 70.987 16.542 71.323 ;
     RECT  16.524 71.323 16.578 71.491 ;
     RECT  6.876 71.179 15.066 71.609 ;
     RECT  14.832 71.609 15.066 71.611 ;
     RECT  15.984 71.491 16.578 71.611 ;
     RECT  14.832 71.611 16.578 71.741 ;
     RECT  14.832 71.741 15.426 71.789 ;
     RECT  16.524 71.741 16.578 71.789 ;
     RECT  2.304 71.069 6.066 71.803 ;
     RECT  6.876 71.609 13.986 71.803 ;
     RECT  0.252 71.131 0.27 71.851 ;
     RECT  0.252 71.851 0.45 71.995 ;
     RECT  0.252 71.995 0.522 72.059 ;
     RECT  0.252 72.059 0.45 72.077 ;
     RECT  2.304 71.803 13.986 72.149 ;
     RECT  4.248 72.149 13.986 72.293 ;
     RECT  0.252 72.077 0.27 72.365 ;
     RECT  5.076 72.293 13.986 72.419 ;
     RECT  5.076 72.419 11.502 72.509 ;
     RECT  12.348 72.419 13.986 72.571 ;
     RECT  14.868 71.789 15.426 72.571 ;
     RECT  16.524 71.789 16.542 72.715 ;
     RECT  16.524 72.715 17.154 72.761 ;
     RECT  16.524 72.761 17.082 72.797 ;
     RECT  16.524 72.797 16.578 72.833 ;
     RECT  4.248 72.293 4.266 72.959 ;
     RECT  5.115 72.509 11.502 72.959 ;
     RECT  16.56 72.833 16.578 73.067 ;
     RECT  5.115 72.959 5.397 73.187 ;
     RECT  0.288 73.051 0.306 73.195 ;
     RECT  5.115 73.187 5.274 73.229 ;
     RECT  6.264 72.959 11.502 73.229 ;
     RECT  12.348 72.571 15.426 73.229 ;
     RECT  12.348 73.229 13.626 73.265 ;
     RECT  6.336 73.229 8.91 73.277 ;
     RECT  2.304 72.149 3.51 73.291 ;
     RECT  6.408 73.277 8.91 73.301 ;
     RECT  9.828 73.229 11.502 73.301 ;
     RECT  12.888 73.265 13.626 73.301 ;
     RECT  0.288 73.195 0.414 73.325 ;
     RECT  14.364 73.229 15.426 73.325 ;
     RECT  14.364 73.325 14.886 73.337 ;
     RECT  6.408 73.301 8.802 73.373 ;
     RECT  9.864 73.301 11.502 73.381 ;
     RECT  2.304 73.291 3.87 73.409 ;
     RECT  9.864 73.381 12.078 73.409 ;
     RECT  13.215 73.301 13.626 73.409 ;
     RECT  2.304 73.409 2.505 73.421 ;
     RECT  6.408 73.373 8.73 73.421 ;
     RECT  14.364 73.337 14.85 73.421 ;
     RECT  2.415 73.421 2.505 73.457 ;
     RECT  5.115 73.229 5.205 73.457 ;
     RECT  13.215 73.409 13.305 73.457 ;
     RECT  6.408 73.421 8.478 73.499 ;
     RECT  12.06 73.409 12.078 73.499 ;
     RECT  3.852 73.409 3.87 73.535 ;
     RECT  9.972 73.409 10.854 73.535 ;
     RECT  14.364 73.421 14.382 73.535 ;
     RECT  7.596 73.499 8.478 73.565 ;
     RECT  7.668 73.565 8.154 73.571 ;
     RECT  9.972 73.535 9.99 73.571 ;
     RECT  8.136 73.571 8.154 74.141 ;
     RECT  5.4 74.683 5.418 75.468 ;
    LAYER M4 ;
     RECT  0.156 2.208 2.408 73.416 ;
     RECT  2.408 2.148 2.512 73.452 ;
     RECT  2.512 2.352 2.837 73.32 ;
     RECT  2.837 14.208 2.873 73.32 ;
     RECT  2.873 14.208 3.377 70.584 ;
     RECT  2.837 2.352 3.841 12.888 ;
     RECT  3.377 14.208 3.841 29.832 ;
     RECT  3.377 30.912 4.309 70.584 ;
     RECT  2.873 71.712 4.309 73.32 ;
     RECT  3.841 2.352 5.108 29.832 ;
     RECT  4.309 30.912 5.108 73.32 ;
     RECT  5.108 2.148 5.212 73.452 ;
     RECT  5.212 2.418 5.404 73.32 ;
     RECT  5.404 20.592 5.465 27.624 ;
     RECT  5.389 74.688 5.603 74.712 ;
     RECT  5.465 20.592 5.645 24.456 ;
     RECT  5.404 2.832 6.397 19.608 ;
     RECT  5.645 20.592 6.397 22.008 ;
     RECT  6.397 2.832 6.613 22.008 ;
     RECT  5.465 25.728 6.793 27.624 ;
     RECT  5.404 45.456 6.793 45.768 ;
     RECT  5.404 46.848 6.793 47.688 ;
     RECT  5.404 48.72 6.793 73.32 ;
     RECT  6.613 2.784 6.829 22.008 ;
     RECT  5.645 23.616 6.829 24.456 ;
     RECT  6.829 2.784 6.865 22.344 ;
     RECT  6.829 23.616 6.865 24.744 ;
     RECT  6.865 2.784 6.901 24.744 ;
     RECT  6.793 25.728 6.901 27.672 ;
     RECT  5.404 31.488 6.973 44.376 ;
     RECT  5.404 28.704 7.081 29.784 ;
     RECT  6.973 30.864 7.081 44.376 ;
     RECT  6.901 2.784 7.117 27.672 ;
     RECT  7.081 28.704 7.117 44.376 ;
     RECT  7.117 2.784 7.261 44.376 ;
     RECT  7.261 2.448 7.333 44.376 ;
     RECT  6.793 45.456 7.333 73.32 ;
     RECT  7.333 2.448 7.585 73.32 ;
     RECT  7.585 2.448 7.808 73.56 ;
     RECT  7.808 2.148 7.912 73.56 ;
     RECT  7.912 2.352 8.125 73.56 ;
     RECT  8.125 2.352 9.457 74.136 ;
     RECT  9.457 2.256 10.508 74.136 ;
     RECT  10.508 2.148 10.612 74.136 ;
     RECT  10.612 2.256 10.865 74.136 ;
     RECT  10.865 2.304 11.045 74.136 ;
     RECT  11.045 2.496 11.891 74.136 ;
     RECT  11.891 2.496 13.208 73.32 ;
     RECT  13.208 2.148 13.312 73.452 ;
     RECT  13.312 2.418 13.504 73.32 ;
     RECT  13.504 2.496 13.637 73.32 ;
     RECT  13.637 2.496 14.821 73.08 ;
     RECT  14.821 2.496 15.397 73.416 ;
     RECT  15.397 2.208 17.1 73.416 ;
     RECT  17.1 2.784 17.165 2.808 ;
     RECT  17.1 5.28 17.165 5.304 ;
     RECT  17.1 7.104 17.165 7.128 ;
     RECT  17.1 9.264 17.165 9.288 ;
     RECT  17.1 12.816 17.165 13.608 ;
     RECT  17.1 16.608 17.165 16.632 ;
     RECT  17.1 17.76 17.165 17.976 ;
     RECT  17.1 20.064 17.165 21.192 ;
     RECT  17.1 24.096 17.165 24.12 ;
     RECT  17.1 27.984 17.165 28.728 ;
     RECT  17.1 32.256 17.165 32.28 ;
     RECT  17.1 33.312 17.165 33.336 ;
     RECT  17.1 34.896 17.165 34.92 ;
     RECT  17.1 39.504 17.165 39.816 ;
     RECT  17.1 41.376 17.165 41.688 ;
     RECT  17.1 43.68 17.165 43.704 ;
     RECT  17.1 45.984 17.165 46.632 ;
     RECT  17.1 47.664 17.165 49.224 ;
     RECT  17.1 50.256 17.165 51.72 ;
     RECT  17.1 56.016 17.165 57.144 ;
     RECT  17.1 61.104 17.165 61.128 ;
     RECT  17.1 66.24 17.165 68.136 ;
     RECT  17.1 72.72 17.165 72.744 ;
    LAYER M5 ;
     RECT  2.4 2.137 2.52 2.151 ;
     RECT  5.1 2.137 5.22 2.151 ;
     RECT  7.8 2.137 7.92 2.151 ;
     RECT  10.5 2.137 10.62 2.151 ;
     RECT  13.2 2.137 13.32 2.151 ;
     RECT  10.5 2.151 10.812 2.773 ;
     RECT  9.744 2.773 10.812 3.397 ;
     RECT  9.36 3.397 10.812 4.451 ;
     RECT  9.36 4.451 9.384 4.643 ;
     RECT  7.8 2.151 8.112 4.789 ;
     RECT  7.8 4.789 8.28 5.123 ;
     RECT  7.8 5.123 8.232 5.891 ;
     RECT  10.5 4.451 10.812 6.853 ;
     RECT  9.936 6.853 10.812 7.237 ;
     RECT  14.832 6.901 14.856 7.379 ;
     RECT  9.936 7.237 11.736 7.381 ;
     RECT  13.2 2.151 13.512 7.381 ;
     RECT  9.936 7.381 13.512 8.195 ;
     RECT  10.5 8.195 13.512 9.683 ;
     RECT  0.288 10.117 0.312 10.355 ;
     RECT  9.408 10.213 9.432 11.651 ;
     RECT  13.2 9.683 13.512 12.037 ;
     RECT  10.5 9.683 11.736 12.229 ;
     RECT  13.2 12.037 13.944 12.229 ;
     RECT  9.12 11.797 9.24 12.323 ;
     RECT  10.5 12.229 13.944 12.323 ;
     RECT  10.5 12.323 13.848 12.371 ;
     RECT  7.8 5.891 8.112 12.517 ;
     RECT  9.12 12.323 9.144 12.517 ;
     RECT  7.8 12.517 9.144 12.563 ;
     RECT  10.5 12.371 13.512 13.715 ;
     RECT  13.2 13.715 13.512 13.861 ;
     RECT  13.2 13.861 14.04 14.195 ;
     RECT  13.2 14.195 13.944 14.243 ;
     RECT  6.768 15.349 6.792 16.069 ;
     RECT  7.8 12.563 8.712 16.069 ;
     RECT  6.768 16.069 8.712 16.115 ;
     RECT  2.4 2.151 2.712 16.213 ;
     RECT  6.864 16.115 8.712 16.213 ;
     RECT  10.5 13.715 11.736 16.213 ;
     RECT  6.864 16.213 9.144 16.259 ;
     RECT  6.96 16.259 9.144 16.307 ;
     RECT  13.2 14.243 13.512 16.309 ;
     RECT  2.256 16.213 2.712 16.403 ;
     RECT  10.368 16.213 11.736 16.403 ;
     RECT  13.2 16.309 13.608 16.451 ;
     RECT  7.8 16.307 9.144 16.597 ;
     RECT  7.8 16.597 9.288 17.461 ;
     RECT  10.5 16.403 11.736 17.461 ;
     RECT  7.8 17.461 11.736 17.651 ;
     RECT  2.4 16.403 2.712 17.701 ;
     RECT  13.2 16.451 13.512 17.941 ;
     RECT  13.2 17.941 13.944 18.179 ;
     RECT  2.208 17.701 2.712 18.373 ;
     RECT  2.16 18.373 2.712 18.515 ;
     RECT  7.8 17.651 11.16 18.515 ;
     RECT  2.304 18.515 2.712 19.091 ;
     RECT  7.8 18.515 10.812 19.333 ;
     RECT  13.2 18.179 13.512 19.765 ;
     RECT  13.2 19.765 13.656 19.907 ;
     RECT  7.68 19.333 10.812 20.675 ;
     RECT  7.8 20.675 10.812 20.723 ;
     RECT  12 21.397 12.024 22.021 ;
     RECT  13.2 19.907 13.512 22.021 ;
     RECT  7.8 20.723 8.232 22.789 ;
     RECT  9.696 20.723 10.812 23.123 ;
     RECT  7.68 22.789 8.232 23.365 ;
     RECT  12 22.021 13.512 23.411 ;
     RECT  7.68 23.365 8.712 23.555 ;
     RECT  7.68 23.555 8.232 23.843 ;
     RECT  9.936 23.123 10.812 24.661 ;
     RECT  9.936 24.661 11.016 24.947 ;
     RECT  12.576 23.411 13.512 25.187 ;
     RECT  7.8 23.843 8.232 25.237 ;
     RECT  2.4 19.091 2.712 25.381 ;
     RECT  2.064 25.381 2.712 25.571 ;
     RECT  7.8 25.237 8.28 26.341 ;
     RECT  9.936 24.947 10.812 26.341 ;
     RECT  13.2 25.187 13.512 26.389 ;
     RECT  14.832 25.957 14.856 26.389 ;
     RECT  7.8 26.341 10.812 26.627 ;
     RECT  13.2 26.389 14.856 26.627 ;
     RECT  2.4 25.571 2.712 27.109 ;
     RECT  14.832 26.627 14.856 27.251 ;
     RECT  2.4 27.109 2.808 27.347 ;
     RECT  9.936 26.627 10.812 28.693 ;
     RECT  7.8 26.627 8.232 29.029 ;
     RECT  9.936 28.693 11.352 29.075 ;
     RECT  2.4 27.347 2.712 29.221 ;
     RECT  2.4 29.221 2.856 29.363 ;
     RECT  7.584 29.029 8.232 29.603 ;
     RECT  9.936 29.075 11.208 29.603 ;
     RECT  7.584 29.603 8.112 29.939 ;
     RECT  9.936 29.603 10.812 30.181 ;
     RECT  2.4 29.363 2.712 30.901 ;
     RECT  7.68 29.939 8.112 31.045 ;
     RECT  9.552 30.181 10.812 31.045 ;
     RECT  2.4 30.901 2.856 31.139 ;
     RECT  16.992 30.757 17.016 31.235 ;
     RECT  7.68 31.045 10.812 31.283 ;
     RECT  9.12 31.283 10.812 32.099 ;
     RECT  7.68 31.283 8.112 33.013 ;
     RECT  9.552 32.099 10.812 33.013 ;
     RECT  13.2 26.627 13.512 33.061 ;
     RECT  13.104 33.061 13.512 33.635 ;
     RECT  1.248 33.829 1.272 33.971 ;
     RECT  7.584 33.013 8.112 34.981 ;
     RECT  7.584 34.981 8.28 35.123 ;
     RECT  9.552 33.013 11.784 35.219 ;
     RECT  12.048 35.413 12.072 35.555 ;
     RECT  7.584 35.123 8.112 36.515 ;
     RECT  9.552 35.219 10.812 36.515 ;
     RECT  9.936 36.515 10.812 37.573 ;
     RECT  5.1 2.151 5.412 37.909 ;
     RECT  9.408 37.573 10.812 38.197 ;
     RECT  7.8 36.515 8.112 39.013 ;
     RECT  9.408 38.197 11.016 39.731 ;
     RECT  13.2 33.635 13.512 40.405 ;
     RECT  13.104 40.405 13.512 40.595 ;
     RECT  9.408 39.731 10.812 40.789 ;
     RECT  9.12 40.789 10.812 40.979 ;
     RECT  9.408 40.979 10.812 41.699 ;
     RECT  7.296 39.013 8.112 41.749 ;
     RECT  7.008 41.749 8.112 41.891 ;
     RECT  14.832 41.845 14.856 42.083 ;
     RECT  2.4 31.139 2.712 42.757 ;
     RECT  2.4 42.757 2.808 42.899 ;
     RECT  14.928 43.093 14.952 43.331 ;
     RECT  7.296 41.891 8.112 44.677 ;
     RECT  7.296 44.677 8.616 45.443 ;
     RECT  0.288 45.445 0.312 45.587 ;
     RECT  13.2 40.595 13.512 45.685 ;
     RECT  13.2 45.685 13.656 46.019 ;
     RECT  9.792 41.699 10.812 46.213 ;
     RECT  14.832 46.213 14.856 46.451 ;
     RECT  13.2 46.019 13.512 47.077 ;
     RECT  7.296 45.443 8.112 47.269 ;
     RECT  13.2 47.077 13.608 47.413 ;
     RECT  13.2 47.413 13.944 47.699 ;
     RECT  6.624 47.269 8.112 48.373 ;
     RECT  9.12 46.213 10.812 48.373 ;
     RECT  1.152 48.709 1.176 49.043 ;
     RECT  6.624 48.373 10.812 49.043 ;
     RECT  0.288 49.909 0.312 50.099 ;
     RECT  9.792 49.043 10.812 50.293 ;
     RECT  9.12 50.293 10.812 50.965 ;
     RECT  6.624 49.043 8.112 51.107 ;
     RECT  13.2 47.699 13.512 51.109 ;
     RECT  9.12 50.965 10.92 51.155 ;
     RECT  13.2 51.109 13.656 51.251 ;
     RECT  1.248 51.397 1.272 51.731 ;
     RECT  9.792 51.155 10.92 52.739 ;
     RECT  9.792 52.739 10.812 53.075 ;
     RECT  9.12 53.173 9.384 53.315 ;
     RECT  13.2 51.251 13.512 53.461 ;
     RECT  12.624 53.461 13.512 53.603 ;
     RECT  9.36 53.315 9.384 54.371 ;
     RECT  13.2 53.603 13.512 54.901 ;
     RECT  10.5 53.075 10.812 55.237 ;
     RECT  7.296 51.107 8.112 56.389 ;
     RECT  7.296 56.389 8.232 56.675 ;
     RECT  10.5 55.237 10.92 56.771 ;
     RECT  1.152 56.773 1.176 56.915 ;
     RECT  7.296 56.675 8.112 57.829 ;
     RECT  7.296 57.829 8.904 57.973 ;
     RECT  7.296 57.973 9.144 58.019 ;
     RECT  9.12 58.019 9.144 58.163 ;
     RECT  12.48 54.901 13.512 59.603 ;
     RECT  10.5 56.771 10.812 59.653 ;
     RECT  10.5 59.653 10.92 59.843 ;
     RECT  10.5 59.843 10.812 59.845 ;
     RECT  7.296 58.019 8.112 59.987 ;
     RECT  10.368 59.845 10.812 60.611 ;
     RECT  12.576 59.603 13.512 62.435 ;
     RECT  10.5 60.611 10.812 63.589 ;
     RECT  7.44 59.987 8.112 63.781 ;
     RECT  9.504 62.629 9.528 63.781 ;
     RECT  7.44 63.781 9.528 64.501 ;
     RECT  6.864 64.501 9.528 64.643 ;
     RECT  2.4 42.899 2.712 64.741 ;
     RECT  2.304 64.741 2.712 64.931 ;
     RECT  10.5 63.589 11.016 64.931 ;
     RECT  13.2 62.435 13.512 65.557 ;
     RECT  12.624 65.557 13.512 65.747 ;
     RECT  2.4 64.931 2.712 66.709 ;
     RECT  7.44 64.643 9.528 66.757 ;
     RECT  10.5 64.931 10.812 66.757 ;
     RECT  2.064 66.709 2.712 66.899 ;
     RECT  7.44 66.757 10.812 66.947 ;
     RECT  7.44 66.947 9.528 67.091 ;
     RECT  7.8 67.091 9.528 67.523 ;
     RECT  9.12 67.523 9.528 68.051 ;
     RECT  2.4 66.899 2.712 69.733 ;
     RECT  13.2 65.747 13.512 69.781 ;
     RECT  2.4 69.733 2.808 69.875 ;
     RECT  13.2 69.781 13.944 70.067 ;
     RECT  9.504 68.051 9.528 70.739 ;
     RECT  5.1 37.909 5.592 71.077 ;
     RECT  7.8 67.523 8.112 71.317 ;
     RECT  7.8 71.317 8.328 71.459 ;
     RECT  10.5 66.947 10.812 71.797 ;
     RECT  7.8 71.459 8.112 72.133 ;
     RECT  14.832 71.941 14.856 72.179 ;
     RECT  10.5 71.797 10.92 72.419 ;
     RECT  4.416 71.077 5.592 72.947 ;
     RECT  6.864 72.133 8.112 72.995 ;
     RECT  2.4 69.875 2.712 73.449 ;
     RECT  7.8 72.995 8.112 73.449 ;
     RECT  10.5 72.419 10.812 73.449 ;
     RECT  13.2 70.067 13.512 73.449 ;
     RECT  2.4 73.449 2.52 73.463 ;
     RECT  5.1 72.947 5.592 73.463 ;
     RECT  7.8 73.449 7.92 73.463 ;
     RECT  10.5 73.449 10.62 73.463 ;
     RECT  13.2 73.449 13.32 73.463 ;
     RECT  5.568 73.463 5.592 74.723 ;
     RECT  11.856 74.101 11.88 75.472 ;
  END
END dsfd_dvrly_682_EW
END LIBRARY
